VERSION 5.8 ;
BUSBITCHARS "[]" ;
DIVIDERCHAR "/" ;

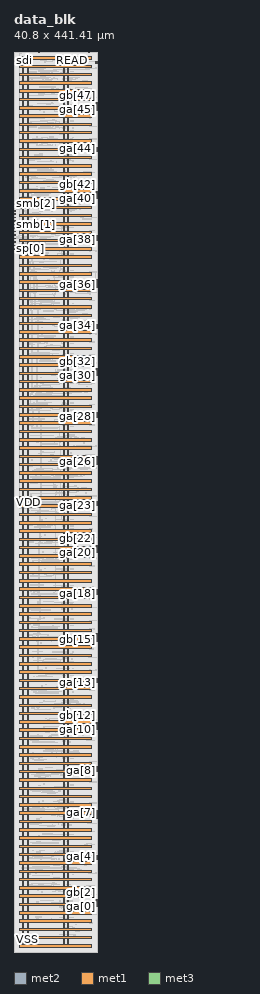
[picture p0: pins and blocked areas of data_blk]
MACRO data_blk
  CLASS BLOCK ;
  FOREIGN data_blk 0 0 ;
  ORIGIN 0 0 ;
  SIZE 40.800 BY 441.410 ;
  SYMMETRY X Y ;
  PIN READ
    DIRECTION INPUT ;
    USE SIGNAL ;
    PORT
      LAYER met2 ;
        RECT 28.490 440.925 28.630 441.410 ;
    END
  END READ
  PIN VDD
    DIRECTION INOUT ;
    USE POWER ;
    PORT
      LAYER met1 ;
        RECT 2.880 2.335 37.920 3.585 ;
        RECT 2.880 10.475 37.920 11.725 ;
        RECT 2.880 18.615 37.920 19.865 ;
        RECT 2.880 26.755 37.920 28.005 ;
        RECT 2.880 34.895 37.920 36.145 ;
        RECT 2.880 43.035 37.920 44.285 ;
        RECT 2.880 51.175 37.920 52.425 ;
        RECT 2.880 59.315 37.920 60.565 ;
        RECT 2.880 67.455 37.920 68.705 ;
        RECT 2.880 75.595 37.920 76.845 ;
        RECT 2.880 83.735 37.920 84.985 ;
        RECT 2.880 91.875 37.920 93.125 ;
        RECT 2.880 100.015 37.920 101.265 ;
        RECT 2.880 108.155 37.920 109.405 ;
        RECT 2.880 116.295 37.920 117.545 ;
        RECT 2.880 124.435 37.920 125.685 ;
        RECT 2.880 132.575 37.920 133.825 ;
        RECT 2.880 140.715 37.920 141.965 ;
        RECT 2.880 148.855 37.920 150.105 ;
        RECT 2.880 156.995 37.920 158.245 ;
        RECT 2.880 165.135 37.920 166.385 ;
        RECT 2.880 173.275 37.920 174.525 ;
        RECT 2.880 181.415 37.920 182.665 ;
        RECT 2.880 189.555 37.920 190.805 ;
        RECT 2.880 197.695 37.920 198.945 ;
        RECT 2.880 205.835 37.920 207.085 ;
        RECT 2.880 213.975 37.920 215.225 ;
        RECT 2.880 222.115 37.920 223.365 ;
        RECT 2.880 230.255 37.920 231.505 ;
        RECT 2.880 238.395 37.920 239.645 ;
        RECT 2.880 246.535 37.920 247.785 ;
        RECT 2.880 254.675 37.920 255.925 ;
        RECT 2.880 262.815 37.920 264.065 ;
        RECT 2.880 270.955 37.920 272.205 ;
        RECT 2.880 279.095 37.920 280.345 ;
        RECT 2.880 287.235 37.920 288.485 ;
        RECT 2.880 295.375 37.920 296.625 ;
        RECT 2.880 303.515 37.920 304.765 ;
        RECT 2.880 311.655 37.920 312.905 ;
        RECT 2.880 319.795 37.920 321.045 ;
        RECT 2.880 327.935 37.920 329.185 ;
        RECT 2.880 336.075 37.920 337.325 ;
        RECT 2.880 344.215 37.920 345.465 ;
        RECT 2.880 352.355 37.920 353.605 ;
        RECT 2.880 360.495 37.920 361.745 ;
        RECT 2.880 368.635 37.920 369.885 ;
        RECT 2.880 376.775 37.920 378.025 ;
        RECT 2.880 384.915 37.920 386.165 ;
        RECT 2.880 393.055 37.920 394.305 ;
        RECT 2.880 401.195 37.920 402.445 ;
        RECT 2.880 409.335 37.920 410.585 ;
        RECT 2.880 417.475 37.920 418.725 ;
        RECT 2.880 425.615 37.920 426.865 ;
        RECT 2.880 433.755 37.920 435.005 ;
      LAYER met2 ;
        RECT 4.380 2.060 4.880 439.350 ;
        RECT 24.380 2.060 24.880 439.350 ;
    END
  END VDD
  PIN VSS
    DIRECTION INOUT ;
    USE GROUND ;
    PORT
      LAYER met1 ;
        RECT 2.880 6.405 37.920 7.655 ;
        RECT 2.880 14.545 37.920 15.795 ;
        RECT 2.880 22.685 37.920 23.935 ;
        RECT 2.880 30.825 37.920 32.075 ;
        RECT 2.880 38.965 37.920 40.215 ;
        RECT 2.880 47.105 37.920 48.355 ;
        RECT 2.880 55.245 37.920 56.495 ;
        RECT 2.880 63.385 37.920 64.635 ;
        RECT 2.880 71.525 37.920 72.775 ;
        RECT 2.880 79.665 37.920 80.915 ;
        RECT 2.880 87.805 37.920 89.055 ;
        RECT 2.880 95.945 37.920 97.195 ;
        RECT 2.880 104.085 37.920 105.335 ;
        RECT 2.880 112.225 37.920 113.475 ;
        RECT 2.880 120.365 37.920 121.615 ;
        RECT 2.880 128.505 37.920 129.755 ;
        RECT 2.880 136.645 37.920 137.895 ;
        RECT 2.880 144.785 37.920 146.035 ;
        RECT 2.880 152.925 37.920 154.175 ;
        RECT 2.880 161.065 37.920 162.315 ;
        RECT 2.880 169.205 37.920 170.455 ;
        RECT 2.880 177.345 37.920 178.595 ;
        RECT 2.880 185.485 37.920 186.735 ;
        RECT 2.880 193.625 37.920 194.875 ;
        RECT 2.880 201.765 37.920 203.015 ;
        RECT 2.880 209.905 37.920 211.155 ;
        RECT 2.880 218.045 37.920 219.295 ;
        RECT 2.880 226.185 37.920 227.435 ;
        RECT 2.880 234.325 37.920 235.575 ;
        RECT 2.880 242.465 37.920 243.715 ;
        RECT 2.880 250.605 37.920 251.855 ;
        RECT 2.880 258.745 37.920 259.995 ;
        RECT 2.880 266.885 37.920 268.135 ;
        RECT 2.880 275.025 37.920 276.275 ;
        RECT 2.880 283.165 37.920 284.415 ;
        RECT 2.880 291.305 37.920 292.555 ;
        RECT 2.880 299.445 37.920 300.695 ;
        RECT 2.880 307.585 37.920 308.835 ;
        RECT 2.880 315.725 37.920 316.975 ;
        RECT 2.880 323.865 37.920 325.115 ;
        RECT 2.880 332.005 37.920 333.255 ;
        RECT 2.880 340.145 37.920 341.395 ;
        RECT 2.880 348.285 37.920 349.535 ;
        RECT 2.880 356.425 37.920 357.675 ;
        RECT 2.880 364.565 37.920 365.815 ;
        RECT 2.880 372.705 37.920 373.955 ;
        RECT 2.880 380.845 37.920 382.095 ;
        RECT 2.880 388.985 37.920 390.235 ;
        RECT 2.880 397.125 37.920 398.375 ;
        RECT 2.880 405.265 37.920 406.515 ;
        RECT 2.880 413.405 37.920 414.655 ;
        RECT 2.880 421.545 37.920 422.795 ;
        RECT 2.880 429.685 37.920 430.935 ;
        RECT 2.880 437.825 37.920 439.075 ;
      LAYER met2 ;
        RECT 6.380 2.060 6.880 439.350 ;
        RECT 26.380 2.060 26.880 439.350 ;
    END
  END VSS
  PIN data_clk
    DIRECTION INPUT ;
    USE SIGNAL ;
    PORT
      LAYER met2 ;
        RECT 12.170 440.925 12.310 441.410 ;
    END
  END data_clk
  PIN dload
    DIRECTION INPUT ;
    USE SIGNAL ;
    PORT
      LAYER met2 ;
        RECT 20.330 440.925 20.470 441.410 ;
    END
  END dload
  PIN ga[0]
    DIRECTION OUTPUT ;
    USE SIGNAL ;
    PORT
      LAYER met2 ;
        RECT 39.800 22.270 40.800 22.610 ;
    END
  END ga[0]
  PIN ga[1]
    DIRECTION OUTPUT ;
    USE SIGNAL ;
    PORT
      LAYER met2 ;
        RECT 39.800 23.550 40.800 23.890 ;
    END
  END ga[1]
  PIN ga[2]
    DIRECTION OUTPUT ;
    USE SIGNAL ;
    PORT
      LAYER met2 ;
        RECT 39.800 24.830 40.800 25.170 ;
    END
  END ga[2]
  PIN ga[3]
    DIRECTION OUTPUT ;
    USE SIGNAL ;
    PORT
      LAYER met2 ;
        RECT 39.800 45.250 40.800 45.590 ;
    END
  END ga[3]
  PIN ga[4]
    DIRECTION OUTPUT ;
    USE SIGNAL ;
    PORT
      LAYER met2 ;
        RECT 39.800 46.530 40.800 46.870 ;
    END
  END ga[4]
  PIN ga[5]
    DIRECTION OUTPUT ;
    USE SIGNAL ;
    PORT
      LAYER met2 ;
        RECT 39.800 65.670 40.800 66.010 ;
    END
  END ga[5]
  PIN ga[6]
    DIRECTION OUTPUT ;
    USE SIGNAL ;
    PORT
      LAYER met2 ;
        RECT 39.800 66.950 40.800 67.290 ;
    END
  END ga[6]
  PIN ga[7]
    DIRECTION OUTPUT ;
    USE SIGNAL ;
    PORT
      LAYER met2 ;
        RECT 39.800 68.230 40.800 68.570 ;
    END
  END ga[7]
  PIN ga[8]
    DIRECTION OUTPUT ;
    USE SIGNAL ;
    PORT
      LAYER met2 ;
        RECT 39.800 88.650 40.800 88.990 ;
    END
  END ga[8]
  PIN ga[9]
    DIRECTION OUTPUT ;
    USE SIGNAL ;
    PORT
      LAYER met2 ;
        RECT 39.800 89.930 40.800 90.270 ;
    END
  END ga[9]
  PIN ga[10]
    DIRECTION OUTPUT ;
    USE SIGNAL ;
    PORT
      LAYER met2 ;
        RECT 39.800 109.070 40.800 109.410 ;
    END
  END ga[10]
  PIN ga[11]
    DIRECTION OUTPUT ;
    USE SIGNAL ;
    PORT
      LAYER met2 ;
        RECT 39.800 110.350 40.800 110.690 ;
    END
  END ga[11]
  PIN ga[12]
    DIRECTION OUTPUT ;
    USE SIGNAL ;
    PORT
      LAYER met2 ;
        RECT 39.800 111.630 40.800 111.970 ;
    END
  END ga[12]
  PIN ga[13]
    DIRECTION OUTPUT ;
    USE SIGNAL ;
    PORT
      LAYER met2 ;
        RECT 39.800 132.050 40.800 132.390 ;
    END
  END ga[13]
  PIN ga[14]
    DIRECTION OUTPUT ;
    USE SIGNAL ;
    PORT
      LAYER met2 ;
        RECT 39.800 133.330 40.800 133.670 ;
    END
  END ga[14]
  PIN ga[15]
    DIRECTION OUTPUT ;
    USE SIGNAL ;
    PORT
      LAYER met2 ;
        RECT 39.800 152.470 40.800 152.810 ;
    END
  END ga[15]
  PIN ga[16]
    DIRECTION OUTPUT ;
    USE SIGNAL ;
    PORT
      LAYER met2 ;
        RECT 39.800 153.750 40.800 154.090 ;
    END
  END ga[16]
  PIN ga[17]
    DIRECTION OUTPUT ;
    USE SIGNAL ;
    PORT
      LAYER met2 ;
        RECT 39.800 155.030 40.800 155.370 ;
    END
  END ga[17]
  PIN ga[18]
    DIRECTION OUTPUT ;
    USE SIGNAL ;
    PORT
      LAYER met2 ;
        RECT 39.800 175.450 40.800 175.790 ;
    END
  END ga[18]
  PIN ga[19]
    DIRECTION OUTPUT ;
    USE SIGNAL ;
    PORT
      LAYER met2 ;
        RECT 39.800 176.730 40.800 177.070 ;
    END
  END ga[19]
  PIN ga[20]
    DIRECTION OUTPUT ;
    USE SIGNAL ;
    PORT
      LAYER met2 ;
        RECT 39.800 195.870 40.800 196.210 ;
    END
  END ga[20]
  PIN ga[21]
    DIRECTION OUTPUT ;
    USE SIGNAL ;
    PORT
      LAYER met2 ;
        RECT 39.800 197.150 40.800 197.490 ;
    END
  END ga[21]
  PIN ga[22]
    DIRECTION OUTPUT ;
    USE SIGNAL ;
    PORT
      LAYER met2 ;
        RECT 39.800 198.430 40.800 198.770 ;
    END
  END ga[22]
  PIN ga[23]
    DIRECTION OUTPUT ;
    USE SIGNAL ;
    PORT
      LAYER met2 ;
        RECT 39.800 218.850 40.800 219.190 ;
    END
  END ga[23]
  PIN ga[24]
    DIRECTION OUTPUT ;
    USE SIGNAL ;
    PORT
      LAYER met2 ;
        RECT 39.800 220.130 40.800 220.470 ;
    END
  END ga[24]
  PIN ga[25]
    DIRECTION OUTPUT ;
    USE SIGNAL ;
    PORT
      LAYER met2 ;
        RECT 39.800 239.270 40.800 239.610 ;
    END
  END ga[25]
  PIN ga[26]
    DIRECTION OUTPUT ;
    USE SIGNAL ;
    PORT
      LAYER met2 ;
        RECT 39.800 240.550 40.800 240.890 ;
    END
  END ga[26]
  PIN ga[27]
    DIRECTION OUTPUT ;
    USE SIGNAL ;
    PORT
      LAYER met2 ;
        RECT 39.800 241.830 40.800 242.170 ;
    END
  END ga[27]
  PIN ga[28]
    DIRECTION OUTPUT ;
    USE SIGNAL ;
    PORT
      LAYER met2 ;
        RECT 39.800 262.250 40.800 262.590 ;
    END
  END ga[28]
  PIN ga[29]
    DIRECTION OUTPUT ;
    USE SIGNAL ;
    PORT
      LAYER met2 ;
        RECT 39.800 263.530 40.800 263.870 ;
    END
  END ga[29]
  PIN ga[30]
    DIRECTION OUTPUT ;
    USE SIGNAL ;
    PORT
      LAYER met2 ;
        RECT 39.800 282.670 40.800 283.010 ;
    END
  END ga[30]
  PIN ga[31]
    DIRECTION OUTPUT ;
    USE SIGNAL ;
    PORT
      LAYER met2 ;
        RECT 39.800 283.950 40.800 284.290 ;
    END
  END ga[31]
  PIN ga[32]
    DIRECTION OUTPUT ;
    USE SIGNAL ;
    PORT
      LAYER met2 ;
        RECT 39.800 285.230 40.800 285.570 ;
    END
  END ga[32]
  PIN ga[33]
    DIRECTION OUTPUT ;
    USE SIGNAL ;
    PORT
      LAYER met2 ;
        RECT 39.800 305.650 40.800 305.990 ;
    END
  END ga[33]
  PIN ga[34]
    DIRECTION OUTPUT ;
    USE SIGNAL ;
    PORT
      LAYER met2 ;
        RECT 39.800 306.930 40.800 307.270 ;
    END
  END ga[34]
  PIN ga[35]
    DIRECTION OUTPUT ;
    USE SIGNAL ;
    PORT
      LAYER met2 ;
        RECT 39.800 326.070 40.800 326.410 ;
    END
  END ga[35]
  PIN ga[36]
    DIRECTION OUTPUT ;
    USE SIGNAL ;
    PORT
      LAYER met2 ;
        RECT 39.800 327.350 40.800 327.690 ;
    END
  END ga[36]
  PIN ga[37]
    DIRECTION OUTPUT ;
    USE SIGNAL ;
    PORT
      LAYER met2 ;
        RECT 39.800 328.630 40.800 328.970 ;
    END
  END ga[37]
  PIN ga[38]
    DIRECTION OUTPUT ;
    USE SIGNAL ;
    PORT
      LAYER met2 ;
        RECT 39.800 349.050 40.800 349.390 ;
    END
  END ga[38]
  PIN ga[39]
    DIRECTION OUTPUT ;
    USE SIGNAL ;
    PORT
      LAYER met2 ;
        RECT 39.800 350.330 40.800 350.670 ;
    END
  END ga[39]
  PIN ga[40]
    DIRECTION OUTPUT ;
    USE SIGNAL ;
    PORT
      LAYER met2 ;
        RECT 39.800 369.470 40.800 369.810 ;
    END
  END ga[40]
  PIN ga[41]
    DIRECTION OUTPUT ;
    USE SIGNAL ;
    PORT
      LAYER met2 ;
        RECT 39.800 370.750 40.800 371.090 ;
    END
  END ga[41]
  PIN ga[42]
    DIRECTION OUTPUT ;
    USE SIGNAL ;
    PORT
      LAYER met2 ;
        RECT 39.800 372.030 40.800 372.370 ;
    END
  END ga[42]
  PIN ga[43]
    DIRECTION OUTPUT ;
    USE SIGNAL ;
    PORT
      LAYER met2 ;
        RECT 39.800 392.450 40.800 392.790 ;
    END
  END ga[43]
  PIN ga[44]
    DIRECTION OUTPUT ;
    USE SIGNAL ;
    PORT
      LAYER met2 ;
        RECT 39.800 393.730 40.800 394.070 ;
    END
  END ga[44]
  PIN ga[45]
    DIRECTION OUTPUT ;
    USE SIGNAL ;
    PORT
      LAYER met2 ;
        RECT 39.800 412.870 40.800 413.210 ;
    END
  END ga[45]
  PIN ga[46]
    DIRECTION OUTPUT ;
    USE SIGNAL ;
    PORT
      LAYER met2 ;
        RECT 39.800 414.150 40.800 414.490 ;
    END
  END ga[46]
  PIN ga[47]
    DIRECTION OUTPUT ;
    USE SIGNAL ;
    PORT
      LAYER met2 ;
        RECT 39.800 415.430 40.800 415.770 ;
    END
  END ga[47]
  PIN ga[48]
    DIRECTION OUTPUT ;
    USE SIGNAL ;
    PORT
      LAYER met2 ;
        RECT 39.800 435.850 40.800 436.190 ;
    END
  END ga[48]
  PIN gb[0]
    DIRECTION OUTPUT ;
    USE SIGNAL ;
    PORT
      LAYER met2 ;
        RECT 39.800 22.910 40.800 23.250 ;
    END
  END gb[0]
  PIN gb[1]
    DIRECTION OUTPUT ;
    USE SIGNAL ;
    PORT
      LAYER met2 ;
        RECT 39.800 24.190 40.800 24.530 ;
    END
  END gb[1]
  PIN gb[2]
    DIRECTION OUTPUT ;
    USE SIGNAL ;
    PORT
      LAYER met2 ;
        RECT 39.800 25.470 40.800 25.810 ;
    END
  END gb[2]
  PIN gb[3]
    DIRECTION OUTPUT ;
    USE SIGNAL ;
    PORT
      LAYER met2 ;
        RECT 39.800 45.890 40.800 46.230 ;
    END
  END gb[3]
  PIN gb[4]
    DIRECTION OUTPUT ;
    USE SIGNAL ;
    PORT
      LAYER met2 ;
        RECT 39.800 47.170 40.800 47.510 ;
    END
  END gb[4]
  PIN gb[5]
    DIRECTION OUTPUT ;
    USE SIGNAL ;
    PORT
      LAYER met2 ;
        RECT 39.800 66.310 40.800 66.650 ;
    END
  END gb[5]
  PIN gb[6]
    DIRECTION OUTPUT ;
    USE SIGNAL ;
    PORT
      LAYER met2 ;
        RECT 39.800 67.590 40.800 67.930 ;
    END
  END gb[6]
  PIN gb[7]
    DIRECTION OUTPUT ;
    USE SIGNAL ;
    PORT
      LAYER met2 ;
        RECT 39.800 68.870 40.800 69.210 ;
    END
  END gb[7]
  PIN gb[8]
    DIRECTION OUTPUT ;
    USE SIGNAL ;
    PORT
      LAYER met2 ;
        RECT 39.800 89.290 40.800 89.630 ;
    END
  END gb[8]
  PIN gb[9]
    DIRECTION OUTPUT ;
    USE SIGNAL ;
    PORT
      LAYER met2 ;
        RECT 39.800 90.570 40.800 90.910 ;
    END
  END gb[9]
  PIN gb[10]
    DIRECTION OUTPUT ;
    USE SIGNAL ;
    PORT
      LAYER met2 ;
        RECT 39.800 109.710 40.800 110.050 ;
    END
  END gb[10]
  PIN gb[11]
    DIRECTION OUTPUT ;
    USE SIGNAL ;
    PORT
      LAYER met2 ;
        RECT 39.800 110.990 40.800 111.330 ;
    END
  END gb[11]
  PIN gb[12]
    DIRECTION OUTPUT ;
    USE SIGNAL ;
    PORT
      LAYER met2 ;
        RECT 39.800 112.270 40.800 112.610 ;
    END
  END gb[12]
  PIN gb[13]
    DIRECTION OUTPUT ;
    USE SIGNAL ;
    PORT
      LAYER met2 ;
        RECT 39.800 132.690 40.800 133.030 ;
    END
  END gb[13]
  PIN gb[14]
    DIRECTION OUTPUT ;
    USE SIGNAL ;
    PORT
      LAYER met2 ;
        RECT 39.800 133.970 40.800 134.310 ;
    END
  END gb[14]
  PIN gb[15]
    DIRECTION OUTPUT ;
    USE SIGNAL ;
    PORT
      LAYER met2 ;
        RECT 39.800 153.110 40.800 153.450 ;
    END
  END gb[15]
  PIN gb[16]
    DIRECTION OUTPUT ;
    USE SIGNAL ;
    PORT
      LAYER met2 ;
        RECT 39.800 154.390 40.800 154.730 ;
    END
  END gb[16]
  PIN gb[17]
    DIRECTION OUTPUT ;
    USE SIGNAL ;
    PORT
      LAYER met2 ;
        RECT 39.800 155.670 40.800 156.010 ;
    END
  END gb[17]
  PIN gb[18]
    DIRECTION OUTPUT ;
    USE SIGNAL ;
    PORT
      LAYER met2 ;
        RECT 39.800 176.090 40.800 176.430 ;
    END
  END gb[18]
  PIN gb[19]
    DIRECTION OUTPUT ;
    USE SIGNAL ;
    PORT
      LAYER met2 ;
        RECT 39.800 177.370 40.800 177.710 ;
    END
  END gb[19]
  PIN gb[20]
    DIRECTION OUTPUT ;
    USE SIGNAL ;
    PORT
      LAYER met2 ;
        RECT 39.800 196.510 40.800 196.850 ;
    END
  END gb[20]
  PIN gb[21]
    DIRECTION OUTPUT ;
    USE SIGNAL ;
    PORT
      LAYER met2 ;
        RECT 39.800 197.790 40.800 198.130 ;
    END
  END gb[21]
  PIN gb[22]
    DIRECTION OUTPUT ;
    USE SIGNAL ;
    PORT
      LAYER met2 ;
        RECT 39.800 199.070 40.800 199.410 ;
    END
  END gb[22]
  PIN gb[23]
    DIRECTION OUTPUT ;
    USE SIGNAL ;
    PORT
      LAYER met2 ;
        RECT 39.800 219.490 40.800 219.830 ;
    END
  END gb[23]
  PIN gb[24]
    DIRECTION OUTPUT ;
    USE SIGNAL ;
    PORT
      LAYER met2 ;
        RECT 39.800 220.770 40.800 221.110 ;
    END
  END gb[24]
  PIN gb[25]
    DIRECTION OUTPUT ;
    USE SIGNAL ;
    PORT
      LAYER met2 ;
        RECT 39.800 239.910 40.800 240.250 ;
    END
  END gb[25]
  PIN gb[26]
    DIRECTION OUTPUT ;
    USE SIGNAL ;
    PORT
      LAYER met2 ;
        RECT 39.800 241.190 40.800 241.530 ;
    END
  END gb[26]
  PIN gb[27]
    DIRECTION OUTPUT ;
    USE SIGNAL ;
    PORT
      LAYER met2 ;
        RECT 39.800 242.470 40.800 242.810 ;
    END
  END gb[27]
  PIN gb[28]
    DIRECTION OUTPUT ;
    USE SIGNAL ;
    PORT
      LAYER met2 ;
        RECT 39.800 262.890 40.800 263.230 ;
    END
  END gb[28]
  PIN gb[29]
    DIRECTION OUTPUT ;
    USE SIGNAL ;
    PORT
      LAYER met2 ;
        RECT 39.800 264.170 40.800 264.510 ;
    END
  END gb[29]
  PIN gb[30]
    DIRECTION OUTPUT ;
    USE SIGNAL ;
    PORT
      LAYER met2 ;
        RECT 39.800 283.310 40.800 283.650 ;
    END
  END gb[30]
  PIN gb[31]
    DIRECTION OUTPUT ;
    USE SIGNAL ;
    PORT
      LAYER met2 ;
        RECT 39.800 284.590 40.800 284.930 ;
    END
  END gb[31]
  PIN gb[32]
    DIRECTION OUTPUT ;
    USE SIGNAL ;
    PORT
      LAYER met2 ;
        RECT 39.800 285.870 40.800 286.210 ;
    END
  END gb[32]
  PIN gb[33]
    DIRECTION OUTPUT ;
    USE SIGNAL ;
    PORT
      LAYER met2 ;
        RECT 39.800 306.290 40.800 306.630 ;
    END
  END gb[33]
  PIN gb[34]
    DIRECTION OUTPUT ;
    USE SIGNAL ;
    PORT
      LAYER met2 ;
        RECT 39.800 307.570 40.800 307.910 ;
    END
  END gb[34]
  PIN gb[35]
    DIRECTION OUTPUT ;
    USE SIGNAL ;
    PORT
      LAYER met2 ;
        RECT 39.800 326.710 40.800 327.050 ;
    END
  END gb[35]
  PIN gb[36]
    DIRECTION OUTPUT ;
    USE SIGNAL ;
    PORT
      LAYER met2 ;
        RECT 39.800 327.990 40.800 328.330 ;
    END
  END gb[36]
  PIN gb[37]
    DIRECTION OUTPUT ;
    USE SIGNAL ;
    PORT
      LAYER met2 ;
        RECT 39.800 329.270 40.800 329.610 ;
    END
  END gb[37]
  PIN gb[38]
    DIRECTION OUTPUT ;
    USE SIGNAL ;
    PORT
      LAYER met2 ;
        RECT 39.800 349.690 40.800 350.030 ;
    END
  END gb[38]
  PIN gb[39]
    DIRECTION OUTPUT ;
    USE SIGNAL ;
    PORT
      LAYER met2 ;
        RECT 39.800 350.970 40.800 351.310 ;
    END
  END gb[39]
  PIN gb[40]
    DIRECTION OUTPUT ;
    USE SIGNAL ;
    PORT
      LAYER met2 ;
        RECT 39.800 370.110 40.800 370.450 ;
    END
  END gb[40]
  PIN gb[41]
    DIRECTION OUTPUT ;
    USE SIGNAL ;
    PORT
      LAYER met2 ;
        RECT 39.800 371.390 40.800 371.730 ;
    END
  END gb[41]
  PIN gb[42]
    DIRECTION OUTPUT ;
    USE SIGNAL ;
    PORT
      LAYER met2 ;
        RECT 39.800 372.670 40.800 373.010 ;
    END
  END gb[42]
  PIN gb[43]
    DIRECTION OUTPUT ;
    USE SIGNAL ;
    PORT
      LAYER met2 ;
        RECT 39.800 393.090 40.800 393.430 ;
    END
  END gb[43]
  PIN gb[44]
    DIRECTION OUTPUT ;
    USE SIGNAL ;
    PORT
      LAYER met2 ;
        RECT 39.800 394.370 40.800 394.710 ;
    END
  END gb[44]
  PIN gb[45]
    DIRECTION OUTPUT ;
    USE SIGNAL ;
    PORT
      LAYER met2 ;
        RECT 39.800 413.510 40.800 413.850 ;
    END
  END gb[45]
  PIN gb[46]
    DIRECTION OUTPUT ;
    USE SIGNAL ;
    PORT
      LAYER met2 ;
        RECT 39.800 414.790 40.800 415.130 ;
    END
  END gb[46]
  PIN gb[47]
    DIRECTION OUTPUT ;
    USE SIGNAL ;
    PORT
      LAYER met2 ;
        RECT 39.800 416.070 40.800 416.410 ;
    END
  END gb[47]
  PIN gb[48]
    DIRECTION OUTPUT ;
    USE SIGNAL ;
    PORT
      LAYER met2 ;
        RECT 39.800 436.490 40.800 436.830 ;
    END
  END gb[48]
  PIN rstb
    DIRECTION INPUT ;
    USE SIGNAL ;
    PORT
      LAYER met2 ;
        RECT 36.650 440.925 36.790 441.410 ;
    END
  END rstb
  PIN sdi
    DIRECTION INPUT ;
    USE SIGNAL ;
    PORT
      LAYER met2 ;
        RECT 4.010 440.925 4.150 441.410 ;
    END
  END sdi
  PIN sm[0]
    DIRECTION OUTPUT ;
    USE SIGNAL ;
    PORT
      LAYER met3 ;
        RECT 0.000 348.075 0.595 348.375 ;
    END
  END sm[0]
  PIN sm[1]
    DIRECTION OUTPUT ;
    USE SIGNAL ;
    PORT
      LAYER met3 ;
        RECT 0.000 354.895 0.800 355.195 ;
    END
  END sm[1]
  PIN sm[2]
    DIRECTION OUTPUT ;
    USE SIGNAL ;
    PORT
      LAYER met3 ;
        RECT 0.000 361.715 0.800 362.015 ;
    END
  END sm[2]
  PIN smb[0]
    DIRECTION OUTPUT ;
    USE SIGNAL ;
    PORT
      LAYER met3 ;
        RECT 0.000 349.780 0.595 350.080 ;
    END
  END smb[0]
  PIN smb[1]
    DIRECTION OUTPUT ;
    USE SIGNAL ;
    PORT
      LAYER met3 ;
        RECT 0.000 356.600 0.595 356.900 ;
    END
  END smb[1]
  PIN smb[2]
    DIRECTION OUTPUT ;
    USE SIGNAL ;
    PORT
      LAYER met3 ;
        RECT 0.000 363.420 0.595 363.720 ;
    END
  END smb[2]
  PIN sp[0]
    DIRECTION OUTPUT ;
    USE SIGNAL ;
    PORT
      LAYER met3 ;
        RECT 0.000 344.665 0.595 344.965 ;
    END
  END sp[0]
  PIN sp[1]
    DIRECTION OUTPUT ;
    USE SIGNAL ;
    PORT
      LAYER met3 ;
        RECT 0.000 351.485 0.800 351.785 ;
    END
  END sp[1]
  PIN sp[2]
    DIRECTION OUTPUT ;
    USE SIGNAL ;
    PORT
      LAYER met3 ;
        RECT 0.000 358.305 0.800 358.605 ;
    END
  END sp[2]
  PIN spb[0]
    DIRECTION OUTPUT ;
    USE SIGNAL ;
    PORT
      LAYER met3 ;
        RECT 0.000 346.370 0.800 346.670 ;
    END
  END spb[0]
  PIN spb[1]
    DIRECTION OUTPUT ;
    USE SIGNAL ;
    PORT
      LAYER met3 ;
        RECT 0.000 353.190 0.595 353.490 ;
    END
  END spb[1]
  PIN spb[2]
    DIRECTION OUTPUT ;
    USE SIGNAL ;
    PORT
      LAYER met3 ;
        RECT 0.000 360.010 0.800 360.310 ;
    END
  END spb[2]
  OBS
    LAYER li1 ;
      RECT 0.000 0.000 40.800 441.410 ;
    LAYER met1 ;
      RECT 19.295 330.850 19.585 330.895 ;
      RECT 19.295 331.035 19.585 331.080 ;
      RECT 21.695 331.035 21.985 331.080 ;
      RECT 22.730 330.895 22.870 331.265 ;
      RECT 19.295 330.895 22.730 331.035 ;
      RECT 21.695 330.850 21.985 330.895 ;
      RECT 22.730 331.265 25.040 331.405 ;
      RECT 25.040 331.205 25.360 331.465 ;
      RECT 15.935 331.590 16.225 331.635 ;
      RECT 18.335 331.590 18.625 331.635 ;
      RECT 15.935 331.775 16.225 331.820 ;
      RECT 18.335 331.775 18.625 331.820 ;
      RECT 15.935 331.635 22.160 331.775 ;
      RECT 22.160 331.575 22.480 331.835 ;
      RECT 14.480 335.645 14.800 335.705 ;
      RECT 20.810 335.335 20.950 335.705 ;
      RECT 17.450 335.335 20.810 335.475 ;
      RECT 20.810 335.705 21.695 335.845 ;
      RECT 21.695 335.660 21.985 335.890 ;
      RECT 14.800 335.705 17.450 335.845 ;
      RECT 14.480 335.705 14.800 335.905 ;
      RECT 17.450 335.475 17.590 335.845 ;
      RECT 13.055 338.620 13.345 338.665 ;
      RECT 15.455 338.620 15.745 338.665 ;
      RECT 13.055 338.805 13.345 338.850 ;
      RECT 15.455 338.805 15.745 338.850 ;
      RECT 13.055 338.665 20.735 338.805 ;
      RECT 20.735 338.620 21.025 338.850 ;
      RECT 17.360 339.715 17.680 339.775 ;
      RECT 25.130 339.405 25.270 339.775 ;
      RECT 18.410 339.405 25.130 339.545 ;
      RECT 25.130 339.775 26.015 339.915 ;
      RECT 26.015 339.730 26.305 339.960 ;
      RECT 17.680 339.775 18.410 339.915 ;
      RECT 17.360 339.775 17.680 339.975 ;
      RECT 18.410 339.545 18.550 339.915 ;
      RECT 12.575 347.130 12.865 347.175 ;
      RECT 15.455 347.130 15.745 347.175 ;
      RECT 22.175 347.130 22.465 347.175 ;
      RECT 12.575 347.315 12.865 347.360 ;
      RECT 15.455 347.315 15.745 347.360 ;
      RECT 22.175 347.315 22.465 347.360 ;
      RECT 12.575 347.175 23.120 347.315 ;
      RECT 23.120 347.115 23.440 347.375 ;
      RECT 18.320 351.925 18.640 351.985 ;
      RECT 23.690 351.245 23.830 351.985 ;
      RECT 20.330 351.245 23.690 351.385 ;
      RECT 23.690 351.985 24.575 352.125 ;
      RECT 24.575 351.940 24.865 352.170 ;
      RECT 18.640 351.985 20.330 352.125 ;
      RECT 18.320 351.985 18.640 352.185 ;
      RECT 20.330 351.385 20.470 352.125 ;
      RECT 13.040 355.255 13.360 355.315 ;
      RECT 13.535 355.270 13.825 355.315 ;
      RECT 23.690 354.945 23.830 355.315 ;
      RECT 17.930 354.945 23.690 355.085 ;
      RECT 23.210 354.775 23.350 354.945 ;
      RECT 23.120 354.515 23.440 354.775 ;
      RECT 25.055 355.270 25.345 355.315 ;
      RECT 13.535 355.455 13.825 355.500 ;
      RECT 13.040 355.315 17.930 355.455 ;
      RECT 17.930 355.085 18.070 355.455 ;
      RECT 25.055 355.455 25.345 355.500 ;
      RECT 13.040 355.455 13.360 355.515 ;
      RECT 23.690 355.315 27.440 355.455 ;
      RECT 27.440 355.255 27.760 355.515 ;
      RECT 22.730 374.555 23.135 374.695 ;
      RECT 23.135 374.510 23.425 374.740 ;
      RECT 18.800 374.865 19.120 374.925 ;
      RECT 19.120 374.925 22.730 375.065 ;
      RECT 18.800 374.925 19.120 375.125 ;
      RECT 22.730 374.695 22.870 375.065 ;
      RECT 18.800 379.675 19.120 379.735 ;
      RECT 18.800 379.735 23.135 379.875 ;
      RECT 23.135 379.690 23.425 379.920 ;
      RECT 18.800 379.875 19.120 379.935 ;
      RECT 10.160 382.635 10.480 382.695 ;
      RECT 10.160 382.835 10.480 382.895 ;
      RECT 10.160 382.695 20.720 382.835 ;
      RECT 20.720 382.635 21.040 382.895 ;
      RECT 20.720 387.445 21.040 387.705 ;
      RECT 16.415 398.560 16.705 398.605 ;
      RECT 16.415 398.745 16.705 398.790 ;
      RECT 16.415 398.605 21.200 398.745 ;
      RECT 21.200 398.545 21.520 398.805 ;
      RECT 20.240 404.465 20.560 404.525 ;
      RECT 20.240 404.525 21.695 404.665 ;
      RECT 21.695 404.480 21.985 404.710 ;
      RECT 20.240 404.665 20.560 404.725 ;
      RECT 20.240 407.055 20.560 407.115 ;
      RECT 20.240 407.115 22.175 407.255 ;
      RECT 22.175 407.070 22.465 407.300 ;
      RECT 20.240 407.255 20.560 407.315 ;
      RECT 13.055 407.810 13.345 407.855 ;
      RECT 18.335 407.810 18.625 407.855 ;
      RECT 13.055 407.995 13.345 408.040 ;
      RECT 18.335 407.995 18.625 408.040 ;
      RECT 13.055 407.855 20.735 407.995 ;
      RECT 20.735 407.810 21.025 408.040 ;
      RECT 19.775 412.250 20.065 412.295 ;
      RECT 19.775 412.435 20.065 412.480 ;
      RECT 23.615 412.435 23.905 412.480 ;
      RECT 24.650 412.295 24.790 412.665 ;
      RECT 19.775 412.295 24.650 412.435 ;
      RECT 23.615 412.250 23.905 412.295 ;
      RECT 24.650 412.665 26.015 412.805 ;
      RECT 26.015 412.620 26.305 412.850 ;
      RECT 20.720 415.935 21.040 416.195 ;
      RECT 19.295 420.390 19.585 420.435 ;
      RECT 21.215 420.390 21.505 420.435 ;
      RECT 19.295 420.575 19.585 420.620 ;
      RECT 21.215 420.575 21.505 420.620 ;
      RECT 19.295 420.435 22.160 420.575 ;
      RECT 22.160 420.375 22.480 420.635 ;
      RECT 20.720 423.335 21.040 423.395 ;
      RECT 20.720 423.395 21.695 423.535 ;
      RECT 21.695 423.350 21.985 423.580 ;
      RECT 20.720 423.535 21.040 423.595 ;
      RECT 3.455 427.420 3.745 427.465 ;
      RECT 3.745 427.465 15.050 427.605 ;
      RECT 3.455 427.465 3.745 427.650 ;
      RECT 15.050 427.420 15.190 427.605 ;
      RECT 18.320 428.145 18.640 428.205 ;
      RECT 18.410 427.465 18.550 428.145 ;
      RECT 17.450 427.280 17.590 427.605 ;
      RECT 17.590 427.465 18.410 427.605 ;
      RECT 15.050 427.280 17.450 427.420 ;
      RECT 18.320 428.205 21.215 428.345 ;
      RECT 21.215 428.160 21.505 428.390 ;
      RECT 18.320 428.345 18.640 428.405 ;
      RECT 12.080 431.845 12.400 431.905 ;
      RECT 17.450 431.535 17.590 431.905 ;
      RECT 13.130 431.535 17.450 431.675 ;
      RECT 20.720 431.845 21.040 431.905 ;
      RECT 17.450 431.905 21.695 432.045 ;
      RECT 21.695 431.860 21.985 432.090 ;
      RECT 12.400 431.905 13.130 432.045 ;
      RECT 12.080 431.905 12.400 432.105 ;
      RECT 13.130 431.675 13.270 432.045 ;
      RECT 20.720 432.045 21.040 432.105 ;
      RECT 19.295 432.785 19.585 432.830 ;
      RECT 35.210 432.645 35.350 433.015 ;
      RECT 19.295 432.600 19.585 432.785 ;
      RECT 19.585 432.645 35.210 432.785 ;
      RECT 35.210 433.015 36.560 433.155 ;
      RECT 36.560 432.955 36.880 433.215 ;
      RECT 20.255 436.670 20.545 436.715 ;
      RECT 22.640 436.655 22.960 436.715 ;
      RECT 20.255 436.855 20.545 436.900 ;
      RECT 20.255 436.715 23.615 436.855 ;
      RECT 23.615 436.670 23.905 436.900 ;
      RECT 22.640 436.855 22.960 436.915 ;
      RECT 21.200 395.955 21.520 396.215 ;
      RECT 24.095 395.970 24.385 396.015 ;
      RECT 24.095 396.155 24.385 396.200 ;
      RECT 24.095 396.015 25.040 396.155 ;
      RECT 25.040 395.955 25.360 396.215 ;
      RECT 28.400 395.955 28.720 396.215 ;
      RECT 22.175 396.710 22.465 396.755 ;
      RECT 22.175 396.895 22.465 396.940 ;
      RECT 22.175 396.755 25.055 396.895 ;
      RECT 25.055 396.710 25.345 396.940 ;
      RECT 24.575 398.560 24.865 398.605 ;
      RECT 24.575 398.745 24.865 398.790 ;
      RECT 24.575 398.605 26.015 398.745 ;
      RECT 26.015 398.560 26.305 398.790 ;
      RECT 25.040 386.335 25.360 386.595 ;
      RECT 27.935 398.560 28.225 398.605 ;
      RECT 27.935 398.745 28.225 398.790 ;
      RECT 27.935 398.605 28.400 398.745 ;
      RECT 28.400 398.545 28.720 398.805 ;
      RECT 37.055 398.560 37.345 398.605 ;
      RECT 37.055 398.745 37.345 398.790 ;
      RECT 37.055 398.605 39.920 398.745 ;
      RECT 39.920 398.545 40.240 398.805 ;
      RECT 25.040 398.915 25.360 399.175 ;
      RECT 28.880 399.285 29.200 399.545 ;
      RECT 22.160 400.765 22.480 400.825 ;
      RECT 22.160 400.825 24.575 400.965 ;
      RECT 24.575 400.780 24.865 401.010 ;
      RECT 22.160 400.965 22.480 401.025 ;
      RECT 27.935 402.630 28.225 402.675 ;
      RECT 27.935 402.815 28.225 402.860 ;
      RECT 27.935 402.675 28.880 402.815 ;
      RECT 28.880 402.615 29.200 402.875 ;
      RECT 22.160 404.095 22.480 404.155 ;
      RECT 22.160 404.155 23.615 404.295 ;
      RECT 23.615 404.110 23.905 404.340 ;
      RECT 22.160 404.295 22.480 404.355 ;
      RECT 25.040 404.095 25.360 404.355 ;
      RECT 28.880 404.095 29.200 404.355 ;
      RECT 28.880 387.815 29.200 388.075 ;
      RECT 24.575 404.850 24.865 404.895 ;
      RECT 24.575 405.035 24.865 405.080 ;
      RECT 24.575 404.895 26.015 405.035 ;
      RECT 26.015 404.850 26.305 405.080 ;
      RECT 37.055 404.850 37.345 404.895 ;
      RECT 37.055 405.035 37.345 405.080 ;
      RECT 37.055 404.895 39.920 405.035 ;
      RECT 39.920 404.835 40.240 405.095 ;
      RECT 25.520 388.185 25.840 388.245 ;
      RECT 25.520 388.245 26.975 388.385 ;
      RECT 26.975 388.200 27.265 388.430 ;
      RECT 25.520 388.385 25.840 388.445 ;
      RECT 25.040 407.055 25.360 407.315 ;
      RECT 25.520 407.055 25.840 407.115 ;
      RECT 25.520 407.115 26.015 407.255 ;
      RECT 26.015 407.070 26.305 407.300 ;
      RECT 25.520 407.255 25.840 407.315 ;
      RECT 27.935 407.440 28.225 407.485 ;
      RECT 27.935 407.625 28.225 407.670 ;
      RECT 27.935 407.485 28.895 407.625 ;
      RECT 28.895 407.440 29.185 407.670 ;
      RECT 27.440 388.185 27.760 388.245 ;
      RECT 27.440 388.245 27.935 388.385 ;
      RECT 27.935 388.200 28.225 388.430 ;
      RECT 27.440 388.385 27.760 388.445 ;
      RECT 37.040 408.905 37.360 409.165 ;
      RECT 24.575 410.770 24.865 410.815 ;
      RECT 24.575 410.955 24.865 411.000 ;
      RECT 24.575 410.815 25.520 410.955 ;
      RECT 25.520 410.755 25.840 411.015 ;
      RECT 27.935 410.770 28.225 410.815 ;
      RECT 27.935 410.955 28.225 411.000 ;
      RECT 27.935 410.815 28.880 410.955 ;
      RECT 28.880 410.755 29.200 411.015 ;
      RECT 25.040 412.235 25.360 412.495 ;
      RECT 28.880 412.235 29.200 412.495 ;
      RECT 37.055 412.250 37.345 412.295 ;
      RECT 37.055 412.435 37.345 412.480 ;
      RECT 37.055 412.295 38.960 412.435 ;
      RECT 38.960 412.235 39.280 412.495 ;
      RECT 37.055 388.570 37.345 388.615 ;
      RECT 37.055 388.755 37.345 388.800 ;
      RECT 37.055 388.615 39.920 388.755 ;
      RECT 39.920 388.555 40.240 388.815 ;
      RECT 37.040 413.175 37.360 413.235 ;
      RECT 40.400 413.550 40.720 413.810 ;
      RECT 40.490 413.035 40.630 413.550 ;
      RECT 37.040 412.975 37.360 413.175 ;
      RECT 37.360 413.035 40.490 413.175 ;
      RECT 37.055 414.840 37.345 414.885 ;
      RECT 37.345 414.885 40.490 415.025 ;
      RECT 37.055 414.885 37.345 415.070 ;
      RECT 40.490 414.450 40.630 415.025 ;
      RECT 40.400 414.190 40.720 414.450 ;
      RECT 22.160 414.825 22.480 414.885 ;
      RECT 22.160 414.885 26.015 415.025 ;
      RECT 26.015 414.840 26.305 415.070 ;
      RECT 22.160 415.025 22.480 415.085 ;
      RECT 25.040 415.195 25.360 415.455 ;
      RECT 27.935 415.580 28.225 415.625 ;
      RECT 27.935 415.765 28.225 415.810 ;
      RECT 27.935 415.625 28.895 415.765 ;
      RECT 28.895 415.580 29.185 415.810 ;
      RECT 21.680 390.405 22.000 390.465 ;
      RECT 21.680 390.465 25.055 390.605 ;
      RECT 25.055 390.420 25.345 390.650 ;
      RECT 21.680 390.605 22.000 390.665 ;
      RECT 26.495 418.910 26.785 418.955 ;
      RECT 26.495 419.095 26.785 419.140 ;
      RECT 26.495 418.955 28.880 419.095 ;
      RECT 28.880 418.895 29.200 419.155 ;
      RECT 35.615 418.910 35.905 418.955 ;
      RECT 35.615 419.095 35.905 419.140 ;
      RECT 35.615 418.955 39.920 419.095 ;
      RECT 39.920 418.895 40.240 419.155 ;
      RECT 26.975 390.420 27.265 390.465 ;
      RECT 26.975 390.605 27.265 390.650 ;
      RECT 26.975 390.465 28.880 390.605 ;
      RECT 28.880 390.405 29.200 390.665 ;
      RECT 27.920 420.375 28.240 420.635 ;
      RECT 23.600 420.745 23.920 420.805 ;
      RECT 23.600 420.945 23.920 421.005 ;
      RECT 23.600 420.805 25.040 420.945 ;
      RECT 25.040 420.745 25.360 421.005 ;
      RECT 22.175 421.130 22.465 421.175 ;
      RECT 22.175 421.315 22.465 421.360 ;
      RECT 22.175 421.175 24.575 421.315 ;
      RECT 24.575 421.130 24.865 421.360 ;
      RECT 27.920 422.965 28.240 423.225 ;
      RECT 24.095 390.790 24.385 390.835 ;
      RECT 24.095 390.975 24.385 391.020 ;
      RECT 24.095 390.835 27.440 390.975 ;
      RECT 27.440 390.775 27.760 391.035 ;
      RECT 25.040 391.145 25.360 391.405 ;
      RECT 25.130 390.975 25.270 391.145 ;
      RECT 23.600 423.335 23.920 423.395 ;
      RECT 23.600 423.395 25.055 423.535 ;
      RECT 25.055 423.350 25.345 423.580 ;
      RECT 23.600 423.535 23.920 423.595 ;
      RECT 26.015 423.350 26.305 423.395 ;
      RECT 26.015 423.535 26.305 423.580 ;
      RECT 26.015 423.395 27.440 423.535 ;
      RECT 27.440 423.335 27.760 423.595 ;
      RECT 28.895 423.165 29.185 423.210 ;
      RECT 38.090 423.025 38.960 423.165 ;
      RECT 38.960 422.965 39.280 423.225 ;
      RECT 29.930 423.025 30.070 423.765 ;
      RECT 28.895 422.980 29.185 423.165 ;
      RECT 29.185 423.025 29.930 423.165 ;
      RECT 34.730 423.210 38.090 423.350 ;
      RECT 38.090 423.165 38.230 423.350 ;
      RECT 29.930 423.765 34.730 423.905 ;
      RECT 34.730 423.350 34.870 423.905 ;
      RECT 35.600 423.705 35.920 423.965 ;
      RECT 27.440 427.035 27.760 427.095 ;
      RECT 27.440 427.095 27.935 427.235 ;
      RECT 27.935 427.050 28.225 427.280 ;
      RECT 27.440 427.235 27.760 427.295 ;
      RECT 33.695 427.050 33.985 427.095 ;
      RECT 33.695 427.235 33.985 427.280 ;
      RECT 33.695 427.095 35.600 427.235 ;
      RECT 35.600 427.035 35.920 427.295 ;
      RECT 27.920 391.145 28.240 391.405 ;
      RECT 23.600 428.145 23.920 428.205 ;
      RECT 23.920 428.205 26.090 428.345 ;
      RECT 23.600 428.205 23.920 428.405 ;
      RECT 26.090 427.975 26.230 428.345 ;
      RECT 30.815 428.530 31.105 428.760 ;
      RECT 30.890 428.205 31.030 428.530 ;
      RECT 29.930 427.835 30.070 428.345 ;
      RECT 30.070 428.205 30.890 428.345 ;
      RECT 26.090 427.835 29.930 427.975 ;
      RECT 26.495 428.530 26.785 428.575 ;
      RECT 26.495 428.715 26.785 428.760 ;
      RECT 28.490 428.760 28.630 428.945 ;
      RECT 28.415 428.530 28.705 428.760 ;
      RECT 26.495 428.575 28.415 428.715 ;
      RECT 28.490 428.945 31.775 429.085 ;
      RECT 31.775 428.900 32.065 429.130 ;
      RECT 22.640 431.105 22.960 431.165 ;
      RECT 22.640 431.165 26.015 431.305 ;
      RECT 26.015 431.120 26.305 431.350 ;
      RECT 22.640 431.305 22.960 431.365 ;
      RECT 27.935 431.860 28.225 431.905 ;
      RECT 27.935 432.045 28.225 432.090 ;
      RECT 27.935 431.905 28.895 432.045 ;
      RECT 28.895 431.860 29.185 432.090 ;
      RECT 36.095 392.640 36.385 392.685 ;
      RECT 36.095 392.825 36.385 392.870 ;
      RECT 36.095 392.685 38.960 392.825 ;
      RECT 38.960 392.625 39.280 392.885 ;
      RECT 23.600 431.845 23.920 431.905 ;
      RECT 23.600 432.045 23.920 432.105 ;
      RECT 23.600 431.905 25.040 432.045 ;
      RECT 25.040 431.845 25.360 432.105 ;
      RECT 26.975 394.490 27.265 394.535 ;
      RECT 26.975 394.675 27.265 394.720 ;
      RECT 26.975 394.535 27.920 394.675 ;
      RECT 27.920 394.475 28.240 394.735 ;
      RECT 37.055 433.340 37.345 433.385 ;
      RECT 37.055 433.525 37.345 433.570 ;
      RECT 37.055 433.385 39.920 433.525 ;
      RECT 39.920 433.325 40.240 433.585 ;
      RECT 27.935 436.670 28.225 436.715 ;
      RECT 27.935 436.855 28.225 436.900 ;
      RECT 27.935 436.715 28.895 436.855 ;
      RECT 28.895 436.670 29.185 436.900 ;
      RECT 36.575 394.490 36.865 394.535 ;
      RECT 36.575 394.675 36.865 394.720 ;
      RECT 36.575 394.535 38.960 394.675 ;
      RECT 38.960 394.475 39.280 394.735 ;
      RECT 37.055 436.670 37.345 436.715 ;
      RECT 37.055 436.855 37.345 436.900 ;
      RECT 37.055 436.715 39.920 436.855 ;
      RECT 39.920 436.655 40.240 436.915 ;
      RECT 25.040 437.025 25.360 437.085 ;
      RECT 25.040 437.225 25.360 437.285 ;
      RECT 25.040 437.085 28.400 437.225 ;
      RECT 28.400 437.025 28.720 437.285 ;
      RECT 24.575 437.410 24.865 437.455 ;
      RECT 24.575 437.595 24.865 437.640 ;
      RECT 24.575 437.455 26.015 437.595 ;
      RECT 26.015 437.410 26.305 437.640 ;
      RECT 5.855 396.710 6.145 396.755 ;
      RECT 5.855 396.895 6.145 396.940 ;
      RECT 5.855 396.755 11.120 396.895 ;
      RECT 11.120 396.695 11.440 396.955 ;
      RECT 18.320 416.305 18.640 416.565 ;
      RECT 7.280 404.835 7.600 405.095 ;
      RECT 18.800 404.835 19.120 404.895 ;
      RECT 18.800 404.895 19.295 405.035 ;
      RECT 19.295 404.850 19.585 405.080 ;
      RECT 18.800 405.035 19.120 405.095 ;
      RECT 7.280 420.005 7.600 420.065 ;
      RECT 7.280 420.065 14.015 420.205 ;
      RECT 14.015 420.020 14.305 420.250 ;
      RECT 7.280 420.205 7.600 420.265 ;
      RECT 12.560 391.515 12.880 391.575 ;
      RECT 12.560 391.575 13.535 391.715 ;
      RECT 13.535 391.530 13.825 391.760 ;
      RECT 12.560 391.715 12.880 391.775 ;
      RECT 17.360 406.685 17.680 406.745 ;
      RECT 16.490 406.745 19.295 406.885 ;
      RECT 19.295 406.700 19.585 406.930 ;
      RECT 7.280 406.885 7.600 406.945 ;
      RECT 17.360 406.885 17.680 406.945 ;
      RECT 8.330 406.745 8.470 407.115 ;
      RECT 7.280 406.685 7.600 406.885 ;
      RECT 7.600 406.745 8.330 406.885 ;
      RECT 8.330 407.115 16.490 407.255 ;
      RECT 16.490 406.885 16.630 407.255 ;
      RECT 12.095 420.760 12.385 420.805 ;
      RECT 12.560 420.745 12.880 420.805 ;
      RECT 18.410 420.435 18.550 420.805 ;
      RECT 15.050 420.435 18.410 420.575 ;
      RECT 12.095 420.945 12.385 420.990 ;
      RECT 12.560 420.945 12.880 421.005 ;
      RECT 12.095 420.805 15.050 420.945 ;
      RECT 15.050 420.575 15.190 420.945 ;
      RECT 18.410 420.805 19.760 420.945 ;
      RECT 19.760 420.745 20.080 421.005 ;
      RECT 11.615 387.460 11.905 387.505 ;
      RECT 16.895 387.460 17.185 387.505 ;
      RECT 11.615 387.645 11.905 387.690 ;
      RECT 16.895 387.645 17.185 387.690 ;
      RECT 11.615 387.505 19.295 387.645 ;
      RECT 19.295 387.460 19.585 387.690 ;
      RECT 18.800 390.405 19.120 390.665 ;
      RECT 7.280 422.965 7.600 423.225 ;
      RECT 14.480 422.965 14.800 423.025 ;
      RECT 14.480 423.025 18.815 423.165 ;
      RECT 18.815 422.980 19.105 423.210 ;
      RECT 14.480 423.165 14.800 423.225 ;
      RECT 7.760 388.185 8.080 388.245 ;
      RECT 7.760 388.245 9.695 388.385 ;
      RECT 9.695 388.200 9.985 388.430 ;
      RECT 7.760 388.385 8.080 388.445 ;
      RECT 18.320 423.335 18.640 423.395 ;
      RECT 18.320 423.395 19.295 423.535 ;
      RECT 19.295 423.350 19.585 423.580 ;
      RECT 18.320 423.535 18.640 423.595 ;
      RECT 11.135 395.600 11.425 395.645 ;
      RECT 16.415 395.600 16.705 395.645 ;
      RECT 11.135 395.785 11.425 395.830 ;
      RECT 16.415 395.785 16.705 395.830 ;
      RECT 11.135 395.645 18.815 395.785 ;
      RECT 18.815 395.600 19.105 395.830 ;
      RECT 9.215 398.930 9.505 398.975 ;
      RECT 10.160 398.915 10.480 398.975 ;
      RECT 9.215 399.115 9.505 399.160 ;
      RECT 16.490 398.975 17.375 399.115 ;
      RECT 17.375 398.930 17.665 399.160 ;
      RECT 10.160 399.115 10.480 399.175 ;
      RECT 12.560 399.115 12.880 399.175 ;
      RECT 13.610 398.975 13.750 399.345 ;
      RECT 9.215 398.975 13.610 399.115 ;
      RECT 12.560 398.915 12.880 398.975 ;
      RECT 13.610 399.345 16.490 399.485 ;
      RECT 16.490 399.115 16.630 399.485 ;
      RECT 18.800 408.165 19.120 408.225 ;
      RECT 18.800 408.225 19.775 408.365 ;
      RECT 19.775 408.180 20.065 408.410 ;
      RECT 18.800 408.365 19.120 408.425 ;
      RECT 7.775 408.920 8.065 408.965 ;
      RECT 12.170 408.595 12.310 408.965 ;
      RECT 8.810 408.595 12.170 408.735 ;
      RECT 8.065 408.965 8.810 409.105 ;
      RECT 7.775 408.965 8.065 409.150 ;
      RECT 8.810 408.735 8.950 409.105 ;
      RECT 12.170 408.965 14.480 409.105 ;
      RECT 14.480 408.905 14.800 409.165 ;
      RECT 20.240 395.585 20.560 395.845 ;
      RECT 12.575 424.090 12.865 424.135 ;
      RECT 17.855 424.090 18.145 424.135 ;
      RECT 12.575 424.275 12.865 424.320 ;
      RECT 17.855 424.275 18.145 424.320 ;
      RECT 12.575 424.135 20.255 424.275 ;
      RECT 20.255 424.090 20.545 424.320 ;
      RECT 11.120 399.655 11.440 399.915 ;
      RECT 17.360 399.655 17.680 399.715 ;
      RECT 17.360 399.715 19.295 399.855 ;
      RECT 19.295 399.670 19.585 399.900 ;
      RECT 17.360 399.855 17.680 399.915 ;
      RECT 15.455 427.790 15.745 427.835 ;
      RECT 15.455 427.975 15.745 428.020 ;
      RECT 15.455 427.835 17.840 427.975 ;
      RECT 17.840 427.775 18.160 428.035 ;
      RECT 8.735 428.160 9.025 428.205 ;
      RECT 14.015 428.160 14.305 428.205 ;
      RECT 8.735 428.345 9.025 428.390 ;
      RECT 14.015 428.345 14.305 428.390 ;
      RECT 8.735 428.205 16.415 428.345 ;
      RECT 16.415 428.160 16.705 428.390 ;
      RECT 14.480 411.865 14.800 412.125 ;
      RECT 7.370 428.405 7.510 428.575 ;
      RECT 7.280 428.145 7.600 428.405 ;
      RECT 7.370 428.575 14.975 428.715 ;
      RECT 14.975 428.530 15.265 428.760 ;
      RECT 6.335 384.500 6.625 384.545 ;
      RECT 16.970 384.175 17.110 384.545 ;
      RECT 7.370 384.175 16.970 384.315 ;
      RECT 6.625 384.545 7.370 384.685 ;
      RECT 6.335 384.545 6.625 384.730 ;
      RECT 7.370 384.315 7.510 384.685 ;
      RECT 16.970 384.545 17.840 384.685 ;
      RECT 17.840 384.485 18.160 384.745 ;
      RECT 10.160 390.775 10.480 390.835 ;
      RECT 11.615 390.790 11.905 390.835 ;
      RECT 10.160 390.835 13.610 390.975 ;
      RECT 11.615 390.975 11.905 391.020 ;
      RECT 13.610 390.665 13.750 390.975 ;
      RECT 13.520 390.405 13.840 390.665 ;
      RECT 10.160 390.975 10.480 391.035 ;
      RECT 6.815 428.900 7.105 428.945 ;
      RECT 6.815 429.085 7.105 429.130 ;
      RECT 6.815 428.945 7.280 429.085 ;
      RECT 7.280 428.885 7.600 429.145 ;
      RECT 19.295 428.900 19.585 428.945 ;
      RECT 19.295 429.085 19.585 429.130 ;
      RECT 19.295 428.945 19.760 429.085 ;
      RECT 19.760 428.885 20.080 429.145 ;
      RECT 12.080 428.885 12.400 429.085 ;
      RECT 13.130 428.945 13.270 429.130 ;
      RECT 12.400 428.945 13.130 429.085 ;
      RECT 15.530 428.945 17.855 429.085 ;
      RECT 17.855 428.900 18.145 429.130 ;
      RECT 12.080 429.085 12.400 429.145 ;
      RECT 13.130 429.130 15.530 429.270 ;
      RECT 15.530 429.085 15.670 429.270 ;
      RECT 18.320 431.105 18.640 431.165 ;
      RECT 18.320 431.165 18.815 431.305 ;
      RECT 18.815 431.120 19.105 431.350 ;
      RECT 18.320 431.305 18.640 431.365 ;
      RECT 12.575 403.740 12.865 403.785 ;
      RECT 17.855 403.740 18.145 403.785 ;
      RECT 12.575 403.925 12.865 403.970 ;
      RECT 17.855 403.925 18.145 403.970 ;
      RECT 12.575 403.785 20.255 403.925 ;
      RECT 20.255 403.740 20.545 403.970 ;
      RECT 7.280 431.475 7.600 431.535 ;
      RECT 7.280 431.535 10.655 431.675 ;
      RECT 10.655 431.490 10.945 431.720 ;
      RECT 7.280 431.675 7.600 431.735 ;
      RECT 17.840 387.815 18.160 388.075 ;
      RECT 12.560 412.605 12.880 412.865 ;
      RECT 16.490 396.015 17.375 396.155 ;
      RECT 17.375 395.970 17.665 396.200 ;
      RECT 12.560 396.155 12.880 396.215 ;
      RECT 13.610 396.015 13.750 396.385 ;
      RECT 12.560 395.955 12.880 396.155 ;
      RECT 12.880 396.015 13.610 396.155 ;
      RECT 13.610 396.385 16.490 396.525 ;
      RECT 16.490 396.155 16.630 396.525 ;
      RECT 12.575 432.230 12.865 432.275 ;
      RECT 17.855 432.230 18.145 432.275 ;
      RECT 12.575 432.415 12.865 432.460 ;
      RECT 17.855 432.415 18.145 432.460 ;
      RECT 12.575 432.275 20.255 432.415 ;
      RECT 20.255 432.230 20.545 432.460 ;
      RECT 7.760 396.325 8.080 396.385 ;
      RECT 7.760 396.385 9.215 396.525 ;
      RECT 9.215 396.340 9.505 396.570 ;
      RECT 7.760 396.525 8.080 396.585 ;
      RECT 7.295 433.340 7.585 433.385 ;
      RECT 14.090 433.015 14.230 433.385 ;
      RECT 8.330 433.015 14.090 433.155 ;
      RECT 7.585 433.385 8.330 433.525 ;
      RECT 7.295 433.385 7.585 433.570 ;
      RECT 8.330 433.155 8.470 433.525 ;
      RECT 14.090 433.385 14.960 433.525 ;
      RECT 14.960 433.325 15.280 433.585 ;
      RECT 6.335 414.840 6.625 414.885 ;
      RECT 6.335 415.025 6.625 415.070 ;
      RECT 6.335 414.885 8.720 415.025 ;
      RECT 8.720 414.825 9.040 415.085 ;
      RECT 14.960 436.285 15.280 436.545 ;
      RECT 17.930 404.155 18.815 404.295 ;
      RECT 18.815 404.110 19.105 404.340 ;
      RECT 12.080 404.295 12.400 404.355 ;
      RECT 13.130 404.155 13.270 404.525 ;
      RECT 12.080 404.095 12.400 404.295 ;
      RECT 12.400 404.155 13.130 404.295 ;
      RECT 13.130 404.525 17.930 404.665 ;
      RECT 17.930 404.295 18.070 404.665 ;
      RECT 7.760 404.465 8.080 404.525 ;
      RECT 7.760 404.525 10.655 404.665 ;
      RECT 10.655 404.480 10.945 404.710 ;
      RECT 7.760 404.665 8.080 404.725 ;
      RECT 6.335 388.570 6.625 388.615 ;
      RECT 6.335 388.755 6.625 388.800 ;
      RECT 6.335 388.615 12.560 388.755 ;
      RECT 12.560 388.555 12.880 388.815 ;
      RECT 15.920 415.565 16.240 415.625 ;
      RECT 15.920 415.625 17.855 415.765 ;
      RECT 17.855 415.580 18.145 415.810 ;
      RECT 15.920 415.765 16.240 415.825 ;
      RECT 11.615 415.950 11.905 415.995 ;
      RECT 16.895 415.950 17.185 415.995 ;
      RECT 11.615 416.135 11.905 416.180 ;
      RECT 16.895 416.135 17.185 416.180 ;
      RECT 11.615 415.995 19.295 416.135 ;
      RECT 19.295 415.950 19.585 416.180 ;
      RECT 13.055 437.040 13.345 437.085 ;
      RECT 13.345 437.085 16.010 437.225 ;
      RECT 13.055 437.085 13.345 437.270 ;
      RECT 16.010 436.855 16.150 437.225 ;
      RECT 18.890 436.715 19.030 437.085 ;
      RECT 16.010 436.715 18.890 436.855 ;
      RECT 19.850 437.085 19.990 437.455 ;
      RECT 18.890 437.085 19.850 437.225 ;
      RECT 19.850 437.455 20.240 437.595 ;
      RECT 20.240 437.395 20.560 437.655 ;
      RECT 14.480 371.535 14.800 371.595 ;
      RECT 14.480 371.595 14.975 371.735 ;
      RECT 14.975 371.550 15.265 371.780 ;
      RECT 14.480 371.735 14.800 371.795 ;
      RECT 6.815 371.920 7.105 371.965 ;
      RECT 6.815 372.105 7.105 372.150 ;
      RECT 6.815 371.965 8.240 372.105 ;
      RECT 8.240 371.905 8.560 372.165 ;
      RECT 10.160 371.905 10.480 371.965 ;
      RECT 10.160 371.965 17.855 372.105 ;
      RECT 17.855 371.920 18.145 372.150 ;
      RECT 10.160 372.105 10.480 372.165 ;
      RECT 19.280 372.275 19.600 372.535 ;
      RECT 5.855 374.325 6.145 374.370 ;
      RECT 10.250 374.185 11.120 374.325 ;
      RECT 11.120 374.125 11.440 374.385 ;
      RECT 6.890 374.185 7.030 374.555 ;
      RECT 5.855 374.140 6.145 374.325 ;
      RECT 6.145 374.185 6.890 374.325 ;
      RECT 6.890 374.555 10.250 374.695 ;
      RECT 10.250 374.325 10.390 374.695 ;
      RECT 13.055 374.510 13.345 374.555 ;
      RECT 13.520 374.495 13.840 374.555 ;
      RECT 13.055 374.695 13.345 374.740 ;
      RECT 13.055 374.555 14.495 374.695 ;
      RECT 14.495 374.510 14.785 374.740 ;
      RECT 13.520 374.695 13.840 374.755 ;
      RECT 9.695 334.920 9.985 334.965 ;
      RECT 9.695 335.105 9.985 335.150 ;
      RECT 9.695 334.965 12.560 335.105 ;
      RECT 12.560 334.905 12.880 335.165 ;
      RECT 11.120 375.235 11.440 375.495 ;
      RECT 16.415 375.250 16.705 375.295 ;
      RECT 16.415 375.435 16.705 375.480 ;
      RECT 16.415 375.295 16.880 375.435 ;
      RECT 16.880 375.235 17.200 375.495 ;
      RECT 19.370 378.255 20.255 378.395 ;
      RECT 20.255 378.210 20.545 378.440 ;
      RECT 14.480 378.395 14.800 378.455 ;
      RECT 16.010 378.255 16.150 378.625 ;
      RECT 14.480 378.195 14.800 378.395 ;
      RECT 14.800 378.255 16.010 378.395 ;
      RECT 16.010 378.625 19.370 378.765 ;
      RECT 19.370 378.395 19.510 378.765 ;
      RECT 8.240 378.935 8.560 379.195 ;
      RECT 7.295 379.320 7.585 379.365 ;
      RECT 9.695 379.320 9.985 379.365 ;
      RECT 7.295 379.505 7.585 379.550 ;
      RECT 9.695 379.505 9.985 379.550 ;
      RECT 7.295 379.365 14.975 379.505 ;
      RECT 14.975 379.320 15.265 379.550 ;
      RECT 8.720 379.675 9.040 379.735 ;
      RECT 8.720 379.875 9.040 379.935 ;
      RECT 8.720 379.735 11.120 379.875 ;
      RECT 11.120 379.675 11.440 379.935 ;
      RECT 10.640 330.465 10.960 330.725 ;
      RECT 5.855 380.060 6.145 380.105 ;
      RECT 5.855 380.245 6.145 380.290 ;
      RECT 5.855 380.105 10.160 380.245 ;
      RECT 10.160 380.045 10.480 380.305 ;
      RECT 17.840 382.265 18.160 382.525 ;
      RECT 7.760 382.635 8.080 382.695 ;
      RECT 7.760 382.695 9.695 382.835 ;
      RECT 9.695 382.650 9.985 382.880 ;
      RECT 7.760 382.835 8.080 382.895 ;
      RECT 12.560 338.235 12.880 338.295 ;
      RECT 12.560 338.295 14.015 338.435 ;
      RECT 14.015 338.250 14.305 338.480 ;
      RECT 12.560 338.435 12.880 338.495 ;
      RECT 11.615 383.390 11.905 383.435 ;
      RECT 16.895 383.390 17.185 383.435 ;
      RECT 11.615 383.575 11.905 383.620 ;
      RECT 16.895 383.575 17.185 383.620 ;
      RECT 11.615 383.435 19.295 383.575 ;
      RECT 19.295 383.390 19.585 383.620 ;
      RECT 8.735 331.220 9.025 331.265 ;
      RECT 8.735 331.405 9.025 331.450 ;
      RECT 8.735 331.265 9.680 331.405 ;
      RECT 9.680 331.205 10.000 331.465 ;
      RECT 7.280 338.605 7.600 338.665 ;
      RECT 10.160 338.605 10.480 338.665 ;
      RECT 7.280 338.665 11.615 338.805 ;
      RECT 11.615 338.620 11.905 338.850 ;
      RECT 7.280 338.805 7.600 338.865 ;
      RECT 10.160 338.805 10.480 338.865 ;
      RECT 14.480 339.715 14.800 339.975 ;
      RECT 10.175 333.440 10.465 333.485 ;
      RECT 10.175 333.625 10.465 333.670 ;
      RECT 10.175 333.485 10.640 333.625 ;
      RECT 10.640 333.425 10.960 333.685 ;
      RECT 14.480 342.675 14.800 342.735 ;
      RECT 14.480 342.735 15.935 342.875 ;
      RECT 15.935 342.690 16.225 342.920 ;
      RECT 14.480 342.875 14.800 342.935 ;
      RECT 14.015 342.135 14.305 342.180 ;
      RECT 9.200 342.135 9.520 342.195 ;
      RECT 10.250 341.995 10.390 342.365 ;
      RECT 9.200 341.935 9.520 342.135 ;
      RECT 9.520 341.995 10.250 342.135 ;
      RECT 10.250 342.365 13.130 342.505 ;
      RECT 13.130 342.135 13.270 342.505 ;
      RECT 16.400 342.675 16.720 342.935 ;
      RECT 16.490 341.995 16.630 342.675 ;
      RECT 13.130 341.995 16.490 342.135 ;
      RECT 14.015 341.950 14.305 341.995 ;
      RECT 1.040 345.635 1.360 345.695 ;
      RECT 1.040 345.695 4.415 345.835 ;
      RECT 4.415 345.650 4.705 345.880 ;
      RECT 1.040 345.835 1.360 345.895 ;
      RECT 8.735 347.130 9.025 347.175 ;
      RECT 8.735 347.315 9.025 347.360 ;
      RECT 8.735 347.175 9.200 347.315 ;
      RECT 9.200 347.115 9.520 347.375 ;
      RECT 11.120 347.115 11.440 347.375 ;
      RECT 18.335 333.810 18.625 333.855 ;
      RECT 18.335 333.995 18.625 334.040 ;
      RECT 18.335 333.855 19.760 333.995 ;
      RECT 19.760 333.795 20.080 334.055 ;
      RECT 3.920 347.115 4.240 347.175 ;
      RECT 4.895 347.130 5.185 347.175 ;
      RECT 4.895 347.315 5.185 347.360 ;
      RECT 3.920 347.175 5.930 347.315 ;
      RECT 5.930 346.945 6.070 347.315 ;
      RECT 3.920 347.315 4.240 347.375 ;
      RECT 8.330 346.805 8.470 347.545 ;
      RECT 5.930 346.805 8.330 346.945 ;
      RECT 8.330 347.545 12.095 347.685 ;
      RECT 12.095 347.500 12.385 347.730 ;
      RECT 5.840 347.855 6.160 347.915 ;
      RECT 5.840 347.915 7.295 348.055 ;
      RECT 7.295 347.870 7.585 348.100 ;
      RECT 5.840 348.055 6.160 348.115 ;
      RECT 8.240 347.855 8.560 347.915 ;
      RECT 8.240 347.915 14.975 348.055 ;
      RECT 14.975 347.870 15.265 348.100 ;
      RECT 8.240 348.055 8.560 348.115 ;
      RECT 12.560 349.705 12.880 349.765 ;
      RECT 12.560 349.905 12.880 349.965 ;
      RECT 12.560 349.765 15.440 349.905 ;
      RECT 15.440 349.705 15.760 349.965 ;
      RECT 1.040 350.075 1.360 350.135 ;
      RECT 1.040 350.135 3.935 350.275 ;
      RECT 3.935 350.090 4.225 350.320 ;
      RECT 1.040 350.275 1.360 350.335 ;
      RECT 4.970 349.765 5.840 349.905 ;
      RECT 5.840 349.705 6.160 349.965 ;
      RECT 4.895 350.460 5.185 350.690 ;
      RECT 4.970 349.905 5.110 350.460 ;
      RECT 5.840 350.445 6.160 350.705 ;
      RECT 9.200 350.445 9.520 350.705 ;
      RECT 13.055 350.460 13.345 350.505 ;
      RECT 13.055 350.645 13.345 350.690 ;
      RECT 13.055 350.505 17.360 350.645 ;
      RECT 17.360 350.445 17.680 350.705 ;
      RECT 11.615 350.830 11.905 350.875 ;
      RECT 14.015 350.830 14.305 350.875 ;
      RECT 11.615 351.015 11.905 351.060 ;
      RECT 14.015 351.015 14.305 351.060 ;
      RECT 11.615 350.875 19.295 351.015 ;
      RECT 19.295 350.830 19.585 351.060 ;
      RECT 8.720 350.815 9.040 351.075 ;
      RECT 10.160 350.815 10.480 351.075 ;
      RECT 4.490 350.875 5.375 351.015 ;
      RECT 5.375 350.830 5.665 351.060 ;
      RECT 1.040 351.015 1.360 351.075 ;
      RECT 2.090 350.875 2.230 351.245 ;
      RECT 1.040 350.815 1.360 351.015 ;
      RECT 1.360 350.875 2.090 351.015 ;
      RECT 2.090 351.245 4.490 351.385 ;
      RECT 4.490 351.015 4.630 351.385 ;
      RECT 8.330 351.060 8.470 351.245 ;
      RECT 8.255 350.830 8.545 351.060 ;
      RECT 8.330 351.245 11.120 351.385 ;
      RECT 11.120 351.185 11.440 351.445 ;
      RECT 8.735 334.550 9.025 334.595 ;
      RECT 11.135 334.550 11.425 334.595 ;
      RECT 8.735 334.735 9.025 334.780 ;
      RECT 11.135 334.735 11.425 334.780 ;
      RECT 8.735 334.595 16.415 334.735 ;
      RECT 16.415 334.550 16.705 334.780 ;
      RECT 8.720 354.885 9.040 354.945 ;
      RECT 8.720 354.945 9.695 355.085 ;
      RECT 9.695 354.900 9.985 355.130 ;
      RECT 8.720 355.085 9.040 355.145 ;
      RECT 17.360 354.885 17.680 355.145 ;
      RECT 5.375 355.270 5.665 355.315 ;
      RECT 5.665 355.315 6.070 355.455 ;
      RECT 5.930 354.775 6.070 355.315 ;
      RECT 5.840 354.515 6.160 354.775 ;
      RECT 5.375 355.315 5.665 355.500 ;
      RECT 7.295 355.270 7.585 355.315 ;
      RECT 7.295 355.455 7.585 355.500 ;
      RECT 7.295 355.315 9.215 355.455 ;
      RECT 9.215 355.270 9.505 355.500 ;
      RECT 7.280 334.535 7.600 334.795 ;
      RECT 10.730 355.130 10.870 355.315 ;
      RECT 10.655 354.900 10.945 355.130 ;
      RECT 9.770 355.315 11.615 355.455 ;
      RECT 11.615 355.270 11.905 355.500 ;
      RECT 8.720 355.625 9.040 355.685 ;
      RECT 9.040 355.685 9.770 355.825 ;
      RECT 8.720 355.685 9.040 355.885 ;
      RECT 9.770 355.455 9.910 355.825 ;
      RECT 15.455 355.640 15.745 355.685 ;
      RECT 15.455 355.825 15.745 355.870 ;
      RECT 15.455 355.685 16.400 355.825 ;
      RECT 16.400 355.625 16.720 355.885 ;
      RECT 1.040 355.995 1.360 356.055 ;
      RECT 1.040 356.055 4.415 356.195 ;
      RECT 4.415 356.010 4.705 356.240 ;
      RECT 1.040 356.195 1.360 356.255 ;
      RECT 5.360 355.995 5.680 356.055 ;
      RECT 5.360 356.055 13.535 356.195 ;
      RECT 13.535 356.010 13.825 356.240 ;
      RECT 5.360 356.195 5.680 356.255 ;
      RECT 1.040 357.845 1.360 357.905 ;
      RECT 1.040 357.905 4.895 358.045 ;
      RECT 4.895 357.860 5.185 358.090 ;
      RECT 1.040 358.045 1.360 358.105 ;
      RECT 9.770 358.275 13.535 358.415 ;
      RECT 13.535 358.230 13.825 358.460 ;
      RECT 3.920 358.585 4.240 358.645 ;
      RECT 5.375 358.600 5.665 358.645 ;
      RECT 5.375 358.785 5.665 358.830 ;
      RECT 3.920 358.645 9.770 358.785 ;
      RECT 9.770 358.415 9.910 358.785 ;
      RECT 3.920 358.785 4.240 358.845 ;
      RECT 13.040 358.585 13.360 358.845 ;
      RECT 9.200 358.955 9.520 359.015 ;
      RECT 9.200 359.015 11.135 359.155 ;
      RECT 11.135 358.970 11.425 359.200 ;
      RECT 9.200 359.155 9.520 359.215 ;
      RECT 13.610 358.645 14.495 358.785 ;
      RECT 14.495 358.600 14.785 358.830 ;
      RECT 12.560 358.955 12.880 359.015 ;
      RECT 12.880 359.015 13.610 359.155 ;
      RECT 12.560 359.015 12.880 359.215 ;
      RECT 13.610 358.785 13.750 359.155 ;
      RECT 7.280 360.065 7.600 360.125 ;
      RECT 7.280 360.125 10.655 360.265 ;
      RECT 10.655 360.080 10.945 360.310 ;
      RECT 7.280 360.265 7.600 360.325 ;
      RECT 7.280 361.915 7.600 362.175 ;
      RECT 8.255 362.115 8.545 362.160 ;
      RECT 11.690 361.975 12.560 362.115 ;
      RECT 12.560 361.915 12.880 362.175 ;
      RECT 9.290 361.975 9.430 362.345 ;
      RECT 8.255 361.930 8.545 362.115 ;
      RECT 8.545 361.975 9.290 362.115 ;
      RECT 9.290 362.345 11.690 362.485 ;
      RECT 11.690 362.115 11.830 362.485 ;
      RECT 12.560 363.025 12.880 363.085 ;
      RECT 12.560 363.085 13.535 363.225 ;
      RECT 13.535 363.040 13.825 363.270 ;
      RECT 12.560 363.225 12.880 363.285 ;
      RECT 18.320 363.025 18.640 363.085 ;
      RECT 18.320 363.085 18.815 363.225 ;
      RECT 18.815 363.040 19.105 363.270 ;
      RECT 18.320 363.225 18.640 363.285 ;
      RECT 5.375 363.410 5.665 363.455 ;
      RECT 5.665 363.455 6.070 363.595 ;
      RECT 5.930 362.545 6.070 363.455 ;
      RECT 5.840 362.285 6.160 362.545 ;
      RECT 5.375 363.455 5.665 363.640 ;
      RECT 13.520 363.765 13.840 363.825 ;
      RECT 15.455 363.780 15.745 363.825 ;
      RECT 16.400 363.765 16.720 363.825 ;
      RECT 15.455 363.965 15.745 364.010 ;
      RECT 13.520 363.825 16.895 363.965 ;
      RECT 16.895 363.780 17.185 364.010 ;
      RECT 13.520 363.965 13.840 364.025 ;
      RECT 16.400 363.965 16.720 364.025 ;
      RECT 1.040 364.135 1.360 364.195 ;
      RECT 1.040 364.195 4.415 364.335 ;
      RECT 4.415 364.150 4.705 364.380 ;
      RECT 1.040 364.335 1.360 364.395 ;
      RECT 8.255 366.000 8.545 366.045 ;
      RECT 8.255 366.185 8.545 366.230 ;
      RECT 8.255 366.045 8.720 366.185 ;
      RECT 8.720 365.985 9.040 366.245 ;
      RECT 13.520 366.355 13.840 366.415 ;
      RECT 13.520 366.415 15.455 366.555 ;
      RECT 15.455 366.370 15.745 366.600 ;
      RECT 13.520 366.555 13.840 366.615 ;
      RECT 13.535 367.110 13.825 367.155 ;
      RECT 13.535 367.295 13.825 367.340 ;
      RECT 13.535 367.155 14.480 367.295 ;
      RECT 14.480 367.095 14.800 367.355 ;
      RECT 3.455 370.255 3.745 370.300 ;
      RECT 11.690 370.115 12.560 370.255 ;
      RECT 12.560 370.055 12.880 370.315 ;
      RECT 4.490 370.115 4.630 370.485 ;
      RECT 3.455 370.070 3.745 370.255 ;
      RECT 3.745 370.115 4.490 370.255 ;
      RECT 4.490 370.485 11.690 370.625 ;
      RECT 11.690 370.255 11.830 370.625 ;
      RECT 15.440 370.795 15.760 371.055 ;
      RECT 8.735 371.180 9.025 371.225 ;
      RECT 14.015 371.180 14.305 371.225 ;
      RECT 8.735 371.365 9.025 371.410 ;
      RECT 14.015 371.365 14.305 371.410 ;
      RECT 8.735 371.225 16.415 371.365 ;
      RECT 16.415 371.180 16.705 371.410 ;
      RECT 27.935 350.460 28.225 350.505 ;
      RECT 27.935 350.645 28.225 350.690 ;
      RECT 27.935 350.505 28.895 350.645 ;
      RECT 28.895 350.460 29.185 350.690 ;
      RECT 22.160 374.495 22.480 374.755 ;
      RECT 23.135 330.850 23.425 330.895 ;
      RECT 23.135 331.035 23.425 331.080 ;
      RECT 23.135 330.895 23.600 331.035 ;
      RECT 23.600 330.835 23.920 331.095 ;
      RECT 27.440 374.865 27.760 375.125 ;
      RECT 22.160 343.785 22.480 343.845 ;
      RECT 22.160 343.845 23.615 343.985 ;
      RECT 23.615 343.800 23.905 344.030 ;
      RECT 22.160 343.985 22.480 344.045 ;
      RECT 25.040 358.585 25.360 358.845 ;
      RECT 21.695 376.360 21.985 376.405 ;
      RECT 21.695 376.545 21.985 376.590 ;
      RECT 21.695 376.405 25.520 376.545 ;
      RECT 25.520 376.345 25.840 376.605 ;
      RECT 27.440 378.195 27.760 378.455 ;
      RECT 30.800 378.195 31.120 378.255 ;
      RECT 30.800 378.255 32.255 378.395 ;
      RECT 32.255 378.210 32.545 378.440 ;
      RECT 30.800 378.395 31.120 378.455 ;
      RECT 37.055 343.800 37.345 343.845 ;
      RECT 37.055 343.985 37.345 344.030 ;
      RECT 37.055 343.845 39.920 343.985 ;
      RECT 39.920 343.785 40.240 344.045 ;
      RECT 37.055 333.440 37.345 333.485 ;
      RECT 37.055 333.625 37.345 333.670 ;
      RECT 37.055 333.485 39.920 333.625 ;
      RECT 39.920 333.425 40.240 333.685 ;
      RECT 25.055 347.130 25.345 347.175 ;
      RECT 25.055 347.315 25.345 347.360 ;
      RECT 25.055 347.175 27.935 347.315 ;
      RECT 27.935 347.130 28.225 347.360 ;
      RECT 32.735 360.080 33.025 360.125 ;
      RECT 38.090 359.385 38.230 360.125 ;
      RECT 33.770 359.385 38.090 359.525 ;
      RECT 33.025 360.125 33.770 360.265 ;
      RECT 32.735 360.125 33.025 360.310 ;
      RECT 33.770 359.525 33.910 360.265 ;
      RECT 38.090 360.125 39.920 360.265 ;
      RECT 39.920 360.065 40.240 360.325 ;
      RECT 26.015 331.220 26.305 331.265 ;
      RECT 26.015 331.405 26.305 331.450 ;
      RECT 26.015 331.265 27.440 331.405 ;
      RECT 27.440 331.205 27.760 331.465 ;
      RECT 25.520 379.675 25.840 379.735 ;
      RECT 25.520 379.735 27.935 379.875 ;
      RECT 27.935 379.690 28.225 379.920 ;
      RECT 25.520 379.875 25.840 379.935 ;
      RECT 24.575 361.930 24.865 361.975 ;
      RECT 24.575 362.115 24.865 362.160 ;
      RECT 24.575 361.975 25.040 362.115 ;
      RECT 25.040 361.915 25.360 362.175 ;
      RECT 22.160 380.045 22.480 380.105 ;
      RECT 24.575 380.060 24.865 380.105 ;
      RECT 27.440 380.045 27.760 380.105 ;
      RECT 24.575 380.245 24.865 380.290 ;
      RECT 22.160 380.105 29.375 380.245 ;
      RECT 29.375 380.060 29.665 380.290 ;
      RECT 22.160 380.245 22.480 380.305 ;
      RECT 27.440 380.245 27.760 380.305 ;
      RECT 24.095 380.430 24.385 380.475 ;
      RECT 24.095 380.615 24.385 380.660 ;
      RECT 24.095 380.475 25.535 380.615 ;
      RECT 25.535 380.430 25.825 380.660 ;
      RECT 28.895 380.430 29.185 380.475 ;
      RECT 28.895 380.615 29.185 380.660 ;
      RECT 28.895 380.475 30.335 380.615 ;
      RECT 30.335 380.430 30.625 380.660 ;
      RECT 37.055 350.830 37.345 350.875 ;
      RECT 37.055 351.015 37.345 351.060 ;
      RECT 37.055 350.875 39.920 351.015 ;
      RECT 39.920 350.815 40.240 351.075 ;
      RECT 33.215 382.465 33.505 382.510 ;
      RECT 38.090 382.325 38.960 382.465 ;
      RECT 38.960 382.265 39.280 382.525 ;
      RECT 34.250 382.325 34.390 382.695 ;
      RECT 33.215 382.280 33.505 382.465 ;
      RECT 33.505 382.325 34.250 382.465 ;
      RECT 34.250 382.695 38.090 382.835 ;
      RECT 38.090 382.465 38.230 382.835 ;
      RECT 27.935 334.180 28.225 334.225 ;
      RECT 27.935 334.365 28.225 334.410 ;
      RECT 27.935 334.225 28.895 334.365 ;
      RECT 28.895 334.180 29.185 334.410 ;
      RECT 22.160 334.165 22.480 334.225 ;
      RECT 22.160 334.225 22.655 334.365 ;
      RECT 22.655 334.180 22.945 334.410 ;
      RECT 22.160 334.365 22.480 334.425 ;
      RECT 25.040 383.005 25.360 383.265 ;
      RECT 23.600 334.165 23.920 334.225 ;
      RECT 23.600 334.225 25.055 334.365 ;
      RECT 25.055 334.180 25.345 334.410 ;
      RECT 23.600 334.365 23.920 334.425 ;
      RECT 24.095 353.790 24.385 353.835 ;
      RECT 24.095 353.975 24.385 354.020 ;
      RECT 24.095 353.835 25.520 353.975 ;
      RECT 25.520 353.775 25.840 354.035 ;
      RECT 27.440 363.765 27.760 363.825 ;
      RECT 27.440 363.825 29.375 363.965 ;
      RECT 29.375 363.780 29.665 364.010 ;
      RECT 27.440 363.965 27.760 364.025 ;
      RECT 26.570 363.455 27.935 363.595 ;
      RECT 27.935 363.410 28.225 363.640 ;
      RECT 24.095 364.150 24.385 364.195 ;
      RECT 24.095 364.335 24.385 364.380 ;
      RECT 24.095 364.195 26.495 364.335 ;
      RECT 26.495 364.150 26.785 364.380 ;
      RECT 26.570 363.595 26.710 364.150 ;
      RECT 28.895 364.150 29.185 364.195 ;
      RECT 28.895 364.335 29.185 364.380 ;
      RECT 28.895 364.195 30.335 364.335 ;
      RECT 30.335 364.150 30.625 364.380 ;
      RECT 37.055 353.790 37.345 353.835 ;
      RECT 37.055 353.975 37.345 354.020 ;
      RECT 37.055 353.835 38.960 353.975 ;
      RECT 38.960 353.775 39.280 354.035 ;
      RECT 32.240 364.135 32.560 364.395 ;
      RECT 27.935 330.850 28.225 330.895 ;
      RECT 27.935 331.035 28.225 331.080 ;
      RECT 27.935 330.895 28.895 331.035 ;
      RECT 28.895 330.850 29.185 331.080 ;
      RECT 22.160 366.185 22.480 366.245 ;
      RECT 26.570 366.045 27.440 366.185 ;
      RECT 27.440 365.985 27.760 366.245 ;
      RECT 23.210 366.045 23.350 366.415 ;
      RECT 22.160 365.985 22.480 366.185 ;
      RECT 22.480 366.045 23.210 366.185 ;
      RECT 23.210 366.415 26.570 366.555 ;
      RECT 26.570 366.185 26.710 366.555 ;
      RECT 23.120 341.935 23.440 341.995 ;
      RECT 23.120 341.995 25.055 342.135 ;
      RECT 25.055 341.950 25.345 342.180 ;
      RECT 23.120 342.135 23.440 342.195 ;
      RECT 32.240 366.725 32.560 366.985 ;
      RECT 22.160 347.855 22.480 347.915 ;
      RECT 22.160 347.915 23.135 348.055 ;
      RECT 23.135 347.870 23.425 348.100 ;
      RECT 22.160 348.055 22.480 348.115 ;
      RECT 27.455 368.220 27.745 368.265 ;
      RECT 38.090 367.525 38.230 368.265 ;
      RECT 33.290 367.525 38.090 367.665 ;
      RECT 28.630 367.895 33.290 368.035 ;
      RECT 33.290 367.665 33.430 368.035 ;
      RECT 27.745 368.265 28.490 368.405 ;
      RECT 27.455 368.265 27.745 368.450 ;
      RECT 28.490 367.895 28.630 368.405 ;
      RECT 38.090 368.265 38.960 368.405 ;
      RECT 38.960 368.205 39.280 368.465 ;
      RECT 36.095 347.870 36.385 347.915 ;
      RECT 36.095 348.055 36.385 348.100 ;
      RECT 36.095 347.915 38.960 348.055 ;
      RECT 38.960 347.855 39.280 348.115 ;
      RECT 27.935 355.270 28.225 355.315 ;
      RECT 27.935 355.455 28.225 355.500 ;
      RECT 27.935 355.315 28.895 355.455 ;
      RECT 28.895 355.270 29.185 355.500 ;
      RECT 25.610 341.995 26.015 342.135 ;
      RECT 26.015 341.950 26.305 342.180 ;
      RECT 21.215 342.320 21.505 342.365 ;
      RECT 24.095 342.320 24.385 342.365 ;
      RECT 21.215 342.505 21.505 342.550 ;
      RECT 24.095 342.505 24.385 342.550 ;
      RECT 21.215 342.365 25.610 342.505 ;
      RECT 25.610 342.135 25.750 342.505 ;
      RECT 27.935 342.320 28.225 342.365 ;
      RECT 27.935 342.505 28.225 342.550 ;
      RECT 27.935 342.365 28.895 342.505 ;
      RECT 28.895 342.320 29.185 342.550 ;
      RECT 25.040 371.535 25.360 371.595 ;
      RECT 25.040 371.595 26.015 371.735 ;
      RECT 26.015 371.550 26.305 371.780 ;
      RECT 25.040 371.735 25.360 371.795 ;
      RECT 30.335 371.550 30.625 371.595 ;
      RECT 30.335 371.735 30.625 371.780 ;
      RECT 30.335 371.595 30.800 371.735 ;
      RECT 30.800 371.535 31.120 371.795 ;
      RECT 37.055 371.550 37.345 371.595 ;
      RECT 37.055 371.735 37.345 371.780 ;
      RECT 37.055 371.595 39.920 371.735 ;
      RECT 39.920 371.535 40.240 371.795 ;
      RECT 23.120 350.075 23.440 350.135 ;
      RECT 23.120 350.135 25.055 350.275 ;
      RECT 25.055 350.090 25.345 350.320 ;
      RECT 23.120 350.275 23.440 350.335 ;
      RECT 22.655 356.010 22.945 356.055 ;
      RECT 23.210 355.500 23.350 356.055 ;
      RECT 23.135 355.270 23.425 355.500 ;
      RECT 22.655 356.195 22.945 356.240 ;
      RECT 22.655 356.055 26.015 356.195 ;
      RECT 26.015 356.010 26.305 356.240 ;
      RECT 25.520 350.075 25.840 350.135 ;
      RECT 25.520 350.135 26.015 350.275 ;
      RECT 26.015 350.090 26.305 350.320 ;
      RECT 25.520 350.275 25.840 350.335 ;
      RECT 25.040 374.125 25.360 374.385 ;
      RECT 23.615 333.440 23.905 333.485 ;
      RECT 23.615 333.625 23.905 333.670 ;
      RECT 23.615 333.485 26.015 333.625 ;
      RECT 26.015 333.440 26.305 333.670 ;
      RECT 34.175 374.325 34.465 374.370 ;
      RECT 38.090 374.185 39.920 374.325 ;
      RECT 39.920 374.125 40.240 374.385 ;
      RECT 35.210 374.185 35.350 374.555 ;
      RECT 34.175 374.140 34.465 374.325 ;
      RECT 34.465 374.185 35.210 374.325 ;
      RECT 35.210 374.555 38.090 374.695 ;
      RECT 38.090 374.325 38.230 374.695 ;
      RECT 13.535 249.080 13.825 249.125 ;
      RECT 18.815 249.080 19.105 249.125 ;
      RECT 13.535 249.265 13.825 249.310 ;
      RECT 18.815 249.265 19.105 249.310 ;
      RECT 13.535 249.125 21.215 249.265 ;
      RECT 21.215 249.080 21.505 249.310 ;
      RECT 20.255 252.225 20.545 252.270 ;
      RECT 21.290 252.085 21.430 252.455 ;
      RECT 20.255 252.040 20.545 252.225 ;
      RECT 20.545 252.085 21.290 252.225 ;
      RECT 21.290 252.455 24.170 252.595 ;
      RECT 24.170 252.225 24.310 252.595 ;
      RECT 26.090 252.270 26.230 252.825 ;
      RECT 24.170 252.085 26.015 252.225 ;
      RECT 26.015 252.040 26.305 252.270 ;
      RECT 26.090 252.825 28.895 252.965 ;
      RECT 28.895 252.780 29.185 253.010 ;
      RECT 13.055 257.220 13.345 257.265 ;
      RECT 18.335 257.220 18.625 257.265 ;
      RECT 13.055 257.405 13.345 257.450 ;
      RECT 18.335 257.405 18.625 257.450 ;
      RECT 13.055 257.265 20.735 257.405 ;
      RECT 20.735 257.220 21.025 257.450 ;
      RECT 8.720 256.835 9.040 256.895 ;
      RECT 9.040 256.895 12.650 257.035 ;
      RECT 8.720 256.895 9.040 257.095 ;
      RECT 12.650 256.665 12.790 257.035 ;
      RECT 21.290 256.525 21.430 257.265 ;
      RECT 12.650 256.525 21.290 256.665 ;
      RECT 21.290 257.265 22.160 257.405 ;
      RECT 22.160 257.205 22.480 257.465 ;
      RECT 25.610 260.595 26.015 260.735 ;
      RECT 26.015 260.550 26.305 260.780 ;
      RECT 19.775 260.920 20.065 260.965 ;
      RECT 23.615 260.920 23.905 260.965 ;
      RECT 19.775 261.105 20.065 261.150 ;
      RECT 23.615 261.105 23.905 261.150 ;
      RECT 19.775 260.965 25.610 261.105 ;
      RECT 25.610 260.735 25.750 261.105 ;
      RECT 17.840 266.455 18.160 266.515 ;
      RECT 22.250 266.145 22.390 266.515 ;
      RECT 18.890 266.145 22.250 266.285 ;
      RECT 22.250 266.515 23.135 266.655 ;
      RECT 23.135 266.470 23.425 266.700 ;
      RECT 18.160 266.515 18.890 266.655 ;
      RECT 17.840 266.515 18.160 266.715 ;
      RECT 18.890 266.285 19.030 266.655 ;
      RECT 9.680 272.745 10.000 272.805 ;
      RECT 9.680 272.805 23.615 272.945 ;
      RECT 23.615 272.760 23.905 272.990 ;
      RECT 9.680 272.945 10.000 273.005 ;
      RECT 27.440 273.855 27.760 273.915 ;
      RECT 18.890 273.915 27.935 274.055 ;
      RECT 27.935 273.870 28.225 274.100 ;
      RECT 14.960 274.055 15.280 274.115 ;
      RECT 27.440 274.055 27.760 274.115 ;
      RECT 16.010 273.915 16.150 274.285 ;
      RECT 14.960 273.855 15.280 274.055 ;
      RECT 15.280 273.915 16.010 274.055 ;
      RECT 16.010 274.285 18.890 274.425 ;
      RECT 18.890 274.055 19.030 274.425 ;
      RECT 9.680 276.445 10.000 276.505 ;
      RECT 9.680 276.505 11.615 276.645 ;
      RECT 11.615 276.460 11.905 276.690 ;
      RECT 9.680 276.645 10.000 276.705 ;
      RECT 26.015 276.460 26.305 276.505 ;
      RECT 26.015 276.645 26.305 276.690 ;
      RECT 26.015 276.505 27.440 276.645 ;
      RECT 27.440 276.445 27.760 276.705 ;
      RECT 13.040 278.665 13.360 278.725 ;
      RECT 22.250 278.355 22.390 278.725 ;
      RECT 14.090 278.355 22.250 278.495 ;
      RECT 22.250 278.725 23.135 278.865 ;
      RECT 23.135 278.680 23.425 278.910 ;
      RECT 13.360 278.725 14.090 278.865 ;
      RECT 13.040 278.725 13.360 278.925 ;
      RECT 14.090 278.495 14.230 278.865 ;
      RECT 20.240 284.585 20.560 284.645 ;
      RECT 20.240 284.645 22.655 284.785 ;
      RECT 22.655 284.600 22.945 284.830 ;
      RECT 20.240 284.785 20.560 284.845 ;
      RECT 7.775 293.480 8.065 293.525 ;
      RECT 8.720 293.465 9.040 293.525 ;
      RECT 17.450 293.155 17.590 293.525 ;
      RECT 11.690 293.155 17.450 293.295 ;
      RECT 7.775 293.665 8.065 293.710 ;
      RECT 8.720 293.665 9.040 293.725 ;
      RECT 7.775 293.525 11.690 293.665 ;
      RECT 11.690 293.295 11.830 293.665 ;
      RECT 17.450 293.525 21.680 293.665 ;
      RECT 21.680 293.465 22.000 293.725 ;
      RECT 18.800 294.945 19.120 295.005 ;
      RECT 18.800 295.005 22.175 295.145 ;
      RECT 22.175 294.960 22.465 295.190 ;
      RECT 18.800 295.145 19.120 295.205 ;
      RECT 14.975 296.995 15.265 297.040 ;
      RECT 22.730 296.855 23.600 296.995 ;
      RECT 23.600 296.795 23.920 297.055 ;
      RECT 16.010 296.855 16.150 297.225 ;
      RECT 14.975 296.810 15.265 296.995 ;
      RECT 15.265 296.855 16.010 296.995 ;
      RECT 16.010 297.225 22.730 297.365 ;
      RECT 22.730 296.995 22.870 297.365 ;
      RECT 18.815 307.170 19.105 307.215 ;
      RECT 22.730 306.845 22.870 307.215 ;
      RECT 19.850 306.845 22.730 306.985 ;
      RECT 23.600 307.155 23.920 307.215 ;
      RECT 19.105 307.215 19.850 307.355 ;
      RECT 18.815 307.215 19.105 307.400 ;
      RECT 19.850 306.985 19.990 307.355 ;
      RECT 22.730 307.215 26.015 307.355 ;
      RECT 26.015 307.170 26.305 307.400 ;
      RECT 23.600 307.355 23.920 307.415 ;
      RECT 19.280 311.225 19.600 311.285 ;
      RECT 19.280 311.285 22.175 311.425 ;
      RECT 22.175 311.240 22.465 311.470 ;
      RECT 19.280 311.425 19.600 311.485 ;
      RECT 29.855 314.755 30.145 314.800 ;
      RECT 19.775 314.940 20.065 314.985 ;
      RECT 24.170 314.615 24.310 314.985 ;
      RECT 20.810 314.615 24.170 314.755 ;
      RECT 24.170 314.985 26.570 315.125 ;
      RECT 26.570 314.755 26.710 315.125 ;
      RECT 20.065 314.985 20.810 315.125 ;
      RECT 19.775 314.985 20.065 315.170 ;
      RECT 20.810 314.755 20.950 315.125 ;
      RECT 30.410 314.615 30.550 314.985 ;
      RECT 26.570 314.615 30.410 314.755 ;
      RECT 29.855 314.570 30.145 314.615 ;
      RECT 31.370 314.985 31.510 315.355 ;
      RECT 30.410 314.985 31.370 315.125 ;
      RECT 31.370 315.355 35.135 315.495 ;
      RECT 35.135 315.310 35.425 315.540 ;
      RECT 13.055 318.270 13.345 318.315 ;
      RECT 18.335 318.270 18.625 318.315 ;
      RECT 13.055 318.455 13.345 318.500 ;
      RECT 18.335 318.455 18.625 318.500 ;
      RECT 13.055 318.315 20.735 318.455 ;
      RECT 20.735 318.270 21.025 318.500 ;
      RECT 8.720 317.885 9.040 317.945 ;
      RECT 9.040 317.945 12.650 318.085 ;
      RECT 8.720 317.945 9.040 318.145 ;
      RECT 12.650 317.715 12.790 318.085 ;
      RECT 18.410 317.575 18.550 317.945 ;
      RECT 12.650 317.575 18.410 317.715 ;
      RECT 21.290 317.945 21.430 318.315 ;
      RECT 18.410 317.945 21.290 318.085 ;
      RECT 21.680 318.255 22.000 318.315 ;
      RECT 21.290 318.315 22.175 318.455 ;
      RECT 22.175 318.270 22.465 318.500 ;
      RECT 21.680 318.455 22.000 318.515 ;
      RECT 15.935 325.855 16.225 325.900 ;
      RECT 20.330 325.715 20.470 326.085 ;
      RECT 15.935 325.670 16.225 325.855 ;
      RECT 16.225 325.715 20.330 325.855 ;
      RECT 25.520 326.025 25.840 326.085 ;
      RECT 20.330 326.085 26.015 326.225 ;
      RECT 26.015 326.040 26.305 326.270 ;
      RECT 25.520 326.225 25.840 326.285 ;
      RECT 20.255 225.030 20.545 225.075 ;
      RECT 20.255 225.215 20.545 225.260 ;
      RECT 20.255 225.075 25.040 225.215 ;
      RECT 25.040 225.015 25.360 225.275 ;
      RECT 13.535 228.730 13.825 228.775 ;
      RECT 18.815 228.730 19.105 228.775 ;
      RECT 13.535 228.915 13.825 228.960 ;
      RECT 18.815 228.915 19.105 228.960 ;
      RECT 13.535 228.775 21.215 228.915 ;
      RECT 21.215 228.730 21.505 228.960 ;
      RECT 17.930 232.105 18.070 232.475 ;
      RECT 9.290 232.105 17.930 232.245 ;
      RECT 17.930 232.475 22.640 232.615 ;
      RECT 22.640 232.415 22.960 232.675 ;
      RECT 8.255 232.800 8.545 232.845 ;
      RECT 8.545 232.845 9.290 232.985 ;
      RECT 8.255 232.845 8.545 233.030 ;
      RECT 9.290 232.245 9.430 232.985 ;
      RECT 19.760 233.155 20.080 233.215 ;
      RECT 19.760 233.215 22.655 233.355 ;
      RECT 22.655 233.170 22.945 233.400 ;
      RECT 19.760 233.355 20.080 233.415 ;
      RECT 30.410 233.215 33.215 233.355 ;
      RECT 33.215 233.170 33.505 233.400 ;
      RECT 18.320 233.895 18.640 233.955 ;
      RECT 24.650 233.770 24.790 233.955 ;
      RECT 20.330 233.770 24.650 233.910 ;
      RECT 26.495 233.910 26.785 233.955 ;
      RECT 27.190 233.585 30.410 233.725 ;
      RECT 30.410 233.355 30.550 233.725 ;
      RECT 26.495 234.095 26.785 234.140 ;
      RECT 24.650 233.955 27.050 234.095 ;
      RECT 27.050 233.585 27.190 234.095 ;
      RECT 18.640 233.955 20.330 234.095 ;
      RECT 20.330 233.910 20.470 234.095 ;
      RECT 18.320 233.955 18.640 234.155 ;
      RECT 10.175 236.685 10.465 236.730 ;
      RECT 18.890 236.545 25.520 236.685 ;
      RECT 25.520 236.485 25.840 236.745 ;
      RECT 14.090 236.545 14.230 236.915 ;
      RECT 10.175 236.500 10.465 236.685 ;
      RECT 10.465 236.545 14.090 236.685 ;
      RECT 14.090 236.915 18.890 237.055 ;
      RECT 18.890 236.685 19.030 237.055 ;
      RECT 16.895 240.570 17.185 240.615 ;
      RECT 16.895 240.755 17.185 240.800 ;
      RECT 16.895 240.615 39.920 240.755 ;
      RECT 39.920 240.555 40.240 240.815 ;
      RECT 18.815 242.050 19.105 242.095 ;
      RECT 23.690 241.725 23.830 242.095 ;
      RECT 19.850 241.725 23.690 241.865 ;
      RECT 19.105 242.095 19.850 242.235 ;
      RECT 18.815 242.095 19.105 242.280 ;
      RECT 19.850 241.865 19.990 242.235 ;
      RECT 23.690 242.095 25.535 242.235 ;
      RECT 25.535 242.050 25.825 242.280 ;
      RECT 21.680 290.505 22.000 290.765 ;
      RECT 24.575 290.890 24.865 290.935 ;
      RECT 24.575 291.075 24.865 291.120 ;
      RECT 24.575 290.935 26.015 291.075 ;
      RECT 26.015 290.890 26.305 291.120 ;
      RECT 23.600 292.725 23.920 292.785 ;
      RECT 23.600 292.785 26.015 292.925 ;
      RECT 26.015 292.740 26.305 292.970 ;
      RECT 23.600 292.925 23.920 292.985 ;
      RECT 37.055 292.740 37.345 292.785 ;
      RECT 37.055 292.925 37.345 292.970 ;
      RECT 37.055 292.785 38.960 292.925 ;
      RECT 38.960 292.725 39.280 292.985 ;
      RECT 25.040 293.095 25.360 293.355 ;
      RECT 27.935 293.480 28.225 293.525 ;
      RECT 27.935 293.665 28.225 293.710 ;
      RECT 27.935 293.525 28.895 293.665 ;
      RECT 28.895 293.480 29.185 293.710 ;
      RECT 25.055 276.830 25.345 276.875 ;
      RECT 25.055 277.015 25.345 277.060 ;
      RECT 25.055 276.875 25.520 277.015 ;
      RECT 25.520 276.815 25.840 277.075 ;
      RECT 27.935 278.680 28.225 278.725 ;
      RECT 27.935 278.865 28.225 278.910 ;
      RECT 27.935 278.725 28.880 278.865 ;
      RECT 28.880 278.665 29.200 278.925 ;
      RECT 30.815 278.680 31.105 278.725 ;
      RECT 38.090 278.355 38.230 278.725 ;
      RECT 31.850 278.355 38.090 278.495 ;
      RECT 31.105 278.725 31.850 278.865 ;
      RECT 30.815 278.725 31.105 278.910 ;
      RECT 31.850 278.495 31.990 278.865 ;
      RECT 38.090 278.725 38.960 278.865 ;
      RECT 38.960 278.665 39.280 278.925 ;
      RECT 27.935 298.290 28.225 298.335 ;
      RECT 27.935 298.475 28.225 298.520 ;
      RECT 27.935 298.335 28.895 298.475 ;
      RECT 28.895 298.290 29.185 298.520 ;
      RECT 25.040 298.275 25.360 298.535 ;
      RECT 24.575 299.030 24.865 299.075 ;
      RECT 24.575 299.215 24.865 299.260 ;
      RECT 24.575 299.075 26.015 299.215 ;
      RECT 26.015 299.030 26.305 299.260 ;
      RECT 23.210 298.335 23.615 298.475 ;
      RECT 23.615 298.290 23.905 298.520 ;
      RECT 23.120 299.015 23.440 299.275 ;
      RECT 23.210 298.475 23.350 299.015 ;
      RECT 37.055 299.030 37.345 299.075 ;
      RECT 37.055 299.215 37.345 299.260 ;
      RECT 37.055 299.075 38.960 299.215 ;
      RECT 38.960 299.015 39.280 299.275 ;
      RECT 23.120 300.865 23.440 300.925 ;
      RECT 23.120 300.925 26.015 301.065 ;
      RECT 26.015 300.880 26.305 301.110 ;
      RECT 23.120 301.065 23.440 301.125 ;
      RECT 21.680 301.235 22.000 301.495 ;
      RECT 25.040 301.235 25.360 301.495 ;
      RECT 27.935 301.620 28.225 301.665 ;
      RECT 27.935 301.805 28.225 301.850 ;
      RECT 27.935 301.665 28.895 301.805 ;
      RECT 28.895 301.620 29.185 301.850 ;
      RECT 37.055 303.100 37.345 303.145 ;
      RECT 37.055 303.285 37.345 303.330 ;
      RECT 37.055 303.145 39.920 303.285 ;
      RECT 39.920 303.085 40.240 303.345 ;
      RECT 27.935 306.430 28.225 306.475 ;
      RECT 27.935 306.615 28.225 306.660 ;
      RECT 27.935 306.475 28.895 306.615 ;
      RECT 28.895 306.430 29.185 306.660 ;
      RECT 25.040 306.415 25.360 306.675 ;
      RECT 37.055 306.800 37.345 306.845 ;
      RECT 37.055 306.985 37.345 307.030 ;
      RECT 37.055 306.845 39.920 306.985 ;
      RECT 39.920 306.785 40.240 307.045 ;
      RECT 21.215 281.270 21.505 281.315 ;
      RECT 21.215 281.455 21.505 281.500 ;
      RECT 21.215 281.315 38.000 281.455 ;
      RECT 38.000 281.255 38.320 281.515 ;
      RECT 28.895 309.205 29.185 309.250 ;
      RECT 39.050 309.065 39.920 309.205 ;
      RECT 39.920 309.005 40.240 309.265 ;
      RECT 29.930 309.065 30.070 309.805 ;
      RECT 28.895 309.020 29.185 309.205 ;
      RECT 29.185 309.065 29.930 309.205 ;
      RECT 29.930 309.805 34.870 309.945 ;
      RECT 34.870 309.250 39.050 309.390 ;
      RECT 39.050 309.205 39.190 309.390 ;
      RECT 34.730 309.250 34.870 309.805 ;
      RECT 23.600 309.745 23.920 309.805 ;
      RECT 23.600 309.805 25.535 309.945 ;
      RECT 25.535 309.760 25.825 309.990 ;
      RECT 23.600 309.945 23.920 310.005 ;
      RECT 35.600 309.745 35.920 310.005 ;
      RECT 27.440 281.995 27.760 282.255 ;
      RECT 26.495 311.240 26.785 311.285 ;
      RECT 30.890 310.915 31.030 311.285 ;
      RECT 27.530 310.915 30.890 311.055 ;
      RECT 26.785 311.285 27.530 311.425 ;
      RECT 26.495 311.285 26.785 311.470 ;
      RECT 27.530 311.055 27.670 311.425 ;
      RECT 30.890 311.285 31.760 311.425 ;
      RECT 31.760 311.225 32.080 311.485 ;
      RECT 33.695 313.090 33.985 313.135 ;
      RECT 33.695 313.275 33.985 313.320 ;
      RECT 33.695 313.135 35.600 313.275 ;
      RECT 35.600 313.075 35.920 313.335 ;
      RECT 25.040 314.555 25.360 314.615 ;
      RECT 29.930 313.875 30.070 314.245 ;
      RECT 27.050 313.875 29.930 314.015 ;
      RECT 30.815 314.570 31.105 314.615 ;
      RECT 30.890 314.245 31.030 314.570 ;
      RECT 29.930 314.245 30.890 314.385 ;
      RECT 26.090 314.245 27.050 314.385 ;
      RECT 27.050 314.015 27.190 314.385 ;
      RECT 25.040 314.615 26.015 314.755 ;
      RECT 26.015 314.570 26.305 314.800 ;
      RECT 26.090 314.385 26.230 314.570 ;
      RECT 30.815 314.755 31.105 314.800 ;
      RECT 30.815 314.615 34.175 314.755 ;
      RECT 34.175 314.570 34.465 314.800 ;
      RECT 25.040 314.755 25.360 314.815 ;
      RECT 28.880 314.925 29.200 315.185 ;
      RECT 31.760 314.925 32.080 315.185 ;
      RECT 26.975 315.310 27.265 315.355 ;
      RECT 26.975 315.495 27.265 315.540 ;
      RECT 26.975 315.355 29.375 315.495 ;
      RECT 29.375 315.310 29.665 315.540 ;
      RECT 28.880 281.995 29.200 282.255 ;
      RECT 37.040 315.295 37.360 315.555 ;
      RECT 28.880 317.885 29.200 318.145 ;
      RECT 37.055 282.750 37.345 282.795 ;
      RECT 37.055 282.935 37.345 282.980 ;
      RECT 37.055 282.795 39.920 282.935 ;
      RECT 39.920 282.735 40.240 282.995 ;
      RECT 35.600 277.185 35.920 277.445 ;
      RECT 37.055 319.380 37.345 319.425 ;
      RECT 37.055 319.565 37.345 319.610 ;
      RECT 37.055 319.425 38.960 319.565 ;
      RECT 38.960 319.365 39.280 319.625 ;
      RECT 21.680 322.325 22.000 322.585 ;
      RECT 25.040 322.695 25.360 322.955 ;
      RECT 37.040 322.695 37.360 322.955 ;
      RECT 25.520 323.435 25.840 323.495 ;
      RECT 25.520 323.495 26.015 323.635 ;
      RECT 26.015 323.450 26.305 323.680 ;
      RECT 25.520 323.635 25.840 323.695 ;
      RECT 27.920 323.435 28.240 323.695 ;
      RECT 28.895 323.450 29.185 323.495 ;
      RECT 36.170 322.755 36.310 323.310 ;
      RECT 29.930 322.755 36.170 322.895 ;
      RECT 39.050 323.310 39.190 323.495 ;
      RECT 36.170 323.310 39.050 323.450 ;
      RECT 29.185 323.495 29.930 323.635 ;
      RECT 28.895 323.495 29.185 323.680 ;
      RECT 29.930 322.895 30.070 323.635 ;
      RECT 39.050 323.495 39.920 323.635 ;
      RECT 39.920 323.435 40.240 323.695 ;
      RECT 24.575 284.600 24.865 284.645 ;
      RECT 24.575 284.785 24.865 284.830 ;
      RECT 24.575 284.645 27.440 284.785 ;
      RECT 27.440 284.585 27.760 284.845 ;
      RECT 27.920 326.025 28.240 326.285 ;
      RECT 26.975 327.520 27.265 327.565 ;
      RECT 26.975 327.705 27.265 327.750 ;
      RECT 26.975 327.565 27.440 327.705 ;
      RECT 27.440 327.505 27.760 327.765 ;
      RECT 36.095 327.520 36.385 327.565 ;
      RECT 36.095 327.705 36.385 327.750 ;
      RECT 36.095 327.565 39.920 327.705 ;
      RECT 39.920 327.505 40.240 327.765 ;
      RECT 25.055 327.150 25.345 327.195 ;
      RECT 29.110 326.825 35.690 326.965 ;
      RECT 35.690 326.595 35.830 326.965 ;
      RECT 26.230 327.010 28.970 327.150 ;
      RECT 28.970 326.825 29.110 327.150 ;
      RECT 25.345 327.195 26.090 327.335 ;
      RECT 25.055 327.195 25.345 327.380 ;
      RECT 26.090 327.010 26.230 327.335 ;
      RECT 39.920 328.615 40.240 328.675 ;
      RECT 40.240 328.675 40.630 328.815 ;
      RECT 39.920 328.675 40.240 328.875 ;
      RECT 40.490 326.455 40.630 328.675 ;
      RECT 35.690 326.455 40.490 326.595 ;
      RECT 37.055 329.370 37.345 329.415 ;
      RECT 37.055 329.555 37.345 329.600 ;
      RECT 37.055 329.415 38.960 329.555 ;
      RECT 38.960 329.355 39.280 329.615 ;
      RECT 37.055 284.600 37.345 284.645 ;
      RECT 37.055 284.785 37.345 284.830 ;
      RECT 37.055 284.645 39.920 284.785 ;
      RECT 39.920 284.585 40.240 284.845 ;
      RECT 21.695 284.970 21.985 285.015 ;
      RECT 21.695 285.155 21.985 285.200 ;
      RECT 21.695 285.015 25.040 285.155 ;
      RECT 25.040 284.955 25.360 285.215 ;
      RECT 27.935 285.340 28.225 285.385 ;
      RECT 27.935 285.525 28.225 285.570 ;
      RECT 27.935 285.385 28.895 285.525 ;
      RECT 28.895 285.340 29.185 285.570 ;
      RECT 25.610 285.015 26.015 285.155 ;
      RECT 26.015 284.970 26.305 285.200 ;
      RECT 21.215 285.525 21.505 285.570 ;
      RECT 22.250 285.385 22.390 285.755 ;
      RECT 21.215 285.340 21.505 285.525 ;
      RECT 21.505 285.385 22.250 285.525 ;
      RECT 22.250 285.755 25.610 285.895 ;
      RECT 25.610 285.155 25.750 285.895 ;
      RECT 37.055 288.670 37.345 288.715 ;
      RECT 37.055 288.855 37.345 288.900 ;
      RECT 37.055 288.715 39.920 288.855 ;
      RECT 39.920 288.655 40.240 288.915 ;
      RECT 27.935 290.150 28.225 290.195 ;
      RECT 27.935 290.335 28.225 290.380 ;
      RECT 27.935 290.195 28.895 290.335 ;
      RECT 28.895 290.150 29.185 290.380 ;
      RECT 23.600 290.135 23.920 290.395 ;
      RECT 25.040 290.135 25.360 290.395 ;
      RECT 7.280 292.725 7.600 292.785 ;
      RECT 7.280 292.785 10.655 292.925 ;
      RECT 10.655 292.740 10.945 292.970 ;
      RECT 7.280 292.925 7.600 292.985 ;
      RECT 18.800 300.865 19.120 301.125 ;
      RECT 8.720 276.815 9.040 277.075 ;
      RECT 19.295 300.880 19.585 300.925 ;
      RECT 19.295 300.925 19.760 301.065 ;
      RECT 19.760 300.865 20.080 301.125 ;
      RECT 14.960 301.235 15.280 301.295 ;
      RECT 15.280 301.295 19.370 301.435 ;
      RECT 14.960 301.295 15.280 301.495 ;
      RECT 19.370 301.110 19.510 301.435 ;
      RECT 19.295 301.065 19.585 301.110 ;
      RECT 13.040 281.625 13.360 281.885 ;
      RECT 19.280 317.145 19.600 317.405 ;
      RECT 18.800 293.095 19.120 293.355 ;
      RECT 12.575 289.780 12.865 289.825 ;
      RECT 17.855 289.780 18.145 289.825 ;
      RECT 12.575 289.965 12.865 290.010 ;
      RECT 17.855 289.965 18.145 290.010 ;
      RECT 12.575 289.825 20.255 289.965 ;
      RECT 20.255 289.780 20.545 290.010 ;
      RECT 12.575 301.990 12.865 302.035 ;
      RECT 17.855 301.990 18.145 302.035 ;
      RECT 12.575 302.175 12.865 302.220 ;
      RECT 17.855 302.175 18.145 302.220 ;
      RECT 12.575 302.035 20.255 302.175 ;
      RECT 20.255 301.990 20.545 302.220 ;
      RECT 14.960 318.625 15.280 318.685 ;
      RECT 14.960 318.825 15.280 318.885 ;
      RECT 14.960 318.685 19.760 318.825 ;
      RECT 19.760 318.625 20.080 318.885 ;
      RECT 7.775 319.380 8.065 319.425 ;
      RECT 12.170 319.055 12.310 319.380 ;
      RECT 8.810 319.055 12.170 319.195 ;
      RECT 17.930 319.240 18.070 319.425 ;
      RECT 12.310 319.240 17.930 319.380 ;
      RECT 8.065 319.425 8.810 319.565 ;
      RECT 7.775 319.425 8.065 319.610 ;
      RECT 8.810 319.195 8.950 319.565 ;
      RECT 17.930 319.425 18.800 319.565 ;
      RECT 18.800 319.365 19.120 319.625 ;
      RECT 7.295 303.100 7.585 303.145 ;
      RECT 11.690 302.775 11.830 303.145 ;
      RECT 8.330 302.775 11.690 302.915 ;
      RECT 7.585 303.145 8.330 303.285 ;
      RECT 7.295 303.145 7.585 303.330 ;
      RECT 8.330 302.915 8.470 303.285 ;
      RECT 11.690 303.145 13.520 303.285 ;
      RECT 13.520 303.085 13.840 303.345 ;
      RECT 19.295 321.970 19.585 322.015 ;
      RECT 19.295 322.155 19.585 322.200 ;
      RECT 19.295 322.015 19.760 322.155 ;
      RECT 19.760 321.955 20.080 322.215 ;
      RECT 12.575 322.340 12.865 322.385 ;
      RECT 17.855 322.340 18.145 322.385 ;
      RECT 12.575 322.525 12.865 322.570 ;
      RECT 17.855 322.525 18.145 322.570 ;
      RECT 12.575 322.385 20.255 322.525 ;
      RECT 20.255 322.340 20.545 322.570 ;
      RECT 11.135 276.830 11.425 276.875 ;
      RECT 13.040 276.815 13.360 276.875 ;
      RECT 11.135 277.015 11.425 277.060 ;
      RECT 13.040 277.015 13.360 277.075 ;
      RECT 11.135 276.875 18.800 277.015 ;
      RECT 18.800 276.815 19.120 277.075 ;
      RECT 18.800 322.695 19.120 322.955 ;
      RECT 13.520 306.045 13.840 306.305 ;
      RECT 10.175 277.570 10.465 277.615 ;
      RECT 12.575 277.570 12.865 277.615 ;
      RECT 10.175 277.755 10.465 277.800 ;
      RECT 12.575 277.755 12.865 277.800 ;
      RECT 10.175 277.615 17.855 277.755 ;
      RECT 17.855 277.570 18.145 277.800 ;
      RECT 7.295 323.450 7.585 323.495 ;
      RECT 7.295 323.635 7.585 323.680 ;
      RECT 7.295 323.495 10.640 323.635 ;
      RECT 10.640 323.435 10.960 323.695 ;
      RECT 9.215 293.850 9.505 293.895 ;
      RECT 11.615 293.850 11.905 293.895 ;
      RECT 9.215 294.035 9.505 294.080 ;
      RECT 11.615 294.035 11.905 294.080 ;
      RECT 9.215 293.895 16.895 294.035 ;
      RECT 16.895 293.850 17.185 294.080 ;
      RECT 11.600 306.785 11.920 307.045 ;
      RECT 11.120 282.365 11.440 282.625 ;
      RECT 8.735 325.670 9.025 325.715 ;
      RECT 8.735 325.855 9.025 325.900 ;
      RECT 8.735 325.715 9.680 325.855 ;
      RECT 9.680 325.655 10.000 325.915 ;
      RECT 16.880 326.025 17.200 326.285 ;
      RECT 17.930 290.195 18.815 290.335 ;
      RECT 18.815 290.150 19.105 290.380 ;
      RECT 13.040 290.335 13.360 290.395 ;
      RECT 14.090 290.195 14.230 290.565 ;
      RECT 13.040 290.135 13.360 290.335 ;
      RECT 13.360 290.195 14.090 290.335 ;
      RECT 14.090 290.565 17.930 290.705 ;
      RECT 17.930 290.335 18.070 290.705 ;
      RECT 10.655 309.020 10.945 309.065 ;
      RECT 10.655 309.205 10.945 309.250 ;
      RECT 10.655 309.065 13.520 309.205 ;
      RECT 13.520 309.005 13.840 309.265 ;
      RECT 10.655 326.595 10.945 326.640 ;
      RECT 17.930 326.455 18.800 326.595 ;
      RECT 18.800 326.395 19.120 326.655 ;
      RECT 15.530 326.455 15.670 326.825 ;
      RECT 10.655 326.410 10.945 326.595 ;
      RECT 10.945 326.455 15.530 326.595 ;
      RECT 15.530 326.825 17.930 326.965 ;
      RECT 17.930 326.595 18.070 326.965 ;
      RECT 7.280 297.905 7.600 297.965 ;
      RECT 7.280 297.965 9.695 298.105 ;
      RECT 9.695 297.920 9.985 298.150 ;
      RECT 7.280 298.105 7.600 298.165 ;
      RECT 17.855 297.920 18.145 297.965 ;
      RECT 17.855 298.105 18.145 298.150 ;
      RECT 17.855 297.965 18.800 298.105 ;
      RECT 18.800 297.905 19.120 298.165 ;
      RECT 18.335 282.750 18.625 282.795 ;
      RECT 18.335 282.935 18.625 282.980 ;
      RECT 18.335 282.795 20.240 282.935 ;
      RECT 20.240 282.735 20.560 282.995 ;
      RECT 16.415 329.370 16.705 329.415 ;
      RECT 16.415 329.555 16.705 329.600 ;
      RECT 16.415 329.415 16.880 329.555 ;
      RECT 16.880 329.355 17.200 329.615 ;
      RECT 9.215 310.130 9.505 310.175 ;
      RECT 11.615 310.130 11.905 310.175 ;
      RECT 9.215 310.315 9.505 310.360 ;
      RECT 11.615 310.315 11.905 310.360 ;
      RECT 9.215 310.175 16.895 310.315 ;
      RECT 16.895 310.130 17.185 310.360 ;
      RECT 7.775 310.130 8.065 310.175 ;
      RECT 7.775 310.315 8.065 310.360 ;
      RECT 7.775 310.175 8.720 310.315 ;
      RECT 8.720 310.115 9.040 310.375 ;
      RECT 10.175 310.685 10.465 310.730 ;
      RECT 14.090 310.545 14.960 310.685 ;
      RECT 14.960 310.485 15.280 310.745 ;
      RECT 11.210 310.545 11.350 310.915 ;
      RECT 10.175 310.500 10.465 310.685 ;
      RECT 10.465 310.545 11.210 310.685 ;
      RECT 11.210 310.915 14.090 311.055 ;
      RECT 14.090 310.685 14.230 311.055 ;
      RECT 20.240 285.325 20.560 285.585 ;
      RECT 7.775 298.660 8.065 298.705 ;
      RECT 11.600 298.645 11.920 298.705 ;
      RECT 15.050 298.335 15.190 298.705 ;
      RECT 12.650 298.335 15.050 298.475 ;
      RECT 7.775 298.845 8.065 298.890 ;
      RECT 15.050 298.705 15.935 298.845 ;
      RECT 15.935 298.660 16.225 298.890 ;
      RECT 11.600 298.845 11.920 298.905 ;
      RECT 7.775 298.705 12.650 298.845 ;
      RECT 12.650 298.475 12.790 298.845 ;
      RECT 7.280 290.875 7.600 291.135 ;
      RECT 14.495 314.200 14.785 314.245 ;
      RECT 14.495 314.385 14.785 314.430 ;
      RECT 14.495 314.245 19.280 314.385 ;
      RECT 19.280 314.185 19.600 314.445 ;
      RECT 18.800 290.875 19.120 290.935 ;
      RECT 18.800 290.935 19.295 291.075 ;
      RECT 19.295 290.890 19.585 291.120 ;
      RECT 18.800 291.075 19.120 291.135 ;
      RECT 9.680 314.925 10.000 314.985 ;
      RECT 11.600 314.925 11.920 314.985 ;
      RECT 9.680 314.985 12.575 315.125 ;
      RECT 12.575 314.940 12.865 315.170 ;
      RECT 9.680 315.125 10.000 315.185 ;
      RECT 11.600 315.125 11.920 315.185 ;
      RECT 10.655 273.500 10.945 273.545 ;
      RECT 13.055 273.500 13.345 273.545 ;
      RECT 10.655 273.685 10.945 273.730 ;
      RECT 13.055 273.685 13.345 273.730 ;
      RECT 10.655 273.545 18.335 273.685 ;
      RECT 18.335 273.500 18.625 273.730 ;
      RECT 12.080 273.855 12.400 274.115 ;
      RECT 13.040 252.395 13.360 252.655 ;
      RECT 8.720 274.225 9.040 274.285 ;
      RECT 8.720 274.285 9.215 274.425 ;
      RECT 9.215 274.240 9.505 274.470 ;
      RECT 8.720 274.425 9.040 274.485 ;
      RECT 11.615 274.240 11.905 274.285 ;
      RECT 11.615 274.425 11.905 274.470 ;
      RECT 11.615 274.285 13.040 274.425 ;
      RECT 13.040 274.225 13.360 274.485 ;
      RECT 12.095 244.270 12.385 244.315 ;
      RECT 12.095 244.455 12.385 244.500 ;
      RECT 12.095 244.315 13.040 244.455 ;
      RECT 13.040 244.255 13.360 244.515 ;
      RECT 8.240 253.135 8.560 253.195 ;
      RECT 14.975 253.150 15.265 253.195 ;
      RECT 14.975 253.335 15.265 253.380 ;
      RECT 8.240 253.335 8.560 253.395 ;
      RECT 8.240 253.195 19.280 253.335 ;
      RECT 19.280 253.135 19.600 253.395 ;
      RECT 14.015 245.010 14.305 245.055 ;
      RECT 14.015 245.195 14.305 245.240 ;
      RECT 14.015 245.055 19.760 245.195 ;
      RECT 19.760 244.995 20.080 245.255 ;
      RECT 17.840 243.885 18.160 243.945 ;
      RECT 17.840 243.945 19.295 244.085 ;
      RECT 19.295 243.900 19.585 244.130 ;
      RECT 17.840 244.085 18.160 244.145 ;
      RECT 19.280 257.575 19.600 257.835 ;
      RECT 11.120 257.945 11.440 258.205 ;
      RECT 7.760 258.315 8.080 258.575 ;
      RECT 12.080 260.535 12.400 260.595 ;
      RECT 12.080 260.595 12.575 260.735 ;
      RECT 12.575 260.550 12.865 260.780 ;
      RECT 12.080 260.735 12.400 260.795 ;
      RECT 19.760 249.435 20.080 249.695 ;
      RECT 7.760 261.275 8.080 261.335 ;
      RECT 7.760 261.335 14.495 261.475 ;
      RECT 14.495 261.290 14.785 261.520 ;
      RECT 7.760 261.475 8.080 261.535 ;
      RECT 10.175 265.360 10.465 265.405 ;
      RECT 12.575 265.360 12.865 265.405 ;
      RECT 10.175 265.545 10.465 265.590 ;
      RECT 12.575 265.545 12.865 265.590 ;
      RECT 10.175 265.405 17.855 265.545 ;
      RECT 17.855 265.360 18.145 265.590 ;
      RECT 7.760 265.715 8.080 265.775 ;
      RECT 7.760 265.775 11.615 265.915 ;
      RECT 11.615 265.730 11.905 265.960 ;
      RECT 7.760 265.915 8.080 265.975 ;
      RECT 8.240 224.645 8.560 224.705 ;
      RECT 14.975 224.660 15.265 224.705 ;
      RECT 14.975 224.845 15.265 224.890 ;
      RECT 8.240 224.845 8.560 224.905 ;
      RECT 8.240 224.705 19.760 224.845 ;
      RECT 19.760 224.645 20.080 224.905 ;
      RECT 8.720 266.085 9.040 266.345 ;
      RECT 13.040 225.385 13.360 225.645 ;
      RECT 19.760 227.605 20.080 227.865 ;
      RECT 11.120 266.455 11.440 266.515 ;
      RECT 11.120 266.655 11.440 266.715 ;
      RECT 11.120 266.515 13.040 266.655 ;
      RECT 13.040 266.455 13.360 266.715 ;
      RECT 19.280 229.085 19.600 229.145 ;
      RECT 19.280 229.145 20.255 229.285 ;
      RECT 20.255 229.100 20.545 229.330 ;
      RECT 19.280 229.285 19.600 229.345 ;
      RECT 8.255 229.840 8.545 229.885 ;
      RECT 8.255 230.025 8.545 230.070 ;
      RECT 8.255 229.885 11.120 230.025 ;
      RECT 11.120 229.825 11.440 230.085 ;
      RECT 11.120 249.805 11.440 249.865 ;
      RECT 11.120 249.865 11.615 250.005 ;
      RECT 11.615 249.820 11.905 250.050 ;
      RECT 11.120 250.005 11.440 250.065 ;
      RECT 9.695 232.800 9.985 232.845 ;
      RECT 12.095 232.800 12.385 232.845 ;
      RECT 9.695 232.985 9.985 233.030 ;
      RECT 12.095 232.985 12.385 233.030 ;
      RECT 9.695 232.845 17.375 232.985 ;
      RECT 17.375 232.800 17.665 233.030 ;
      RECT 11.120 233.155 11.440 233.415 ;
      RECT 7.775 268.690 8.065 268.735 ;
      RECT 12.080 268.675 12.400 268.735 ;
      RECT 7.775 268.875 8.065 268.920 ;
      RECT 7.775 268.735 15.935 268.875 ;
      RECT 15.935 268.690 16.225 268.920 ;
      RECT 12.080 268.875 12.400 268.935 ;
      RECT 19.280 233.525 19.600 233.785 ;
      RECT 10.640 233.895 10.960 234.155 ;
      RECT 9.680 269.415 10.000 269.675 ;
      RECT 9.215 235.760 9.505 235.805 ;
      RECT 9.215 235.945 9.505 235.990 ;
      RECT 9.215 235.805 17.840 235.945 ;
      RECT 17.840 235.745 18.160 236.005 ;
      RECT 18.320 235.745 18.640 236.005 ;
      RECT 11.135 236.130 11.425 236.175 ;
      RECT 11.135 236.315 11.425 236.360 ;
      RECT 11.135 236.175 13.040 236.315 ;
      RECT 13.040 236.115 13.360 236.375 ;
      RECT 12.080 269.415 12.400 269.475 ;
      RECT 12.080 269.615 12.400 269.675 ;
      RECT 12.080 269.475 17.840 269.615 ;
      RECT 17.840 269.415 18.160 269.675 ;
      RECT 11.120 236.855 11.440 236.915 ;
      RECT 11.120 236.915 13.055 237.055 ;
      RECT 13.055 236.870 13.345 237.100 ;
      RECT 11.120 237.055 11.440 237.115 ;
      RECT 7.295 237.980 7.585 238.025 ;
      RECT 7.295 238.165 7.585 238.210 ;
      RECT 7.295 238.025 8.720 238.165 ;
      RECT 8.720 237.965 9.040 238.225 ;
      RECT 14.960 270.525 15.280 270.785 ;
      RECT 8.720 241.295 9.040 241.555 ;
      RECT 17.840 241.295 18.160 241.555 ;
      RECT 8.240 250.175 8.560 250.435 ;
      RECT 37.055 258.330 37.345 258.375 ;
      RECT 37.055 258.515 37.345 258.560 ;
      RECT 37.055 258.375 38.960 258.515 ;
      RECT 38.960 258.315 39.280 258.575 ;
      RECT 23.600 260.165 23.920 260.225 ;
      RECT 23.600 260.225 24.575 260.365 ;
      RECT 24.575 260.180 24.865 260.410 ;
      RECT 23.600 260.365 23.920 260.425 ;
      RECT 35.135 243.900 35.425 243.945 ;
      RECT 35.135 244.085 35.425 244.130 ;
      RECT 35.135 243.945 38.960 244.085 ;
      RECT 38.960 243.885 39.280 244.145 ;
      RECT 25.040 260.535 25.360 260.795 ;
      RECT 34.160 249.435 34.480 249.695 ;
      RECT 30.335 223.735 30.625 223.780 ;
      RECT 38.090 223.595 39.920 223.735 ;
      RECT 39.920 223.535 40.240 223.795 ;
      RECT 31.370 223.595 31.510 223.965 ;
      RECT 30.335 223.550 30.625 223.735 ;
      RECT 30.625 223.595 31.370 223.735 ;
      RECT 31.370 223.965 38.090 224.105 ;
      RECT 38.090 223.735 38.230 224.105 ;
      RECT 27.935 260.920 28.225 260.965 ;
      RECT 27.935 261.105 28.225 261.150 ;
      RECT 27.935 260.965 28.895 261.105 ;
      RECT 28.895 260.920 29.185 261.150 ;
      RECT 25.520 274.225 25.840 274.285 ;
      RECT 25.520 274.285 31.775 274.425 ;
      RECT 31.775 274.240 32.065 274.470 ;
      RECT 25.520 274.425 25.840 274.485 ;
      RECT 35.120 225.015 35.440 225.275 ;
      RECT 28.895 274.610 29.185 274.655 ;
      RECT 28.895 274.795 29.185 274.840 ;
      RECT 28.895 274.655 32.735 274.795 ;
      RECT 32.735 274.610 33.025 274.840 ;
      RECT 26.015 225.770 26.305 225.815 ;
      RECT 30.410 225.445 30.550 225.815 ;
      RECT 27.050 225.445 30.410 225.585 ;
      RECT 26.305 225.815 27.050 225.955 ;
      RECT 26.015 225.815 26.305 226.000 ;
      RECT 27.050 225.585 27.190 225.955 ;
      RECT 30.410 225.815 31.280 225.955 ;
      RECT 31.280 225.755 31.600 226.015 ;
      RECT 34.655 274.610 34.945 274.655 ;
      RECT 34.655 274.795 34.945 274.840 ;
      RECT 34.655 274.655 35.600 274.795 ;
      RECT 35.600 274.595 35.920 274.855 ;
      RECT 31.280 227.605 31.600 227.865 ;
      RECT 33.215 227.620 33.505 227.665 ;
      RECT 33.215 227.805 33.505 227.850 ;
      RECT 33.215 227.665 35.120 227.805 ;
      RECT 35.120 227.605 35.440 227.865 ;
      RECT 22.640 227.975 22.960 228.235 ;
      RECT 23.600 228.345 23.920 228.405 ;
      RECT 29.840 228.345 30.160 228.405 ;
      RECT 23.600 228.405 30.335 228.545 ;
      RECT 30.335 228.360 30.625 228.590 ;
      RECT 23.600 228.545 23.920 228.605 ;
      RECT 29.840 228.545 30.160 228.605 ;
      RECT 29.375 248.155 29.665 248.200 ;
      RECT 38.090 248.015 39.920 248.155 ;
      RECT 39.920 247.955 40.240 248.215 ;
      RECT 30.410 248.015 30.550 248.385 ;
      RECT 29.375 247.970 29.665 248.155 ;
      RECT 29.665 248.015 30.410 248.155 ;
      RECT 30.410 248.385 38.090 248.525 ;
      RECT 38.090 248.155 38.230 248.525 ;
      RECT 37.055 262.400 37.345 262.445 ;
      RECT 37.055 262.585 37.345 262.630 ;
      RECT 37.055 262.445 39.920 262.585 ;
      RECT 39.920 262.385 40.240 262.645 ;
      RECT 37.055 264.250 37.345 264.295 ;
      RECT 37.055 264.435 37.345 264.480 ;
      RECT 37.055 264.295 39.920 264.435 ;
      RECT 39.920 264.235 40.240 264.495 ;
      RECT 29.450 252.825 30.335 252.965 ;
      RECT 30.335 252.780 30.625 253.010 ;
      RECT 25.130 253.025 25.270 253.335 ;
      RECT 25.040 252.765 25.360 253.025 ;
      RECT 26.090 253.195 26.230 253.565 ;
      RECT 25.270 253.195 26.090 253.335 ;
      RECT 26.090 253.565 29.450 253.705 ;
      RECT 29.450 252.965 29.590 253.705 ;
      RECT 27.935 265.730 28.225 265.775 ;
      RECT 27.935 265.915 28.225 265.960 ;
      RECT 27.935 265.775 28.895 265.915 ;
      RECT 28.895 265.730 29.185 265.960 ;
      RECT 22.160 249.805 22.480 249.865 ;
      RECT 22.160 249.865 22.655 250.005 ;
      RECT 22.655 249.820 22.945 250.050 ;
      RECT 22.160 250.005 22.480 250.065 ;
      RECT 25.040 265.715 25.360 265.975 ;
      RECT 27.920 244.625 28.240 244.885 ;
      RECT 28.970 232.845 29.110 233.215 ;
      RECT 26.570 232.845 28.970 232.985 ;
      RECT 28.970 233.215 29.840 233.355 ;
      RECT 29.840 233.155 30.160 233.415 ;
      RECT 25.750 233.215 26.570 233.355 ;
      RECT 26.570 232.985 26.710 233.355 ;
      RECT 25.520 233.525 25.840 233.785 ;
      RECT 25.610 233.215 25.750 233.525 ;
      RECT 32.720 233.525 33.040 233.785 ;
      RECT 30.815 233.910 31.105 233.955 ;
      RECT 30.815 234.095 31.105 234.140 ;
      RECT 30.815 233.955 34.175 234.095 ;
      RECT 34.175 233.910 34.465 234.140 ;
      RECT 27.935 257.590 28.225 257.635 ;
      RECT 27.935 257.775 28.225 257.820 ;
      RECT 27.935 257.635 28.895 257.775 ;
      RECT 28.895 257.590 29.185 257.820 ;
      RECT 29.855 252.040 30.145 252.085 ;
      RECT 29.855 252.225 30.145 252.270 ;
      RECT 29.855 252.085 31.295 252.225 ;
      RECT 31.295 252.040 31.585 252.270 ;
      RECT 27.440 233.895 27.760 233.955 ;
      RECT 27.440 233.955 28.415 234.095 ;
      RECT 28.415 233.910 28.705 234.140 ;
      RECT 27.440 234.095 27.760 234.155 ;
      RECT 25.040 266.455 25.360 266.515 ;
      RECT 25.040 266.515 26.015 266.655 ;
      RECT 26.015 266.470 26.305 266.700 ;
      RECT 25.040 266.655 25.360 266.715 ;
      RECT 37.055 268.320 37.345 268.365 ;
      RECT 37.055 268.505 37.345 268.550 ;
      RECT 37.055 268.365 38.960 268.505 ;
      RECT 38.960 268.305 39.280 268.565 ;
      RECT 25.040 257.575 25.360 257.835 ;
      RECT 27.440 236.485 27.760 236.745 ;
      RECT 32.720 236.485 33.040 236.545 ;
      RECT 32.720 236.545 35.615 236.685 ;
      RECT 35.615 236.500 35.905 236.730 ;
      RECT 32.720 236.685 33.040 236.745 ;
      RECT 25.055 268.690 25.345 268.735 ;
      RECT 25.055 268.875 25.345 268.920 ;
      RECT 25.055 268.735 25.520 268.875 ;
      RECT 25.520 268.675 25.840 268.935 ;
      RECT 23.135 268.320 23.425 268.365 ;
      RECT 23.135 268.505 23.425 268.550 ;
      RECT 23.135 268.365 26.015 268.505 ;
      RECT 26.015 268.320 26.305 268.550 ;
      RECT 23.615 269.060 23.905 269.290 ;
      RECT 23.690 268.505 23.830 269.060 ;
      RECT 21.215 237.240 21.505 237.285 ;
      RECT 39.050 236.915 39.190 237.285 ;
      RECT 36.650 236.915 39.050 237.055 ;
      RECT 21.505 237.285 36.650 237.425 ;
      RECT 21.215 237.285 21.505 237.470 ;
      RECT 36.650 237.055 36.790 237.425 ;
      RECT 39.050 237.285 39.920 237.425 ;
      RECT 39.920 237.225 40.240 237.485 ;
      RECT 27.935 269.060 28.225 269.105 ;
      RECT 27.935 269.245 28.225 269.290 ;
      RECT 27.935 269.105 28.895 269.245 ;
      RECT 28.895 269.060 29.185 269.290 ;
      RECT 30.815 237.980 31.105 238.025 ;
      RECT 38.090 237.840 38.230 238.025 ;
      RECT 31.850 237.840 38.090 237.980 ;
      RECT 31.105 238.025 31.850 238.165 ;
      RECT 30.815 238.025 31.105 238.210 ;
      RECT 31.850 237.980 31.990 238.165 ;
      RECT 38.090 238.025 38.960 238.165 ;
      RECT 38.960 237.965 39.280 238.225 ;
      RECT 27.920 252.025 28.240 252.285 ;
      RECT 27.455 241.310 27.745 241.355 ;
      RECT 27.455 241.495 27.745 241.540 ;
      RECT 27.455 241.355 28.415 241.495 ;
      RECT 28.415 241.310 28.705 241.540 ;
      RECT 33.215 252.040 33.505 252.085 ;
      RECT 33.215 252.225 33.505 252.270 ;
      RECT 33.215 252.085 34.160 252.225 ;
      RECT 34.160 252.025 34.480 252.285 ;
      RECT 24.575 269.430 24.865 269.475 ;
      RECT 24.575 269.615 24.865 269.660 ;
      RECT 24.575 269.475 25.040 269.615 ;
      RECT 25.040 269.415 25.360 269.675 ;
      RECT 24.575 241.310 24.865 241.355 ;
      RECT 24.575 241.495 24.865 241.540 ;
      RECT 24.575 241.355 25.520 241.495 ;
      RECT 25.520 241.295 25.840 241.555 ;
      RECT 36.575 241.310 36.865 241.355 ;
      RECT 36.575 241.495 36.865 241.540 ;
      RECT 36.575 241.355 39.920 241.495 ;
      RECT 39.920 241.295 40.240 241.555 ;
      RECT 23.600 258.315 23.920 258.375 ;
      RECT 23.600 258.375 26.015 258.515 ;
      RECT 26.015 258.330 26.305 258.560 ;
      RECT 23.600 258.515 23.920 258.575 ;
      RECT 20.240 119.935 20.560 119.995 ;
      RECT 20.240 119.995 23.135 120.135 ;
      RECT 23.135 119.950 23.425 120.180 ;
      RECT 20.240 120.135 20.560 120.195 ;
      RECT 19.775 121.800 20.065 121.845 ;
      RECT 19.775 121.985 20.065 122.030 ;
      RECT 24.170 122.030 24.310 122.585 ;
      RECT 19.775 121.845 24.095 121.985 ;
      RECT 24.095 121.800 24.385 122.030 ;
      RECT 24.170 122.585 26.495 122.725 ;
      RECT 26.495 122.540 26.785 122.770 ;
      RECT 14.015 126.980 14.305 127.025 ;
      RECT 19.295 126.980 19.585 127.025 ;
      RECT 14.015 127.165 14.305 127.210 ;
      RECT 19.295 127.165 19.585 127.210 ;
      RECT 14.015 127.025 21.695 127.165 ;
      RECT 21.695 126.980 21.985 127.210 ;
      RECT 9.680 127.335 10.000 127.395 ;
      RECT 10.000 127.395 10.730 127.535 ;
      RECT 9.680 127.395 10.000 127.595 ;
      RECT 10.730 127.165 10.870 127.535 ;
      RECT 13.130 127.025 13.270 127.535 ;
      RECT 10.730 127.025 13.130 127.165 ;
      RECT 14.090 127.395 14.230 127.720 ;
      RECT 13.270 127.395 14.090 127.535 ;
      RECT 18.890 127.580 19.030 127.765 ;
      RECT 14.230 127.580 18.890 127.720 ;
      RECT 22.640 127.705 22.960 127.765 ;
      RECT 18.890 127.765 23.135 127.905 ;
      RECT 23.135 127.720 23.425 127.950 ;
      RECT 22.640 127.905 22.960 127.965 ;
      RECT 20.735 129.940 21.025 129.985 ;
      RECT 20.735 130.125 21.025 130.170 ;
      RECT 24.575 130.125 24.865 130.170 ;
      RECT 26.975 130.680 27.265 130.910 ;
      RECT 27.050 129.985 27.190 130.680 ;
      RECT 20.735 129.985 27.050 130.125 ;
      RECT 24.575 129.940 24.865 129.985 ;
      RECT 15.440 136.215 15.760 136.275 ;
      RECT 22.730 135.905 22.870 136.275 ;
      RECT 16.490 135.905 22.730 136.045 ;
      RECT 22.730 136.275 24.095 136.415 ;
      RECT 24.095 136.230 24.385 136.460 ;
      RECT 15.760 136.275 16.490 136.415 ;
      RECT 15.440 136.275 15.760 136.475 ;
      RECT 16.490 136.045 16.630 136.415 ;
      RECT 20.735 138.820 21.025 138.865 ;
      RECT 25.520 138.805 25.840 138.865 ;
      RECT 20.735 139.005 21.025 139.050 ;
      RECT 20.735 138.865 26.975 139.005 ;
      RECT 26.975 138.820 27.265 139.050 ;
      RECT 25.520 139.005 25.840 139.065 ;
      RECT 14.495 143.260 14.785 143.305 ;
      RECT 19.775 143.260 20.065 143.305 ;
      RECT 14.495 143.445 14.785 143.490 ;
      RECT 19.775 143.445 20.065 143.490 ;
      RECT 14.495 143.305 22.175 143.445 ;
      RECT 22.175 143.260 22.465 143.490 ;
      RECT 9.680 142.875 10.000 142.935 ;
      RECT 10.000 142.935 14.090 143.075 ;
      RECT 9.680 142.935 10.000 143.135 ;
      RECT 14.090 142.705 14.230 143.075 ;
      RECT 22.730 142.565 22.870 143.305 ;
      RECT 14.090 142.565 22.730 142.705 ;
      RECT 22.730 143.305 23.615 143.445 ;
      RECT 23.615 143.260 23.905 143.490 ;
      RECT 19.850 143.675 20.735 143.815 ;
      RECT 20.735 143.630 21.025 143.860 ;
      RECT 15.440 143.815 15.760 143.875 ;
      RECT 16.490 143.675 16.630 144.045 ;
      RECT 15.440 143.615 15.760 143.815 ;
      RECT 15.760 143.675 16.490 143.815 ;
      RECT 16.490 144.045 19.850 144.185 ;
      RECT 19.850 143.815 19.990 144.185 ;
      RECT 25.610 146.635 26.015 146.775 ;
      RECT 26.015 146.590 26.305 146.820 ;
      RECT 18.815 146.960 19.105 147.005 ;
      RECT 23.135 146.960 23.425 147.005 ;
      RECT 18.815 147.145 19.105 147.190 ;
      RECT 23.135 147.145 23.425 147.190 ;
      RECT 18.815 147.005 25.610 147.145 ;
      RECT 25.610 146.775 25.750 147.145 ;
      RECT 18.335 152.510 18.625 152.555 ;
      RECT 22.160 152.495 22.480 152.555 ;
      RECT 18.335 152.695 18.625 152.740 ;
      RECT 18.335 152.555 22.655 152.695 ;
      RECT 22.655 152.510 22.945 152.740 ;
      RECT 22.160 152.695 22.480 152.755 ;
      RECT 18.800 154.345 19.120 154.405 ;
      RECT 17.930 154.405 21.695 154.545 ;
      RECT 21.695 154.360 21.985 154.590 ;
      RECT 13.040 154.545 13.360 154.605 ;
      RECT 18.800 154.545 19.120 154.605 ;
      RECT 14.090 154.405 14.230 154.775 ;
      RECT 13.040 154.345 13.360 154.545 ;
      RECT 13.360 154.405 14.090 154.545 ;
      RECT 14.090 154.775 17.930 154.915 ;
      RECT 17.930 154.545 18.070 154.915 ;
      RECT 13.055 159.540 13.345 159.585 ;
      RECT 18.335 159.540 18.625 159.585 ;
      RECT 13.055 159.725 13.345 159.770 ;
      RECT 18.335 159.725 18.625 159.770 ;
      RECT 13.055 159.585 20.735 159.725 ;
      RECT 20.735 159.540 21.025 159.770 ;
      RECT 8.720 159.155 9.040 159.215 ;
      RECT 9.040 159.215 12.650 159.355 ;
      RECT 8.720 159.215 9.040 159.415 ;
      RECT 12.650 158.985 12.790 159.355 ;
      RECT 21.290 158.845 21.430 159.585 ;
      RECT 12.650 158.845 21.290 158.985 ;
      RECT 21.290 159.585 22.175 159.725 ;
      RECT 22.175 159.540 22.465 159.770 ;
      RECT 19.775 163.240 20.065 163.285 ;
      RECT 22.655 163.240 22.945 163.285 ;
      RECT 19.775 163.425 20.065 163.470 ;
      RECT 22.655 163.425 22.945 163.470 ;
      RECT 19.775 163.285 25.520 163.425 ;
      RECT 25.520 163.225 25.840 163.485 ;
      RECT 19.280 168.775 19.600 168.835 ;
      RECT 19.280 168.835 23.135 168.975 ;
      RECT 23.135 168.790 23.425 169.020 ;
      RECT 19.280 168.975 19.600 169.035 ;
      RECT 19.775 171.380 20.065 171.425 ;
      RECT 23.615 171.380 23.905 171.425 ;
      RECT 19.775 171.565 20.065 171.610 ;
      RECT 23.615 171.565 23.905 171.610 ;
      RECT 19.775 171.425 26.090 171.565 ;
      RECT 26.090 171.240 26.230 171.565 ;
      RECT 26.015 171.010 26.305 171.240 ;
      RECT 13.535 175.820 13.825 175.865 ;
      RECT 18.815 175.820 19.105 175.865 ;
      RECT 13.535 176.005 13.825 176.050 ;
      RECT 18.815 176.005 19.105 176.050 ;
      RECT 13.535 175.865 21.215 176.005 ;
      RECT 21.215 175.820 21.505 176.050 ;
      RECT 8.720 175.435 9.040 175.495 ;
      RECT 9.040 175.495 13.130 175.635 ;
      RECT 8.720 175.495 9.040 175.695 ;
      RECT 13.130 175.265 13.270 175.635 ;
      RECT 21.770 175.125 21.910 175.865 ;
      RECT 13.130 175.125 21.770 175.265 ;
      RECT 21.770 175.865 22.655 176.005 ;
      RECT 22.655 175.820 22.945 176.050 ;
      RECT 25.610 179.195 26.015 179.335 ;
      RECT 26.015 179.150 26.305 179.380 ;
      RECT 19.295 179.520 19.585 179.565 ;
      RECT 22.655 179.520 22.945 179.565 ;
      RECT 19.295 179.705 19.585 179.750 ;
      RECT 22.655 179.705 22.945 179.750 ;
      RECT 19.295 179.565 25.610 179.705 ;
      RECT 25.610 179.335 25.750 179.705 ;
      RECT 14.960 185.055 15.280 185.115 ;
      RECT 19.370 184.745 19.510 185.115 ;
      RECT 16.010 184.745 19.370 184.885 ;
      RECT 19.370 185.115 23.615 185.255 ;
      RECT 23.615 185.070 23.905 185.300 ;
      RECT 15.280 185.115 16.010 185.255 ;
      RECT 14.960 185.115 15.280 185.315 ;
      RECT 16.010 184.885 16.150 185.255 ;
      RECT 20.255 187.660 20.545 187.705 ;
      RECT 23.615 187.660 23.905 187.705 ;
      RECT 20.255 187.845 20.545 187.890 ;
      RECT 23.615 187.845 23.905 187.890 ;
      RECT 20.255 187.705 25.520 187.845 ;
      RECT 25.520 187.645 25.840 187.905 ;
      RECT 14.015 192.100 14.305 192.145 ;
      RECT 19.295 192.100 19.585 192.145 ;
      RECT 14.015 192.285 14.305 192.330 ;
      RECT 19.295 192.285 19.585 192.330 ;
      RECT 14.015 192.145 21.695 192.285 ;
      RECT 21.695 192.100 21.985 192.330 ;
      RECT 9.200 191.715 9.520 191.775 ;
      RECT 9.520 191.775 13.610 191.915 ;
      RECT 9.200 191.775 9.520 191.975 ;
      RECT 13.610 191.545 13.750 191.915 ;
      RECT 22.250 191.405 22.390 192.145 ;
      RECT 13.610 191.405 22.250 191.545 ;
      RECT 22.250 192.145 23.135 192.285 ;
      RECT 23.135 192.100 23.425 192.330 ;
      RECT 20.240 193.195 20.560 193.255 ;
      RECT 20.240 193.255 20.735 193.395 ;
      RECT 20.735 193.210 21.025 193.440 ;
      RECT 20.240 193.395 20.560 193.455 ;
      RECT 25.610 195.475 26.015 195.615 ;
      RECT 26.015 195.430 26.305 195.660 ;
      RECT 19.295 195.800 19.585 195.845 ;
      RECT 19.295 195.985 19.585 196.030 ;
      RECT 22.175 195.985 22.465 196.030 ;
      RECT 23.210 195.845 23.350 196.215 ;
      RECT 19.295 195.845 23.210 195.985 ;
      RECT 22.175 195.800 22.465 195.845 ;
      RECT 23.210 196.215 25.610 196.355 ;
      RECT 25.610 195.615 25.750 196.355 ;
      RECT 18.890 200.655 23.615 200.795 ;
      RECT 23.615 200.610 23.905 200.840 ;
      RECT 14.960 200.795 15.280 200.855 ;
      RECT 16.010 200.655 16.150 201.025 ;
      RECT 14.960 200.595 15.280 200.795 ;
      RECT 15.280 200.655 16.010 200.795 ;
      RECT 16.010 201.025 18.890 201.165 ;
      RECT 18.890 200.795 19.030 201.165 ;
      RECT 20.255 203.200 20.545 203.245 ;
      RECT 23.600 203.185 23.920 203.245 ;
      RECT 20.255 203.385 20.545 203.430 ;
      RECT 20.255 203.245 25.055 203.385 ;
      RECT 25.055 203.200 25.345 203.430 ;
      RECT 23.600 203.385 23.920 203.445 ;
      RECT 15.440 209.475 15.760 209.535 ;
      RECT 18.890 209.165 19.030 209.535 ;
      RECT 16.490 209.165 18.890 209.305 ;
      RECT 18.890 209.535 23.135 209.675 ;
      RECT 23.135 209.490 23.425 209.720 ;
      RECT 15.760 209.535 16.490 209.675 ;
      RECT 15.440 209.535 15.760 209.735 ;
      RECT 16.490 209.305 16.630 209.675 ;
      RECT 25.610 211.755 26.015 211.895 ;
      RECT 26.015 211.710 26.305 211.940 ;
      RECT 20.735 212.080 21.025 212.125 ;
      RECT 23.615 212.080 23.905 212.125 ;
      RECT 20.735 212.265 21.025 212.310 ;
      RECT 23.615 212.265 23.905 212.310 ;
      RECT 20.735 212.125 25.610 212.265 ;
      RECT 25.610 211.895 25.750 212.265 ;
      RECT 20.810 215.455 21.695 215.595 ;
      RECT 21.695 215.410 21.985 215.640 ;
      RECT 10.640 215.595 10.960 215.655 ;
      RECT 11.690 215.455 11.830 215.825 ;
      RECT 10.640 215.395 10.960 215.595 ;
      RECT 10.960 215.455 11.690 215.595 ;
      RECT 11.690 215.825 20.810 215.965 ;
      RECT 20.810 215.595 20.950 215.965 ;
      RECT 13.535 220.590 13.825 220.635 ;
      RECT 18.815 220.590 19.105 220.635 ;
      RECT 13.535 220.775 13.825 220.820 ;
      RECT 18.815 220.775 19.105 220.820 ;
      RECT 13.535 220.635 21.215 220.775 ;
      RECT 21.215 220.590 21.505 220.820 ;
      RECT 7.280 220.205 7.600 220.265 ;
      RECT 7.600 220.265 13.130 220.405 ;
      RECT 13.130 220.220 13.270 220.405 ;
      RECT 7.280 220.265 7.600 220.465 ;
      RECT 21.770 220.265 21.910 220.635 ;
      RECT 20.810 220.080 20.950 220.405 ;
      RECT 20.950 220.265 21.770 220.405 ;
      RECT 13.130 220.080 20.810 220.220 ;
      RECT 21.770 220.635 22.640 220.775 ;
      RECT 22.640 220.575 22.960 220.835 ;
      RECT 27.440 171.365 27.760 171.425 ;
      RECT 27.440 171.425 28.895 171.565 ;
      RECT 28.895 171.380 29.185 171.610 ;
      RECT 27.440 171.565 27.760 171.625 ;
      RECT 24.575 186.920 24.865 186.965 ;
      RECT 24.575 187.105 24.865 187.150 ;
      RECT 24.575 186.965 26.015 187.105 ;
      RECT 26.015 186.920 26.305 187.150 ;
      RECT 23.120 187.275 23.440 187.335 ;
      RECT 23.120 187.335 25.055 187.475 ;
      RECT 25.055 187.290 25.345 187.520 ;
      RECT 23.120 187.475 23.440 187.535 ;
      RECT 27.935 187.660 28.225 187.705 ;
      RECT 27.935 187.845 28.225 187.890 ;
      RECT 27.935 187.705 28.895 187.845 ;
      RECT 28.895 187.660 29.185 187.890 ;
      RECT 37.055 172.860 37.345 172.905 ;
      RECT 37.055 173.045 37.345 173.090 ;
      RECT 37.055 172.905 38.960 173.045 ;
      RECT 38.960 172.845 39.280 173.105 ;
      RECT 37.055 189.140 37.345 189.185 ;
      RECT 37.055 189.325 37.345 189.370 ;
      RECT 37.055 189.185 38.960 189.325 ;
      RECT 38.960 189.125 39.280 189.385 ;
      RECT 27.935 170.640 28.225 170.685 ;
      RECT 27.935 170.825 28.225 170.870 ;
      RECT 27.935 170.685 28.400 170.825 ;
      RECT 28.400 170.625 28.720 170.885 ;
      RECT 23.120 170.995 23.440 171.055 ;
      RECT 23.120 171.055 25.055 171.195 ;
      RECT 25.055 171.010 25.345 171.240 ;
      RECT 23.120 171.195 23.440 171.255 ;
      RECT 27.935 192.470 28.225 192.515 ;
      RECT 27.935 192.655 28.225 192.700 ;
      RECT 27.935 192.515 28.895 192.655 ;
      RECT 28.895 192.470 29.185 192.700 ;
      RECT 23.120 192.825 23.440 192.885 ;
      RECT 23.120 192.885 25.055 193.025 ;
      RECT 25.055 192.840 25.345 193.070 ;
      RECT 23.120 193.025 23.440 193.085 ;
      RECT 25.520 192.825 25.840 192.885 ;
      RECT 25.520 192.885 26.015 193.025 ;
      RECT 26.015 192.840 26.305 193.070 ;
      RECT 25.520 193.025 25.840 193.085 ;
      RECT 26.975 176.190 27.265 176.235 ;
      RECT 26.975 176.375 27.265 176.420 ;
      RECT 26.975 176.235 27.935 176.375 ;
      RECT 27.935 176.190 28.225 176.420 ;
      RECT 37.055 193.210 37.345 193.255 ;
      RECT 37.055 193.395 37.345 193.440 ;
      RECT 37.055 193.255 39.920 193.395 ;
      RECT 39.920 193.195 40.240 193.455 ;
      RECT 23.120 195.415 23.440 195.475 ;
      RECT 23.120 195.615 23.440 195.675 ;
      RECT 23.120 195.475 25.040 195.615 ;
      RECT 25.040 195.415 25.360 195.675 ;
      RECT 27.935 195.800 28.225 195.845 ;
      RECT 27.935 195.985 28.225 196.030 ;
      RECT 27.935 195.845 28.895 195.985 ;
      RECT 28.895 195.800 29.185 196.030 ;
      RECT 23.120 176.545 23.440 176.605 ;
      RECT 23.120 176.605 24.095 176.745 ;
      RECT 24.095 176.560 24.385 176.790 ;
      RECT 23.120 176.745 23.440 176.805 ;
      RECT 23.120 197.265 23.440 197.525 ;
      RECT 37.055 197.280 37.345 197.325 ;
      RECT 37.055 197.465 37.345 197.510 ;
      RECT 37.055 197.325 39.920 197.465 ;
      RECT 39.920 197.265 40.240 197.525 ;
      RECT 38.480 198.375 38.800 198.435 ;
      RECT 38.480 198.575 38.800 198.635 ;
      RECT 38.480 198.435 39.920 198.575 ;
      RECT 39.920 198.375 40.240 198.635 ;
      RECT 37.055 199.130 37.345 199.175 ;
      RECT 37.055 199.315 37.345 199.360 ;
      RECT 37.055 199.175 38.960 199.315 ;
      RECT 38.960 199.115 39.280 199.375 ;
      RECT 27.935 200.610 28.225 200.655 ;
      RECT 27.935 200.795 28.225 200.840 ;
      RECT 27.935 200.655 28.895 200.795 ;
      RECT 28.895 200.610 29.185 200.840 ;
      RECT 23.600 176.915 23.920 176.975 ;
      RECT 23.600 176.975 25.055 177.115 ;
      RECT 25.055 176.930 25.345 177.160 ;
      RECT 23.600 177.115 23.920 177.175 ;
      RECT 25.040 200.965 25.360 201.225 ;
      RECT 23.120 201.335 23.440 201.395 ;
      RECT 23.120 201.395 26.015 201.535 ;
      RECT 26.015 201.350 26.305 201.580 ;
      RECT 23.120 201.535 23.440 201.595 ;
      RECT 36.095 176.930 36.385 176.975 ;
      RECT 36.095 177.115 36.385 177.160 ;
      RECT 36.095 176.975 38.960 177.115 ;
      RECT 38.960 176.915 39.280 177.175 ;
      RECT 37.055 203.200 37.345 203.245 ;
      RECT 37.055 203.385 37.345 203.430 ;
      RECT 37.055 203.245 39.920 203.385 ;
      RECT 39.920 203.185 40.240 203.445 ;
      RECT 24.095 203.940 24.385 203.985 ;
      RECT 24.095 204.125 24.385 204.170 ;
      RECT 24.095 203.985 25.040 204.125 ;
      RECT 25.040 203.925 25.360 204.185 ;
      RECT 28.880 203.925 29.200 204.185 ;
      RECT 26.975 205.420 27.265 205.465 ;
      RECT 26.975 205.605 27.265 205.650 ;
      RECT 26.975 205.465 27.920 205.605 ;
      RECT 27.920 205.405 28.240 205.665 ;
      RECT 27.935 207.270 28.225 207.315 ;
      RECT 27.935 207.455 28.225 207.500 ;
      RECT 27.935 207.315 28.880 207.455 ;
      RECT 28.880 207.255 29.200 207.515 ;
      RECT 37.055 207.270 37.345 207.315 ;
      RECT 37.055 207.455 37.345 207.500 ;
      RECT 37.055 207.315 38.000 207.455 ;
      RECT 38.000 207.255 38.320 207.515 ;
      RECT 23.600 208.735 23.920 208.995 ;
      RECT 25.040 208.735 25.360 208.995 ;
      RECT 27.920 208.735 28.240 208.795 ;
      RECT 27.920 208.795 28.895 208.935 ;
      RECT 28.895 208.750 29.185 208.980 ;
      RECT 27.920 208.935 28.240 208.995 ;
      RECT 24.575 209.490 24.865 209.535 ;
      RECT 24.575 209.675 24.865 209.720 ;
      RECT 24.575 209.535 26.015 209.675 ;
      RECT 26.015 209.490 26.305 209.720 ;
      RECT 23.600 178.765 23.920 179.025 ;
      RECT 23.600 211.525 23.920 211.585 ;
      RECT 25.040 211.695 25.360 211.955 ;
      RECT 25.130 211.385 25.270 211.695 ;
      RECT 23.600 211.325 23.920 211.525 ;
      RECT 23.920 211.385 25.130 211.525 ;
      RECT 37.055 178.780 37.345 178.825 ;
      RECT 37.055 178.965 37.345 179.010 ;
      RECT 37.055 178.825 38.480 178.965 ;
      RECT 38.480 178.765 38.800 179.025 ;
      RECT 27.935 212.080 28.225 212.125 ;
      RECT 27.935 212.265 28.225 212.310 ;
      RECT 27.935 212.125 28.895 212.265 ;
      RECT 28.895 212.080 29.185 212.310 ;
      RECT 24.575 213.560 24.865 213.605 ;
      RECT 24.575 213.745 24.865 213.790 ;
      RECT 24.575 213.605 25.040 213.745 ;
      RECT 25.040 213.545 25.360 213.805 ;
      RECT 37.055 213.560 37.345 213.605 ;
      RECT 37.055 213.745 37.345 213.790 ;
      RECT 37.055 213.605 39.920 213.745 ;
      RECT 39.920 213.545 40.240 213.805 ;
      RECT 23.120 179.135 23.440 179.195 ;
      RECT 23.120 179.195 25.055 179.335 ;
      RECT 25.055 179.150 25.345 179.380 ;
      RECT 23.120 179.335 23.440 179.395 ;
      RECT 26.975 216.890 27.265 216.935 ;
      RECT 26.975 217.075 27.265 217.120 ;
      RECT 26.975 216.935 27.935 217.075 ;
      RECT 27.935 216.890 28.225 217.120 ;
      RECT 23.600 217.245 23.920 217.305 ;
      RECT 23.600 217.305 24.095 217.445 ;
      RECT 24.095 217.260 24.385 217.490 ;
      RECT 23.600 217.445 23.920 217.505 ;
      RECT 25.040 217.245 25.360 217.505 ;
      RECT 36.095 217.630 36.385 217.675 ;
      RECT 36.095 217.815 36.385 217.860 ;
      RECT 36.095 217.675 38.960 217.815 ;
      RECT 38.960 217.615 39.280 217.875 ;
      RECT 23.600 219.835 23.920 219.895 ;
      RECT 23.600 219.895 24.575 220.035 ;
      RECT 24.575 219.850 24.865 220.080 ;
      RECT 23.600 220.035 23.920 220.095 ;
      RECT 25.040 219.835 25.360 219.895 ;
      RECT 25.040 219.895 25.535 220.035 ;
      RECT 25.535 219.850 25.825 220.080 ;
      RECT 25.040 220.035 25.360 220.095 ;
      RECT 27.455 220.220 27.745 220.265 ;
      RECT 27.455 220.405 27.745 220.450 ;
      RECT 27.455 220.265 28.415 220.405 ;
      RECT 28.415 220.220 28.705 220.450 ;
      RECT 36.575 220.220 36.865 220.265 ;
      RECT 36.575 220.405 36.865 220.450 ;
      RECT 36.575 220.265 39.920 220.405 ;
      RECT 39.920 220.205 40.240 220.465 ;
      RECT 24.575 170.640 24.865 170.685 ;
      RECT 24.575 170.825 24.865 170.870 ;
      RECT 24.575 170.685 25.520 170.825 ;
      RECT 25.520 170.625 25.840 170.885 ;
      RECT 27.935 179.520 28.225 179.565 ;
      RECT 27.935 179.705 28.225 179.750 ;
      RECT 27.935 179.565 28.895 179.705 ;
      RECT 28.895 179.520 29.185 179.750 ;
      RECT 19.280 176.175 19.600 176.235 ;
      RECT 19.280 176.235 19.775 176.375 ;
      RECT 19.775 176.190 20.065 176.420 ;
      RECT 19.280 176.375 19.600 176.435 ;
      RECT 12.080 195.415 12.400 195.675 ;
      RECT 9.680 176.545 10.000 176.605 ;
      RECT 9.680 176.605 11.615 176.745 ;
      RECT 11.615 176.560 11.905 176.790 ;
      RECT 9.680 176.745 10.000 176.805 ;
      RECT 10.175 208.380 10.465 208.425 ;
      RECT 12.575 208.380 12.865 208.425 ;
      RECT 10.175 208.565 10.465 208.610 ;
      RECT 12.575 208.565 12.865 208.610 ;
      RECT 10.175 208.425 17.855 208.565 ;
      RECT 17.855 208.380 18.145 208.610 ;
      RECT 11.615 208.750 11.905 208.795 ;
      RECT 11.615 208.935 11.905 208.980 ;
      RECT 11.615 208.795 14.960 208.935 ;
      RECT 14.960 208.735 15.280 208.995 ;
      RECT 12.080 187.275 12.400 187.335 ;
      RECT 12.080 187.335 13.055 187.475 ;
      RECT 13.055 187.290 13.345 187.520 ;
      RECT 12.080 187.475 12.400 187.535 ;
      RECT 11.600 170.995 11.920 171.055 ;
      RECT 11.600 171.055 12.575 171.195 ;
      RECT 12.575 171.010 12.865 171.240 ;
      RECT 11.600 171.195 11.920 171.255 ;
      RECT 14.000 196.155 14.320 196.415 ;
      RECT 7.280 209.105 7.600 209.165 ;
      RECT 7.280 209.165 8.735 209.305 ;
      RECT 8.735 209.120 9.025 209.350 ;
      RECT 7.280 209.305 7.600 209.365 ;
      RECT 19.775 209.120 20.065 209.165 ;
      RECT 19.775 209.305 20.065 209.350 ;
      RECT 19.775 209.165 20.240 209.305 ;
      RECT 20.240 209.105 20.560 209.365 ;
      RECT 12.080 179.135 12.400 179.395 ;
      RECT 8.240 176.915 8.560 177.175 ;
      RECT 12.560 211.695 12.880 211.755 ;
      RECT 12.560 211.755 13.535 211.895 ;
      RECT 13.535 211.710 13.825 211.940 ;
      RECT 12.560 211.895 12.880 211.955 ;
      RECT 14.960 188.015 15.280 188.275 ;
      RECT 20.240 176.915 20.560 177.175 ;
      RECT 10.655 200.240 10.945 200.285 ;
      RECT 13.055 200.240 13.345 200.285 ;
      RECT 10.655 200.425 10.945 200.470 ;
      RECT 13.055 200.425 13.345 200.470 ;
      RECT 10.655 200.285 18.335 200.425 ;
      RECT 18.335 200.240 18.625 200.470 ;
      RECT 15.440 212.435 15.760 212.695 ;
      RECT 14.495 171.750 14.785 171.795 ;
      RECT 14.495 171.935 14.785 171.980 ;
      RECT 14.495 171.795 19.280 171.935 ;
      RECT 19.280 171.735 19.600 171.995 ;
      RECT 12.095 200.610 12.385 200.655 ;
      RECT 12.095 200.795 12.385 200.840 ;
      RECT 12.095 200.655 13.520 200.795 ;
      RECT 13.520 200.595 13.840 200.855 ;
      RECT 8.240 179.875 8.560 179.935 ;
      RECT 8.240 179.935 14.015 180.075 ;
      RECT 14.015 179.890 14.305 180.120 ;
      RECT 8.240 180.075 8.560 180.135 ;
      RECT 8.735 216.520 9.025 216.565 ;
      RECT 11.135 216.520 11.425 216.565 ;
      RECT 8.735 216.705 9.025 216.750 ;
      RECT 11.135 216.705 11.425 216.750 ;
      RECT 8.735 216.565 16.415 216.705 ;
      RECT 16.415 216.520 16.705 216.750 ;
      RECT 7.280 216.505 7.600 216.765 ;
      RECT 7.280 200.965 7.600 201.025 ;
      RECT 7.280 201.165 7.600 201.225 ;
      RECT 7.280 201.025 9.200 201.165 ;
      RECT 9.200 200.965 9.520 201.225 ;
      RECT 18.335 217.260 18.625 217.305 ;
      RECT 18.335 217.445 18.625 217.490 ;
      RECT 18.335 217.305 20.240 217.445 ;
      RECT 20.240 217.245 20.560 217.505 ;
      RECT 20.240 200.965 20.560 201.225 ;
      RECT 10.655 183.960 10.945 184.005 ;
      RECT 13.055 183.960 13.345 184.005 ;
      RECT 10.655 184.145 10.945 184.190 ;
      RECT 13.055 184.145 13.345 184.190 ;
      RECT 10.655 184.005 18.335 184.145 ;
      RECT 18.335 183.960 18.625 184.190 ;
      RECT 2.480 217.615 2.800 217.675 ;
      RECT 9.290 217.305 9.430 217.675 ;
      RECT 3.530 217.305 9.290 217.445 ;
      RECT 9.290 217.675 10.175 217.815 ;
      RECT 10.175 217.630 10.465 217.860 ;
      RECT 2.800 217.675 3.530 217.815 ;
      RECT 2.480 217.675 2.800 217.875 ;
      RECT 3.530 217.445 3.670 217.815 ;
      RECT 19.370 192.515 20.255 192.655 ;
      RECT 20.255 192.470 20.545 192.700 ;
      RECT 14.960 192.655 15.280 192.715 ;
      RECT 16.010 192.515 16.150 192.885 ;
      RECT 14.960 192.455 15.280 192.655 ;
      RECT 15.280 192.515 16.010 192.655 ;
      RECT 16.010 192.885 19.370 193.025 ;
      RECT 19.370 192.655 19.510 193.025 ;
      RECT 15.440 219.465 15.760 219.525 ;
      RECT 15.440 219.525 19.775 219.665 ;
      RECT 19.775 219.480 20.065 219.710 ;
      RECT 15.440 219.665 15.760 219.725 ;
      RECT 20.240 219.465 20.560 219.725 ;
      RECT 8.240 184.315 8.560 184.375 ;
      RECT 8.240 184.375 12.095 184.515 ;
      RECT 12.095 184.330 12.385 184.560 ;
      RECT 8.240 184.515 8.560 184.575 ;
      RECT 9.200 184.685 9.520 184.945 ;
      RECT 12.560 203.555 12.880 203.615 ;
      RECT 12.560 203.615 13.055 203.755 ;
      RECT 13.055 203.570 13.345 203.800 ;
      RECT 12.560 203.755 12.880 203.815 ;
      RECT 8.735 193.210 9.025 193.255 ;
      RECT 13.130 192.885 13.270 193.255 ;
      RECT 9.770 192.885 13.130 193.025 ;
      RECT 9.025 193.255 9.770 193.395 ;
      RECT 8.735 193.255 9.025 193.440 ;
      RECT 9.770 193.025 9.910 193.395 ;
      RECT 13.130 193.255 14.000 193.395 ;
      RECT 14.000 193.195 14.320 193.455 ;
      RECT 20.240 184.685 20.560 184.945 ;
      RECT 14.960 204.295 15.280 204.555 ;
      RECT 8.240 221.685 8.560 221.945 ;
      RECT 9.680 167.295 10.000 167.355 ;
      RECT 9.680 167.355 11.135 167.495 ;
      RECT 11.135 167.310 11.425 167.540 ;
      RECT 9.680 167.495 10.000 167.555 ;
      RECT 10.175 167.680 10.465 167.725 ;
      RECT 12.575 167.680 12.865 167.725 ;
      RECT 10.175 167.865 10.465 167.910 ;
      RECT 12.575 167.865 12.865 167.910 ;
      RECT 10.175 167.725 17.855 167.865 ;
      RECT 17.855 167.680 18.145 167.910 ;
      RECT 8.720 167.665 9.040 167.925 ;
      RECT 7.760 168.035 8.080 168.095 ;
      RECT 7.760 168.095 11.615 168.235 ;
      RECT 11.615 168.050 11.905 168.280 ;
      RECT 7.760 168.235 8.080 168.295 ;
      RECT 15.440 131.035 15.760 131.295 ;
      RECT 11.135 135.120 11.425 135.165 ;
      RECT 13.535 135.120 13.825 135.165 ;
      RECT 11.135 135.305 11.425 135.350 ;
      RECT 13.535 135.305 13.825 135.350 ;
      RECT 11.135 135.165 18.815 135.305 ;
      RECT 18.815 135.120 19.105 135.350 ;
      RECT 9.680 135.105 10.000 135.365 ;
      RECT 12.080 135.475 12.400 135.735 ;
      RECT 12.575 135.490 12.865 135.535 ;
      RECT 12.575 135.675 12.865 135.720 ;
      RECT 12.575 135.535 15.440 135.675 ;
      RECT 15.440 135.475 15.760 135.735 ;
      RECT 10.175 118.840 10.465 118.885 ;
      RECT 12.575 118.840 12.865 118.885 ;
      RECT 10.175 119.025 10.465 119.070 ;
      RECT 12.575 119.025 12.865 119.070 ;
      RECT 10.175 118.885 17.855 119.025 ;
      RECT 17.855 118.840 18.145 119.070 ;
      RECT 11.600 138.435 11.920 138.495 ;
      RECT 13.040 138.435 13.360 138.495 ;
      RECT 11.600 138.495 13.535 138.635 ;
      RECT 13.535 138.450 13.825 138.680 ;
      RECT 11.600 138.635 11.920 138.695 ;
      RECT 13.040 138.635 13.360 138.695 ;
      RECT 12.575 122.170 12.865 122.215 ;
      RECT 12.575 122.355 12.865 122.400 ;
      RECT 12.575 122.215 13.520 122.355 ;
      RECT 13.520 122.155 13.840 122.415 ;
      RECT 15.440 139.175 15.760 139.435 ;
      RECT 11.600 119.195 11.920 119.455 ;
      RECT 14.495 122.910 14.785 122.955 ;
      RECT 14.495 123.095 14.785 123.140 ;
      RECT 14.495 122.955 20.240 123.095 ;
      RECT 20.240 122.895 20.560 123.155 ;
      RECT 8.735 119.580 9.025 119.625 ;
      RECT 8.735 119.765 9.025 119.810 ;
      RECT 8.735 119.625 9.680 119.765 ;
      RECT 9.680 119.565 10.000 119.825 ;
      RECT 12.080 143.985 12.400 144.045 ;
      RECT 12.080 144.045 12.575 144.185 ;
      RECT 12.575 144.000 12.865 144.230 ;
      RECT 12.080 144.185 12.400 144.245 ;
      RECT 9.200 144.355 9.520 144.615 ;
      RECT 11.600 146.575 11.920 146.835 ;
      RECT 20.240 127.335 20.560 127.595 ;
      RECT 9.200 147.315 9.520 147.375 ;
      RECT 9.200 147.375 13.535 147.515 ;
      RECT 13.535 147.330 13.825 147.560 ;
      RECT 9.200 147.515 9.520 147.575 ;
      RECT 13.040 151.385 13.360 151.645 ;
      RECT 11.135 152.140 11.425 152.185 ;
      RECT 11.135 152.325 11.425 152.370 ;
      RECT 11.135 152.185 11.600 152.325 ;
      RECT 11.600 152.125 11.920 152.385 ;
      RECT 12.080 127.705 12.400 127.965 ;
      RECT 9.200 154.345 9.520 154.405 ;
      RECT 9.200 154.405 10.175 154.545 ;
      RECT 10.175 154.360 10.465 154.590 ;
      RECT 9.200 154.545 9.520 154.605 ;
      RECT 19.280 119.565 19.600 119.625 ;
      RECT 19.280 119.625 19.775 119.765 ;
      RECT 19.775 119.580 20.065 119.810 ;
      RECT 19.280 119.765 19.600 119.825 ;
      RECT 8.735 155.470 9.025 155.515 ;
      RECT 11.135 155.470 11.425 155.515 ;
      RECT 8.735 155.655 9.025 155.700 ;
      RECT 11.135 155.655 11.425 155.700 ;
      RECT 8.735 155.515 16.415 155.655 ;
      RECT 16.415 155.470 16.705 155.700 ;
      RECT 7.295 155.470 7.585 155.515 ;
      RECT 7.295 155.655 7.585 155.700 ;
      RECT 7.295 155.515 8.240 155.655 ;
      RECT 8.240 155.455 8.560 155.715 ;
      RECT 9.680 155.825 10.000 155.885 ;
      RECT 9.680 156.025 10.000 156.085 ;
      RECT 9.680 155.885 12.560 156.025 ;
      RECT 12.560 155.825 12.880 156.085 ;
      RECT 8.735 128.090 9.025 128.135 ;
      RECT 8.735 128.275 9.025 128.320 ;
      RECT 8.735 128.135 15.440 128.275 ;
      RECT 15.440 128.075 15.760 128.335 ;
      RECT 13.520 130.295 13.840 130.555 ;
      RECT 18.800 159.895 19.120 159.955 ;
      RECT 18.800 159.955 19.295 160.095 ;
      RECT 19.295 159.910 19.585 160.140 ;
      RECT 18.800 160.095 19.120 160.155 ;
      RECT 9.680 160.265 10.000 160.325 ;
      RECT 9.680 160.325 11.135 160.465 ;
      RECT 11.135 160.280 11.425 160.510 ;
      RECT 9.680 160.465 10.000 160.525 ;
      RECT 7.760 160.635 8.080 160.895 ;
      RECT 11.600 162.855 11.920 162.915 ;
      RECT 11.600 162.915 12.575 163.055 ;
      RECT 12.575 162.870 12.865 163.100 ;
      RECT 11.600 163.055 11.920 163.115 ;
      RECT 11.135 119.950 11.425 119.995 ;
      RECT 11.135 120.135 11.425 120.180 ;
      RECT 11.135 119.995 12.080 120.135 ;
      RECT 12.080 119.935 12.400 120.195 ;
      RECT 7.760 163.595 8.080 163.655 ;
      RECT 7.760 163.655 14.495 163.795 ;
      RECT 14.495 163.610 14.785 163.840 ;
      RECT 7.760 163.795 8.080 163.855 ;
      RECT 23.120 168.035 23.440 168.095 ;
      RECT 24.575 168.050 24.865 168.095 ;
      RECT 24.575 168.235 24.865 168.280 ;
      RECT 23.120 168.235 23.440 168.295 ;
      RECT 23.120 168.095 25.040 168.235 ;
      RECT 25.040 168.035 25.360 168.295 ;
      RECT 28.400 168.035 28.720 168.295 ;
      RECT 23.600 143.985 23.920 144.045 ;
      RECT 24.575 144.000 24.865 144.045 ;
      RECT 24.575 144.185 24.865 144.230 ;
      RECT 23.600 144.185 23.920 144.245 ;
      RECT 23.600 144.045 25.040 144.185 ;
      RECT 25.040 143.985 25.360 144.245 ;
      RECT 25.520 168.775 25.840 169.035 ;
      RECT 27.440 168.775 27.760 169.035 ;
      RECT 36.575 168.790 36.865 168.835 ;
      RECT 36.575 168.975 36.865 169.020 ;
      RECT 36.575 168.835 39.920 168.975 ;
      RECT 39.920 168.775 40.240 169.035 ;
      RECT 25.520 143.985 25.840 144.245 ;
      RECT 27.530 130.725 28.895 130.865 ;
      RECT 28.895 130.680 29.185 130.910 ;
      RECT 26.495 131.050 26.785 131.095 ;
      RECT 26.785 131.095 27.530 131.235 ;
      RECT 26.495 131.095 26.785 131.280 ;
      RECT 27.530 130.865 27.670 131.235 ;
      RECT 36.575 144.370 36.865 144.415 ;
      RECT 36.575 144.555 36.865 144.600 ;
      RECT 36.575 144.415 39.920 144.555 ;
      RECT 39.920 144.355 40.240 144.615 ;
      RECT 27.935 146.220 28.225 146.265 ;
      RECT 27.935 146.405 28.225 146.450 ;
      RECT 27.935 146.265 28.400 146.405 ;
      RECT 28.400 146.205 28.720 146.465 ;
      RECT 30.815 122.540 31.105 122.585 ;
      RECT 30.815 122.585 31.295 122.725 ;
      RECT 31.295 122.540 31.585 122.770 ;
      RECT 23.600 123.265 23.920 123.325 ;
      RECT 23.920 123.325 30.890 123.465 ;
      RECT 23.600 123.325 23.920 123.525 ;
      RECT 30.890 122.770 31.030 123.465 ;
      RECT 30.815 122.725 31.105 122.770 ;
      RECT 25.040 146.575 25.360 146.835 ;
      RECT 37.055 132.160 37.345 132.205 ;
      RECT 37.055 132.345 37.345 132.390 ;
      RECT 37.055 132.205 39.920 132.345 ;
      RECT 39.920 132.145 40.240 132.405 ;
      RECT 28.880 146.945 29.200 147.205 ;
      RECT 37.055 134.010 37.345 134.055 ;
      RECT 37.055 134.195 37.345 134.240 ;
      RECT 37.055 134.055 38.960 134.195 ;
      RECT 38.960 133.995 39.280 134.255 ;
      RECT 24.095 148.440 24.385 148.485 ;
      RECT 24.095 148.625 24.385 148.670 ;
      RECT 24.095 148.485 25.520 148.625 ;
      RECT 25.520 148.425 25.840 148.685 ;
      RECT 37.055 148.440 37.345 148.485 ;
      RECT 37.055 148.625 37.345 148.670 ;
      RECT 37.055 148.485 38.480 148.625 ;
      RECT 38.480 148.425 38.800 148.685 ;
      RECT 27.935 150.290 28.225 150.335 ;
      RECT 27.935 150.475 28.225 150.520 ;
      RECT 27.935 150.335 28.880 150.475 ;
      RECT 28.880 150.275 29.200 150.535 ;
      RECT 27.935 124.020 28.225 124.065 ;
      RECT 27.935 124.205 28.225 124.250 ;
      RECT 27.935 124.065 28.880 124.205 ;
      RECT 28.880 124.005 29.200 124.265 ;
      RECT 24.575 151.585 24.865 151.630 ;
      RECT 26.090 151.445 26.230 151.815 ;
      RECT 24.575 151.400 24.865 151.585 ;
      RECT 24.865 151.445 26.090 151.585 ;
      RECT 26.090 151.815 28.895 151.955 ;
      RECT 28.895 151.770 29.185 152.000 ;
      RECT 21.695 151.770 21.985 151.815 ;
      RECT 21.695 151.955 21.985 152.000 ;
      RECT 21.695 151.815 25.040 151.955 ;
      RECT 25.040 151.755 25.360 152.015 ;
      RECT 34.160 121.785 34.480 122.045 ;
      RECT 25.520 152.125 25.840 152.185 ;
      RECT 25.520 152.185 26.015 152.325 ;
      RECT 26.015 152.140 26.305 152.370 ;
      RECT 25.520 152.325 25.840 152.385 ;
      RECT 27.935 135.490 28.225 135.535 ;
      RECT 27.935 135.675 28.225 135.720 ;
      RECT 27.935 135.535 28.895 135.675 ;
      RECT 28.895 135.490 29.185 135.720 ;
      RECT 37.055 152.510 37.345 152.555 ;
      RECT 37.055 152.695 37.345 152.740 ;
      RECT 37.055 152.555 38.960 152.695 ;
      RECT 38.960 152.495 39.280 152.755 ;
      RECT 38.480 153.235 38.800 153.295 ;
      RECT 38.480 153.435 38.800 153.495 ;
      RECT 38.480 153.295 39.920 153.435 ;
      RECT 39.920 153.235 40.240 153.495 ;
      RECT 23.615 154.360 23.905 154.405 ;
      RECT 23.615 154.545 23.905 154.590 ;
      RECT 23.615 154.405 26.015 154.545 ;
      RECT 26.015 154.360 26.305 154.590 ;
      RECT 34.655 117.915 34.945 117.960 ;
      RECT 38.090 117.775 38.960 117.915 ;
      RECT 38.960 117.715 39.280 117.975 ;
      RECT 35.690 117.775 35.830 118.145 ;
      RECT 34.655 117.730 34.945 117.915 ;
      RECT 34.945 117.775 35.690 117.915 ;
      RECT 35.690 118.145 38.090 118.285 ;
      RECT 38.090 117.915 38.230 118.285 ;
      RECT 37.055 154.360 37.345 154.405 ;
      RECT 37.055 154.545 37.345 154.590 ;
      RECT 37.055 154.405 39.920 154.545 ;
      RECT 39.920 154.345 40.240 154.605 ;
      RECT 28.880 127.335 29.200 127.595 ;
      RECT 25.040 154.715 25.360 154.975 ;
      RECT 27.935 155.100 28.225 155.145 ;
      RECT 27.935 155.285 28.225 155.330 ;
      RECT 27.935 155.145 28.895 155.285 ;
      RECT 28.895 155.100 29.185 155.330 ;
      RECT 22.160 155.085 22.480 155.145 ;
      RECT 22.160 155.145 22.655 155.285 ;
      RECT 22.655 155.100 22.945 155.330 ;
      RECT 22.160 155.285 22.480 155.345 ;
      RECT 23.600 135.475 23.920 135.535 ;
      RECT 23.600 135.535 25.055 135.675 ;
      RECT 25.055 135.490 25.345 135.720 ;
      RECT 23.600 135.675 23.920 135.735 ;
      RECT 23.135 122.170 23.425 122.215 ;
      RECT 23.135 122.355 23.425 122.400 ;
      RECT 23.135 122.215 23.600 122.355 ;
      RECT 23.600 122.155 23.920 122.415 ;
      RECT 25.520 136.215 25.840 136.275 ;
      RECT 25.520 136.275 26.015 136.415 ;
      RECT 26.015 136.230 26.305 136.460 ;
      RECT 25.520 136.415 25.840 136.475 ;
      RECT 37.055 158.430 37.345 158.475 ;
      RECT 37.055 158.615 37.345 158.660 ;
      RECT 37.055 158.475 38.960 158.615 ;
      RECT 38.960 158.415 39.280 158.675 ;
      RECT 37.055 138.080 37.345 138.125 ;
      RECT 37.055 138.265 37.345 138.310 ;
      RECT 37.055 138.125 39.920 138.265 ;
      RECT 39.920 138.065 40.240 138.325 ;
      RECT 29.840 122.155 30.160 122.415 ;
      RECT 27.935 159.910 28.225 159.955 ;
      RECT 27.935 160.095 28.225 160.140 ;
      RECT 27.935 159.955 28.895 160.095 ;
      RECT 28.895 159.910 29.185 160.140 ;
      RECT 27.440 119.195 27.760 119.455 ;
      RECT 25.040 159.895 25.360 160.155 ;
      RECT 28.880 138.805 29.200 139.065 ;
      RECT 37.055 128.090 37.345 128.135 ;
      RECT 37.055 128.275 37.345 128.320 ;
      RECT 37.055 128.135 38.960 128.275 ;
      RECT 38.960 128.075 39.280 128.335 ;
      RECT 25.520 160.635 25.840 160.695 ;
      RECT 25.520 160.695 26.015 160.835 ;
      RECT 26.015 160.650 26.305 160.880 ;
      RECT 25.520 160.835 25.840 160.895 ;
      RECT 23.615 162.500 23.905 162.545 ;
      RECT 23.615 162.685 23.905 162.730 ;
      RECT 23.615 162.545 26.015 162.685 ;
      RECT 26.015 162.500 26.305 162.730 ;
      RECT 37.055 162.500 37.345 162.545 ;
      RECT 37.055 162.685 37.345 162.730 ;
      RECT 37.055 162.545 39.920 162.685 ;
      RECT 39.920 162.485 40.240 162.745 ;
      RECT 25.520 140.285 25.840 140.345 ;
      RECT 25.520 140.345 27.935 140.485 ;
      RECT 27.935 140.300 28.225 140.530 ;
      RECT 25.520 140.485 25.840 140.545 ;
      RECT 25.040 162.855 25.360 163.115 ;
      RECT 27.935 163.240 28.225 163.285 ;
      RECT 27.935 163.425 28.225 163.470 ;
      RECT 27.935 163.285 28.895 163.425 ;
      RECT 28.895 163.240 29.185 163.470 ;
      RECT 27.455 142.150 27.745 142.195 ;
      RECT 27.455 142.335 27.745 142.380 ;
      RECT 27.455 142.195 28.880 142.335 ;
      RECT 28.880 142.135 29.200 142.395 ;
      RECT 27.935 129.940 28.225 129.985 ;
      RECT 27.935 130.125 28.225 130.170 ;
      RECT 27.935 129.985 29.840 130.125 ;
      RECT 29.840 129.925 30.160 130.185 ;
      RECT 30.410 121.845 32.255 121.985 ;
      RECT 32.255 121.800 32.545 122.030 ;
      RECT 27.455 122.540 27.745 122.585 ;
      RECT 27.745 122.585 30.410 122.725 ;
      RECT 27.455 122.585 27.745 122.770 ;
      RECT 30.410 121.985 30.550 122.725 ;
      RECT 28.400 143.615 28.720 143.875 ;
      RECT 23.600 130.295 23.920 130.555 ;
      RECT 26.015 121.800 26.305 121.845 ;
      RECT 26.015 121.985 26.305 122.030 ;
      RECT 26.015 121.845 27.440 121.985 ;
      RECT 27.440 121.785 27.760 122.045 ;
      RECT 18.320 87.375 18.640 87.435 ;
      RECT 18.320 87.435 23.135 87.575 ;
      RECT 23.135 87.390 23.425 87.620 ;
      RECT 18.320 87.575 18.640 87.635 ;
      RECT 20.735 89.240 21.025 89.285 ;
      RECT 22.640 89.225 22.960 89.285 ;
      RECT 20.735 89.425 21.025 89.470 ;
      RECT 20.735 89.285 26.015 89.425 ;
      RECT 26.015 89.240 26.305 89.470 ;
      RECT 22.640 89.425 22.960 89.485 ;
      RECT 20.720 95.515 21.040 95.775 ;
      RECT 18.320 97.365 18.640 97.425 ;
      RECT 18.320 97.425 20.735 97.565 ;
      RECT 20.735 97.380 21.025 97.610 ;
      RECT 18.320 97.565 18.640 97.625 ;
      RECT 31.370 97.795 31.775 97.935 ;
      RECT 31.775 97.750 32.065 97.980 ;
      RECT 27.935 98.305 28.225 98.350 ;
      RECT 20.720 98.305 21.040 98.365 ;
      RECT 24.650 98.165 24.790 98.535 ;
      RECT 20.720 98.105 21.040 98.305 ;
      RECT 21.040 98.165 24.650 98.305 ;
      RECT 28.970 98.165 29.110 98.535 ;
      RECT 27.050 98.165 28.970 98.305 ;
      RECT 27.935 98.120 28.225 98.165 ;
      RECT 24.650 98.535 27.050 98.675 ;
      RECT 27.050 98.305 27.190 98.675 ;
      RECT 28.970 98.535 31.370 98.675 ;
      RECT 31.370 97.935 31.510 98.675 ;
      RECT 14.495 98.490 14.785 98.535 ;
      RECT 19.775 98.490 20.065 98.535 ;
      RECT 14.495 98.675 14.785 98.720 ;
      RECT 19.775 98.675 20.065 98.720 ;
      RECT 14.495 98.535 22.175 98.675 ;
      RECT 22.175 98.490 22.465 98.720 ;
      RECT 20.240 98.845 20.560 98.905 ;
      RECT 19.370 98.905 21.215 99.045 ;
      RECT 21.215 98.860 21.505 99.090 ;
      RECT 15.440 99.045 15.760 99.105 ;
      RECT 20.240 99.045 20.560 99.105 ;
      RECT 16.490 98.905 16.630 99.275 ;
      RECT 15.440 98.845 15.760 99.045 ;
      RECT 15.760 98.905 16.490 99.045 ;
      RECT 16.490 99.275 19.370 99.415 ;
      RECT 19.370 99.045 19.510 99.415 ;
      RECT 13.535 102.560 13.825 102.605 ;
      RECT 18.815 102.560 19.105 102.605 ;
      RECT 13.535 102.745 13.825 102.790 ;
      RECT 18.815 102.745 19.105 102.790 ;
      RECT 13.535 102.605 21.215 102.745 ;
      RECT 21.215 102.560 21.505 102.790 ;
      RECT 17.375 106.075 17.665 106.120 ;
      RECT 22.730 105.935 23.600 106.075 ;
      RECT 23.600 105.875 23.920 106.135 ;
      RECT 18.410 105.935 18.550 106.305 ;
      RECT 17.375 105.890 17.665 106.075 ;
      RECT 17.665 105.935 18.410 106.075 ;
      RECT 18.410 106.305 22.730 106.445 ;
      RECT 22.730 106.075 22.870 106.445 ;
      RECT 14.495 110.330 14.785 110.375 ;
      RECT 14.495 110.515 14.785 110.560 ;
      RECT 14.495 110.375 39.920 110.515 ;
      RECT 39.920 110.315 40.240 110.575 ;
      RECT 16.415 113.845 16.705 113.890 ;
      RECT 22.250 113.705 24.095 113.845 ;
      RECT 24.095 113.660 24.385 113.890 ;
      RECT 17.450 113.705 17.590 114.445 ;
      RECT 16.415 113.660 16.705 113.845 ;
      RECT 16.705 113.705 17.450 113.845 ;
      RECT 17.450 114.445 22.250 114.585 ;
      RECT 22.250 113.845 22.390 114.585 ;
      RECT 19.775 48.540 20.065 48.585 ;
      RECT 19.775 48.725 20.065 48.770 ;
      RECT 19.775 48.585 22.655 48.725 ;
      RECT 22.655 48.540 22.945 48.770 ;
      RECT 20.255 49.280 20.545 49.510 ;
      RECT 20.330 48.725 20.470 49.280 ;
      RECT 17.930 53.025 18.070 53.395 ;
      RECT 9.290 53.025 17.930 53.165 ;
      RECT 17.930 53.395 21.680 53.535 ;
      RECT 21.680 53.335 22.000 53.595 ;
      RECT 8.255 53.720 8.545 53.765 ;
      RECT 8.545 53.765 9.290 53.905 ;
      RECT 8.255 53.765 8.545 53.950 ;
      RECT 9.290 53.165 9.430 53.905 ;
      RECT 18.800 54.815 19.120 54.875 ;
      RECT 18.800 54.875 22.655 55.015 ;
      RECT 22.655 54.830 22.945 55.060 ;
      RECT 18.800 55.015 19.120 55.075 ;
      RECT 19.295 57.420 19.585 57.465 ;
      RECT 19.295 57.605 19.585 57.650 ;
      RECT 19.295 57.465 23.600 57.605 ;
      RECT 23.600 57.405 23.920 57.665 ;
      RECT 12.575 61.860 12.865 61.905 ;
      RECT 17.855 61.860 18.145 61.905 ;
      RECT 12.575 62.045 12.865 62.090 ;
      RECT 17.855 62.045 18.145 62.090 ;
      RECT 12.575 61.905 20.255 62.045 ;
      RECT 20.255 61.860 20.545 62.090 ;
      RECT 24.170 61.905 25.040 62.045 ;
      RECT 25.040 61.845 25.360 62.105 ;
      RECT 23.120 62.215 23.440 62.275 ;
      RECT 23.120 62.275 24.095 62.415 ;
      RECT 24.095 62.230 24.385 62.460 ;
      RECT 24.170 62.045 24.310 62.230 ;
      RECT 23.120 62.415 23.440 62.475 ;
      RECT 15.050 69.305 15.190 69.675 ;
      RECT 6.410 69.305 15.050 69.445 ;
      RECT 15.050 69.675 21.680 69.815 ;
      RECT 21.680 69.615 22.000 69.875 ;
      RECT 5.375 70.000 5.665 70.045 ;
      RECT 5.665 70.045 6.410 70.185 ;
      RECT 5.375 70.045 5.665 70.230 ;
      RECT 6.410 69.445 6.550 70.185 ;
      RECT 20.240 70.555 20.560 70.615 ;
      RECT 21.290 70.415 21.430 70.785 ;
      RECT 20.240 70.355 20.560 70.555 ;
      RECT 20.560 70.415 21.290 70.555 ;
      RECT 21.290 70.785 26.015 70.925 ;
      RECT 26.015 70.740 26.305 70.970 ;
      RECT 22.250 73.375 22.655 73.515 ;
      RECT 22.655 73.330 22.945 73.560 ;
      RECT 19.295 73.700 19.585 73.745 ;
      RECT 20.255 73.700 20.545 73.745 ;
      RECT 19.295 73.885 19.585 73.930 ;
      RECT 20.255 73.885 20.545 73.930 ;
      RECT 19.295 73.745 22.250 73.885 ;
      RECT 22.250 73.515 22.390 73.885 ;
      RECT 13.535 78.140 13.825 78.185 ;
      RECT 18.815 78.140 19.105 78.185 ;
      RECT 13.535 78.325 13.825 78.370 ;
      RECT 18.815 78.325 19.105 78.370 ;
      RECT 13.535 78.185 21.215 78.325 ;
      RECT 21.215 78.140 21.505 78.370 ;
      RECT 19.775 81.100 20.065 81.145 ;
      RECT 22.640 81.085 22.960 81.145 ;
      RECT 19.775 81.285 20.065 81.330 ;
      RECT 19.775 81.145 26.015 81.285 ;
      RECT 26.015 81.100 26.305 81.330 ;
      RECT 22.640 81.285 22.960 81.345 ;
      RECT 8.735 87.205 9.025 87.250 ;
      RECT 11.210 87.065 11.350 87.250 ;
      RECT 8.735 87.020 9.025 87.205 ;
      RECT 9.025 87.065 11.210 87.205 ;
      RECT 15.050 87.065 21.680 87.205 ;
      RECT 21.680 87.005 22.000 87.265 ;
      RECT 11.210 87.250 15.050 87.390 ;
      RECT 15.050 87.205 15.190 87.390 ;
      RECT 18.335 15.980 18.625 16.025 ;
      RECT 25.040 15.965 25.360 16.025 ;
      RECT 18.335 16.165 18.625 16.210 ;
      RECT 18.335 16.025 25.535 16.165 ;
      RECT 25.535 15.980 25.825 16.210 ;
      RECT 25.040 16.165 25.360 16.225 ;
      RECT 18.335 24.120 18.625 24.165 ;
      RECT 23.120 24.105 23.440 24.165 ;
      RECT 18.335 24.305 18.625 24.350 ;
      RECT 18.335 24.165 23.615 24.305 ;
      RECT 23.615 24.120 23.905 24.350 ;
      RECT 23.120 24.305 23.440 24.365 ;
      RECT 18.815 29.670 19.105 29.715 ;
      RECT 18.815 29.855 19.105 29.900 ;
      RECT 20.330 29.900 20.470 30.085 ;
      RECT 20.255 29.670 20.545 29.900 ;
      RECT 18.815 29.715 20.255 29.855 ;
      RECT 20.330 30.085 22.655 30.225 ;
      RECT 22.655 30.040 22.945 30.270 ;
      RECT 18.410 32.675 18.550 33.045 ;
      RECT 14.570 32.675 18.410 32.815 ;
      RECT 21.680 32.985 22.000 33.045 ;
      RECT 18.410 33.045 22.175 33.185 ;
      RECT 22.175 33.000 22.465 33.230 ;
      RECT 7.760 33.185 8.080 33.245 ;
      RECT 21.680 33.185 22.000 33.245 ;
      RECT 8.810 33.045 8.950 33.415 ;
      RECT 7.760 32.985 8.080 33.185 ;
      RECT 8.080 33.045 8.810 33.185 ;
      RECT 12.170 33.045 14.570 33.185 ;
      RECT 14.570 32.815 14.710 33.185 ;
      RECT 8.810 33.415 12.170 33.555 ;
      RECT 12.170 33.185 12.310 33.555 ;
      RECT 13.055 33.370 13.345 33.415 ;
      RECT 18.335 33.370 18.625 33.415 ;
      RECT 13.055 33.555 13.345 33.600 ;
      RECT 18.335 33.555 18.625 33.600 ;
      RECT 13.055 33.415 20.735 33.555 ;
      RECT 20.735 33.370 21.025 33.600 ;
      RECT 19.280 36.315 19.600 36.375 ;
      RECT 19.280 36.375 22.175 36.515 ;
      RECT 22.175 36.330 22.465 36.560 ;
      RECT 19.280 36.515 19.600 36.575 ;
      RECT 26.570 40.815 26.975 40.955 ;
      RECT 26.975 40.770 27.265 41.000 ;
      RECT 3.920 41.125 4.240 41.185 ;
      RECT 26.570 40.955 26.710 41.185 ;
      RECT 25.610 41.185 30.335 41.325 ;
      RECT 30.335 41.140 30.625 41.370 ;
      RECT 4.240 41.185 8.950 41.325 ;
      RECT 3.920 41.185 4.240 41.385 ;
      RECT 8.950 41.000 14.570 41.140 ;
      RECT 8.810 41.000 8.950 41.185 ;
      RECT 14.570 40.955 14.710 41.140 ;
      RECT 17.450 40.815 17.590 41.325 ;
      RECT 14.570 40.815 17.450 40.955 ;
      RECT 23.210 41.185 23.350 41.555 ;
      RECT 17.590 41.185 23.210 41.325 ;
      RECT 23.210 41.555 25.610 41.695 ;
      RECT 25.610 41.325 25.750 41.695 ;
      RECT 19.280 42.605 19.600 42.665 ;
      RECT 19.280 42.665 22.175 42.805 ;
      RECT 22.175 42.620 22.465 42.850 ;
      RECT 19.280 42.805 19.600 42.865 ;
      RECT 13.055 45.580 13.345 45.625 ;
      RECT 18.335 45.580 18.625 45.625 ;
      RECT 13.055 45.765 13.345 45.810 ;
      RECT 18.335 45.765 18.625 45.810 ;
      RECT 13.055 45.625 20.735 45.765 ;
      RECT 20.735 45.580 21.025 45.810 ;
      RECT 25.520 113.645 25.840 113.705 ;
      RECT 25.520 113.705 26.015 113.845 ;
      RECT 26.015 113.660 26.305 113.890 ;
      RECT 25.520 113.845 25.840 113.905 ;
      RECT 23.135 114.030 23.425 114.075 ;
      RECT 23.135 114.215 23.425 114.260 ;
      RECT 23.135 114.075 23.600 114.215 ;
      RECT 23.600 114.015 23.920 114.275 ;
      RECT 23.615 95.530 23.905 95.575 ;
      RECT 23.615 95.715 23.905 95.760 ;
      RECT 23.615 95.575 26.015 95.715 ;
      RECT 26.015 95.530 26.305 95.760 ;
      RECT 26.975 113.845 27.265 113.890 ;
      RECT 38.090 113.705 39.920 113.845 ;
      RECT 39.920 113.645 40.240 113.905 ;
      RECT 35.210 113.705 35.350 114.075 ;
      RECT 33.290 113.705 35.210 113.845 ;
      RECT 35.210 114.075 38.090 114.215 ;
      RECT 38.090 113.845 38.230 114.215 ;
      RECT 28.010 113.705 28.150 114.445 ;
      RECT 26.975 113.660 27.265 113.845 ;
      RECT 27.265 113.705 28.010 113.845 ;
      RECT 28.010 114.445 33.290 114.585 ;
      RECT 33.290 113.845 33.430 114.585 ;
      RECT 34.160 114.385 34.480 114.645 ;
      RECT 37.055 87.390 37.345 87.435 ;
      RECT 37.055 87.575 37.345 87.620 ;
      RECT 37.055 87.435 38.960 87.575 ;
      RECT 38.960 87.375 39.280 87.635 ;
      RECT 25.040 89.595 25.360 89.855 ;
      RECT 23.120 97.365 23.440 97.565 ;
      RECT 24.170 97.425 24.310 97.610 ;
      RECT 23.440 97.425 24.170 97.565 ;
      RECT 23.120 97.565 23.440 97.625 ;
      RECT 24.170 97.610 29.930 97.750 ;
      RECT 29.930 97.565 30.070 97.750 ;
      RECT 30.815 97.750 31.105 97.980 ;
      RECT 30.890 97.425 31.030 97.750 ;
      RECT 29.930 97.425 30.890 97.565 ;
      RECT 27.935 89.980 28.225 90.025 ;
      RECT 27.935 90.165 28.225 90.210 ;
      RECT 27.935 90.025 28.895 90.165 ;
      RECT 28.895 89.980 29.185 90.210 ;
      RECT 37.055 89.980 37.345 90.025 ;
      RECT 37.055 90.165 37.345 90.210 ;
      RECT 37.055 90.025 39.920 90.165 ;
      RECT 39.920 89.965 40.240 90.225 ;
      RECT 26.975 62.230 27.265 62.275 ;
      RECT 26.975 62.415 27.265 62.460 ;
      RECT 26.975 62.275 27.935 62.415 ;
      RECT 27.935 62.230 28.225 62.460 ;
      RECT 22.640 98.475 22.960 98.535 ;
      RECT 22.640 98.535 23.615 98.675 ;
      RECT 23.615 98.490 23.905 98.720 ;
      RECT 22.640 98.675 22.960 98.735 ;
      RECT 21.680 62.585 22.000 62.845 ;
      RECT 23.600 62.585 23.920 62.645 ;
      RECT 23.600 62.645 25.055 62.785 ;
      RECT 25.055 62.600 25.345 62.830 ;
      RECT 23.600 62.785 23.920 62.845 ;
      RECT 36.095 62.970 36.385 63.015 ;
      RECT 36.095 63.155 36.385 63.200 ;
      RECT 36.095 63.015 39.920 63.155 ;
      RECT 39.920 62.955 40.240 63.215 ;
      RECT 25.520 65.545 25.840 65.605 ;
      RECT 25.520 65.605 26.015 65.745 ;
      RECT 26.015 65.560 26.305 65.790 ;
      RECT 25.520 65.745 25.840 65.805 ;
      RECT 28.880 65.545 29.200 65.805 ;
      RECT 21.215 66.670 21.505 66.715 ;
      RECT 24.650 66.345 24.790 66.715 ;
      RECT 22.250 66.345 24.650 66.485 ;
      RECT 38.090 66.345 38.230 66.715 ;
      RECT 29.930 66.345 38.090 66.485 ;
      RECT 24.650 66.715 29.930 66.855 ;
      RECT 29.930 66.485 30.070 66.855 ;
      RECT 21.505 66.715 22.250 66.855 ;
      RECT 21.215 66.715 21.505 66.900 ;
      RECT 22.250 66.485 22.390 66.855 ;
      RECT 38.090 66.715 38.960 66.855 ;
      RECT 38.960 66.655 39.280 66.915 ;
      RECT 37.055 67.040 37.345 67.085 ;
      RECT 37.055 67.225 37.345 67.270 ;
      RECT 37.055 67.085 39.920 67.225 ;
      RECT 39.920 67.025 40.240 67.285 ;
      RECT 24.575 68.890 24.865 68.935 ;
      RECT 24.575 69.075 24.865 69.120 ;
      RECT 24.575 68.935 25.520 69.075 ;
      RECT 25.520 68.875 25.840 69.135 ;
      RECT 27.935 68.890 28.225 68.935 ;
      RECT 27.935 69.075 28.225 69.120 ;
      RECT 27.935 68.935 28.880 69.075 ;
      RECT 28.880 68.875 29.200 69.135 ;
      RECT 37.055 68.890 37.345 68.935 ;
      RECT 37.055 69.075 37.345 69.120 ;
      RECT 37.055 68.935 38.960 69.075 ;
      RECT 38.960 68.875 39.280 69.135 ;
      RECT 37.055 93.310 37.345 93.355 ;
      RECT 37.055 93.495 37.345 93.540 ;
      RECT 37.055 93.355 39.920 93.495 ;
      RECT 39.920 93.295 40.240 93.555 ;
      RECT 21.695 70.370 21.985 70.415 ;
      RECT 23.120 70.355 23.440 70.415 ;
      RECT 21.695 70.555 21.985 70.600 ;
      RECT 21.695 70.415 25.055 70.555 ;
      RECT 25.055 70.370 25.345 70.600 ;
      RECT 23.120 70.555 23.440 70.615 ;
      RECT 28.880 70.355 29.200 70.615 ;
      RECT 25.040 99.585 25.360 99.645 ;
      RECT 25.040 99.645 27.455 99.785 ;
      RECT 27.455 99.600 27.745 99.830 ;
      RECT 25.040 99.785 25.360 99.845 ;
      RECT 21.215 71.110 21.505 71.155 ;
      RECT 21.215 71.295 21.505 71.340 ;
      RECT 21.215 71.155 22.655 71.295 ;
      RECT 22.655 71.110 22.945 71.340 ;
      RECT 24.575 72.960 24.865 73.005 ;
      RECT 24.575 73.145 24.865 73.190 ;
      RECT 24.575 73.005 28.880 73.145 ;
      RECT 28.880 72.945 29.200 73.205 ;
      RECT 37.055 72.960 37.345 73.005 ;
      RECT 37.055 73.145 37.345 73.190 ;
      RECT 37.055 73.005 39.920 73.145 ;
      RECT 39.920 72.945 40.240 73.205 ;
      RECT 23.120 73.145 23.440 73.205 ;
      RECT 24.170 73.005 24.310 73.375 ;
      RECT 21.770 73.005 24.170 73.145 ;
      RECT 23.120 72.945 23.440 73.005 ;
      RECT 21.695 73.330 21.985 73.560 ;
      RECT 21.770 73.145 21.910 73.330 ;
      RECT 24.170 73.375 25.040 73.515 ;
      RECT 25.040 73.315 25.360 73.575 ;
      RECT 33.680 99.585 34.000 99.845 ;
      RECT 27.935 73.700 28.225 73.745 ;
      RECT 27.935 73.885 28.225 73.930 ;
      RECT 27.935 73.745 28.895 73.885 ;
      RECT 28.895 73.700 29.185 73.930 ;
      RECT 25.610 73.375 26.015 73.515 ;
      RECT 26.015 73.330 26.305 73.560 ;
      RECT 21.215 74.255 21.505 74.300 ;
      RECT 22.250 74.115 22.390 74.485 ;
      RECT 21.215 74.070 21.505 74.255 ;
      RECT 21.505 74.115 22.250 74.255 ;
      RECT 22.250 74.485 25.610 74.625 ;
      RECT 25.610 73.515 25.750 74.625 ;
      RECT 27.935 94.790 28.225 94.835 ;
      RECT 27.935 94.975 28.225 95.020 ;
      RECT 27.935 94.835 28.895 94.975 ;
      RECT 28.895 94.790 29.185 95.020 ;
      RECT 21.680 78.865 22.000 78.925 ;
      RECT 21.680 78.925 22.655 79.065 ;
      RECT 22.655 78.880 22.945 79.110 ;
      RECT 21.680 79.065 22.000 79.125 ;
      RECT 22.640 102.545 22.960 102.805 ;
      RECT 27.935 81.840 28.225 81.885 ;
      RECT 27.935 82.025 28.225 82.070 ;
      RECT 27.935 81.885 28.895 82.025 ;
      RECT 28.895 81.840 29.185 82.070 ;
      RECT 25.040 81.825 25.360 82.085 ;
      RECT 37.055 83.320 37.345 83.365 ;
      RECT 37.055 83.505 37.345 83.550 ;
      RECT 37.055 83.365 39.920 83.505 ;
      RECT 39.920 83.305 40.240 83.565 ;
      RECT 27.935 86.650 28.225 86.695 ;
      RECT 27.935 86.835 28.225 86.880 ;
      RECT 27.935 86.695 28.895 86.835 ;
      RECT 28.895 86.650 29.185 86.880 ;
      RECT 22.640 86.635 22.960 86.695 ;
      RECT 22.640 86.695 23.615 86.835 ;
      RECT 23.615 86.650 23.905 86.880 ;
      RECT 22.640 86.835 22.960 86.895 ;
      RECT 25.040 86.635 25.360 86.895 ;
      RECT 26.495 102.930 26.785 102.975 ;
      RECT 26.495 103.115 26.785 103.160 ;
      RECT 26.495 102.975 27.455 103.115 ;
      RECT 27.455 102.930 27.745 103.160 ;
      RECT 24.575 87.390 24.865 87.435 ;
      RECT 24.575 87.575 24.865 87.620 ;
      RECT 24.575 87.435 26.015 87.575 ;
      RECT 26.015 87.390 26.305 87.620 ;
      RECT 23.600 103.285 23.920 103.545 ;
      RECT 24.575 103.300 24.865 103.345 ;
      RECT 24.575 103.485 24.865 103.530 ;
      RECT 24.575 103.345 25.040 103.485 ;
      RECT 25.040 103.285 25.360 103.545 ;
      RECT 35.615 103.670 35.905 103.715 ;
      RECT 35.615 103.855 35.905 103.900 ;
      RECT 35.615 103.715 38.960 103.855 ;
      RECT 38.960 103.655 39.280 103.915 ;
      RECT 22.640 94.775 22.960 95.035 ;
      RECT 33.680 106.245 34.000 106.505 ;
      RECT 28.415 107.740 28.705 107.785 ;
      RECT 38.090 107.415 38.230 107.785 ;
      RECT 29.450 107.415 38.090 107.555 ;
      RECT 28.705 107.785 29.450 107.925 ;
      RECT 28.415 107.785 28.705 107.970 ;
      RECT 29.450 107.555 29.590 107.925 ;
      RECT 38.090 107.785 39.920 107.925 ;
      RECT 39.920 107.725 40.240 107.985 ;
      RECT 23.600 94.775 23.920 94.835 ;
      RECT 23.600 94.975 23.920 95.035 ;
      RECT 23.600 94.835 25.040 94.975 ;
      RECT 25.040 94.775 25.360 95.035 ;
      RECT 25.520 111.055 25.840 111.115 ;
      RECT 25.520 111.115 26.015 111.255 ;
      RECT 26.015 111.070 26.305 111.300 ;
      RECT 25.520 111.255 25.840 111.315 ;
      RECT 34.175 111.070 34.465 111.115 ;
      RECT 34.175 111.255 34.465 111.300 ;
      RECT 34.175 111.115 39.920 111.255 ;
      RECT 39.920 111.055 40.240 111.315 ;
      RECT 12.080 73.315 12.400 73.575 ;
      RECT 15.455 90.350 15.745 90.395 ;
      RECT 15.455 90.535 15.745 90.580 ;
      RECT 15.455 90.395 18.320 90.535 ;
      RECT 18.320 90.335 18.640 90.595 ;
      RECT 7.295 62.970 7.585 63.015 ;
      RECT 11.690 62.645 11.830 63.015 ;
      RECT 8.330 62.645 11.690 62.785 ;
      RECT 7.585 63.015 8.330 63.155 ;
      RECT 7.295 63.015 7.585 63.200 ;
      RECT 8.330 62.785 8.470 63.155 ;
      RECT 11.690 63.015 13.040 63.155 ;
      RECT 13.040 62.955 13.360 63.215 ;
      RECT 8.255 103.670 8.545 103.715 ;
      RECT 8.255 103.855 8.545 103.900 ;
      RECT 8.255 103.715 11.600 103.855 ;
      RECT 11.600 103.655 11.920 103.915 ;
      RECT 14.000 74.055 14.320 74.315 ;
      RECT 11.135 65.190 11.425 65.235 ;
      RECT 11.135 65.375 11.425 65.420 ;
      RECT 11.135 65.235 12.080 65.375 ;
      RECT 12.080 65.175 12.400 65.435 ;
      RECT 16.400 77.755 16.720 77.815 ;
      RECT 16.400 77.815 20.255 77.955 ;
      RECT 20.255 77.770 20.545 78.000 ;
      RECT 16.400 77.955 16.720 78.015 ;
      RECT 20.240 102.175 20.560 102.435 ;
      RECT 18.890 78.555 19.775 78.695 ;
      RECT 19.775 78.510 20.065 78.740 ;
      RECT 14.000 78.695 14.320 78.755 ;
      RECT 15.530 78.555 15.670 78.925 ;
      RECT 14.000 78.495 14.320 78.695 ;
      RECT 14.320 78.555 15.530 78.695 ;
      RECT 15.530 78.925 18.890 79.065 ;
      RECT 18.890 78.695 19.030 79.065 ;
      RECT 16.895 105.520 17.185 105.565 ;
      RECT 16.895 105.705 17.185 105.750 ;
      RECT 16.895 105.565 18.335 105.705 ;
      RECT 18.335 105.520 18.625 105.750 ;
      RECT 8.255 79.250 8.545 79.295 ;
      RECT 12.650 78.925 12.790 79.295 ;
      RECT 9.290 78.925 12.650 79.065 ;
      RECT 8.545 79.295 9.290 79.435 ;
      RECT 8.255 79.295 8.545 79.480 ;
      RECT 9.290 79.065 9.430 79.435 ;
      RECT 12.650 79.295 14.480 79.435 ;
      RECT 14.480 79.235 14.800 79.495 ;
      RECT 13.040 65.915 13.360 66.175 ;
      RECT 12.080 81.455 12.400 81.515 ;
      RECT 12.080 81.515 12.575 81.655 ;
      RECT 12.575 81.470 12.865 81.700 ;
      RECT 12.080 81.655 12.400 81.715 ;
      RECT 8.240 105.875 8.560 105.935 ;
      RECT 9.695 105.890 9.985 105.935 ;
      RECT 9.695 106.075 9.985 106.120 ;
      RECT 8.240 106.075 8.560 106.135 ;
      RECT 8.240 105.935 13.520 106.075 ;
      RECT 13.520 105.875 13.840 106.135 ;
      RECT 18.335 67.040 18.625 67.085 ;
      RECT 18.335 67.225 18.625 67.270 ;
      RECT 18.335 67.085 20.240 67.225 ;
      RECT 20.240 67.025 20.560 67.285 ;
      RECT 14.480 82.195 14.800 82.455 ;
      RECT 15.440 114.385 15.760 114.645 ;
      RECT 11.135 85.910 11.425 85.955 ;
      RECT 15.530 85.585 15.670 85.955 ;
      RECT 12.170 85.585 15.530 85.725 ;
      RECT 11.425 85.955 12.170 86.095 ;
      RECT 11.135 85.955 11.425 86.140 ;
      RECT 12.170 85.725 12.310 86.095 ;
      RECT 15.530 85.955 16.400 86.095 ;
      RECT 16.400 85.895 16.720 86.155 ;
      RECT 10.175 86.280 10.465 86.325 ;
      RECT 12.575 86.280 12.865 86.325 ;
      RECT 10.175 86.465 10.465 86.510 ;
      RECT 12.575 86.465 12.865 86.510 ;
      RECT 10.175 86.325 17.855 86.465 ;
      RECT 17.855 86.280 18.145 86.510 ;
      RECT 12.080 89.595 12.400 89.655 ;
      RECT 12.080 89.655 13.535 89.795 ;
      RECT 13.535 89.610 13.825 89.840 ;
      RECT 12.080 89.795 12.400 89.855 ;
      RECT 11.615 86.650 11.905 86.695 ;
      RECT 11.615 86.835 11.905 86.880 ;
      RECT 11.615 86.695 14.480 86.835 ;
      RECT 14.480 86.635 14.800 86.895 ;
      RECT 9.200 97.365 9.520 97.625 ;
      RECT 11.600 106.615 11.920 106.875 ;
      RECT 15.440 107.725 15.760 107.785 ;
      RECT 15.440 107.785 16.895 107.925 ;
      RECT 16.895 107.740 17.185 107.970 ;
      RECT 15.440 107.925 15.760 107.985 ;
      RECT 6.815 70.000 7.105 70.045 ;
      RECT 9.215 70.000 9.505 70.045 ;
      RECT 6.815 70.185 7.105 70.230 ;
      RECT 9.215 70.185 9.505 70.230 ;
      RECT 6.815 70.045 14.495 70.185 ;
      RECT 14.495 70.000 14.785 70.230 ;
      RECT 20.240 107.725 20.560 107.985 ;
      RECT 9.200 94.405 9.520 94.465 ;
      RECT 14.090 94.095 14.230 94.465 ;
      RECT 10.250 94.095 14.090 94.235 ;
      RECT 14.090 94.465 15.455 94.605 ;
      RECT 15.455 94.420 15.745 94.650 ;
      RECT 9.520 94.465 10.250 94.605 ;
      RECT 9.200 94.465 9.520 94.665 ;
      RECT 10.250 94.235 10.390 94.605 ;
      RECT 8.255 70.555 8.545 70.600 ;
      RECT 12.170 70.415 13.040 70.555 ;
      RECT 13.040 70.355 13.360 70.615 ;
      RECT 9.290 70.415 9.430 70.785 ;
      RECT 8.255 70.370 8.545 70.555 ;
      RECT 8.545 70.415 9.290 70.555 ;
      RECT 9.290 70.785 12.170 70.925 ;
      RECT 12.170 70.555 12.310 70.925 ;
      RECT 18.890 102.975 19.775 103.115 ;
      RECT 19.775 102.930 20.065 103.160 ;
      RECT 9.290 102.805 9.430 103.115 ;
      RECT 9.200 102.545 9.520 102.805 ;
      RECT 13.130 102.975 13.270 103.345 ;
      RECT 9.430 102.975 13.130 103.115 ;
      RECT 13.130 103.345 18.890 103.485 ;
      RECT 18.890 103.115 19.030 103.485 ;
      RECT 16.400 70.725 16.720 70.985 ;
      RECT 18.800 62.215 19.120 62.475 ;
      RECT 14.000 71.095 14.320 71.155 ;
      RECT 14.000 71.155 19.775 71.295 ;
      RECT 19.775 71.110 20.065 71.340 ;
      RECT 14.000 71.295 14.320 71.355 ;
      RECT 20.240 111.055 20.560 111.315 ;
      RECT 8.240 95.145 8.560 95.205 ;
      RECT 12.080 95.145 12.400 95.205 ;
      RECT 8.240 95.205 13.535 95.345 ;
      RECT 13.535 95.160 13.825 95.390 ;
      RECT 8.240 95.345 8.560 95.405 ;
      RECT 12.080 95.345 12.400 95.405 ;
      RECT 19.760 46.675 20.080 46.935 ;
      RECT 9.695 53.720 9.985 53.765 ;
      RECT 12.095 53.720 12.385 53.765 ;
      RECT 9.695 53.905 9.985 53.950 ;
      RECT 12.095 53.905 12.385 53.950 ;
      RECT 9.695 53.765 17.375 53.905 ;
      RECT 17.375 53.720 17.665 53.950 ;
      RECT 11.135 54.090 11.425 54.135 ;
      RECT 11.135 54.275 11.425 54.320 ;
      RECT 11.135 54.135 12.560 54.275 ;
      RECT 12.560 54.075 12.880 54.335 ;
      RECT 19.295 54.460 19.585 54.505 ;
      RECT 19.295 54.645 19.585 54.690 ;
      RECT 19.295 54.505 19.760 54.645 ;
      RECT 19.760 54.445 20.080 54.705 ;
      RECT 11.135 16.350 11.425 16.395 ;
      RECT 11.135 16.535 11.425 16.580 ;
      RECT 11.135 16.395 11.600 16.535 ;
      RECT 11.600 16.335 11.920 16.595 ;
      RECT 10.640 17.075 10.960 17.135 ;
      RECT 10.640 17.135 13.055 17.275 ;
      RECT 13.055 17.090 13.345 17.320 ;
      RECT 10.640 17.275 10.960 17.335 ;
      RECT 3.920 48.525 4.240 48.785 ;
      RECT 11.135 24.490 11.425 24.535 ;
      RECT 11.135 24.675 11.425 24.720 ;
      RECT 11.135 24.535 11.600 24.675 ;
      RECT 11.600 24.475 11.920 24.735 ;
      RECT 13.055 25.230 13.345 25.275 ;
      RECT 13.055 25.415 13.345 25.460 ;
      RECT 13.055 25.275 19.280 25.415 ;
      RECT 19.280 25.215 19.600 25.475 ;
      RECT 13.520 29.285 13.840 29.545 ;
      RECT 12.080 57.035 12.400 57.295 ;
      RECT 11.600 30.025 11.920 30.285 ;
      RECT 19.280 32.245 19.600 32.505 ;
      RECT 7.775 32.445 8.065 32.490 ;
      RECT 8.810 32.305 8.950 32.490 ;
      RECT 7.775 32.260 8.065 32.445 ;
      RECT 8.065 32.305 8.810 32.445 ;
      RECT 12.650 32.305 13.520 32.445 ;
      RECT 13.520 32.245 13.840 32.505 ;
      RECT 8.810 32.490 12.650 32.630 ;
      RECT 12.650 32.445 12.790 32.630 ;
      RECT 11.135 48.910 11.425 48.955 ;
      RECT 11.600 48.895 11.920 48.955 ;
      RECT 11.135 49.095 11.425 49.140 ;
      RECT 11.135 48.955 12.575 49.095 ;
      RECT 12.575 48.910 12.865 49.140 ;
      RECT 11.600 49.095 11.920 49.155 ;
      RECT 14.015 57.790 14.305 57.835 ;
      RECT 14.015 57.975 14.305 58.020 ;
      RECT 14.015 57.835 18.800 57.975 ;
      RECT 18.800 57.775 19.120 58.035 ;
      RECT 18.800 33.725 19.120 33.785 ;
      RECT 18.800 33.785 19.775 33.925 ;
      RECT 19.775 33.740 20.065 33.970 ;
      RECT 18.800 33.925 19.120 33.985 ;
      RECT 16.400 61.475 16.720 61.535 ;
      RECT 19.295 61.490 19.585 61.535 ;
      RECT 19.295 61.675 19.585 61.720 ;
      RECT 16.400 61.675 16.720 61.735 ;
      RECT 16.400 61.535 19.760 61.675 ;
      RECT 19.760 61.475 20.080 61.735 ;
      RECT 9.215 37.440 9.505 37.485 ;
      RECT 11.615 37.440 11.905 37.485 ;
      RECT 9.215 37.625 9.505 37.670 ;
      RECT 11.615 37.625 11.905 37.670 ;
      RECT 9.215 37.485 16.895 37.625 ;
      RECT 16.895 37.440 17.185 37.670 ;
      RECT 7.760 38.165 8.080 38.425 ;
      RECT 18.800 38.165 19.120 38.425 ;
      RECT 10.640 38.535 10.960 38.795 ;
      RECT 10.655 40.400 10.945 40.445 ;
      RECT 10.655 40.585 10.945 40.630 ;
      RECT 10.655 40.445 13.520 40.585 ;
      RECT 13.520 40.385 13.840 40.645 ;
      RECT 7.760 40.755 8.080 41.015 ;
      RECT 18.800 40.755 19.120 41.015 ;
      RECT 9.200 46.675 9.520 46.735 ;
      RECT 18.410 46.365 18.550 46.735 ;
      RECT 13.610 46.365 18.410 46.505 ;
      RECT 9.520 46.735 10.390 46.875 ;
      RECT 9.200 46.735 9.520 46.935 ;
      RECT 10.390 46.550 13.610 46.690 ;
      RECT 10.250 46.550 10.390 46.735 ;
      RECT 13.610 46.505 13.750 46.690 ;
      RECT 18.410 46.735 19.280 46.875 ;
      RECT 19.280 46.675 19.600 46.935 ;
      RECT 9.215 41.510 9.505 41.555 ;
      RECT 11.615 41.510 11.905 41.555 ;
      RECT 9.215 41.695 9.505 41.740 ;
      RECT 11.615 41.695 11.905 41.740 ;
      RECT 9.215 41.555 16.895 41.695 ;
      RECT 16.895 41.510 17.185 41.740 ;
      RECT 9.200 49.635 9.520 49.895 ;
      RECT 18.800 45.195 19.120 45.255 ;
      RECT 18.800 45.255 19.775 45.395 ;
      RECT 19.775 45.210 20.065 45.440 ;
      RECT 18.800 45.395 19.120 45.455 ;
      RECT 12.560 49.635 12.880 49.695 ;
      RECT 12.560 49.695 14.495 49.835 ;
      RECT 14.495 49.650 14.785 49.880 ;
      RECT 12.560 49.835 12.880 49.895 ;
      RECT 7.775 45.950 8.065 45.995 ;
      RECT 11.690 45.625 11.830 45.995 ;
      RECT 8.810 45.625 11.690 45.765 ;
      RECT 8.065 45.995 8.810 46.135 ;
      RECT 7.775 45.995 8.065 46.180 ;
      RECT 8.810 45.765 8.950 46.135 ;
      RECT 11.690 45.995 12.560 46.135 ;
      RECT 12.560 45.935 12.880 46.195 ;
      RECT 23.615 22.270 23.905 22.315 ;
      RECT 23.615 22.455 23.905 22.500 ;
      RECT 23.615 22.315 25.055 22.455 ;
      RECT 25.055 22.270 25.345 22.500 ;
      RECT 37.055 22.270 37.345 22.315 ;
      RECT 37.055 22.455 37.345 22.500 ;
      RECT 37.055 22.315 38.960 22.455 ;
      RECT 38.960 22.255 39.280 22.515 ;
      RECT 38.480 22.995 38.800 23.055 ;
      RECT 38.480 23.195 38.800 23.255 ;
      RECT 38.480 23.055 39.920 23.195 ;
      RECT 39.920 22.995 40.240 23.255 ;
      RECT 36.575 24.120 36.865 24.165 ;
      RECT 36.865 24.165 40.490 24.305 ;
      RECT 36.575 24.165 36.865 24.350 ;
      RECT 40.490 23.850 40.630 24.305 ;
      RECT 40.400 23.590 40.720 23.850 ;
      RECT 37.055 48.540 37.345 48.585 ;
      RECT 37.055 48.725 37.345 48.770 ;
      RECT 37.055 48.585 39.920 48.725 ;
      RECT 39.920 48.525 40.240 48.785 ;
      RECT 37.055 58.900 37.345 58.945 ;
      RECT 37.055 59.085 37.345 59.130 ;
      RECT 37.055 58.945 38.960 59.085 ;
      RECT 38.960 58.885 39.280 59.145 ;
      RECT 25.535 24.860 25.825 24.905 ;
      RECT 25.535 25.045 25.825 25.090 ;
      RECT 25.535 24.905 28.415 25.045 ;
      RECT 28.415 24.860 28.705 25.090 ;
      RECT 22.160 24.845 22.480 24.905 ;
      RECT 22.160 24.905 22.655 25.045 ;
      RECT 22.655 24.860 22.945 25.090 ;
      RECT 22.160 25.045 22.480 25.105 ;
      RECT 27.935 49.280 28.225 49.325 ;
      RECT 27.935 49.465 28.225 49.510 ;
      RECT 27.935 49.325 28.895 49.465 ;
      RECT 28.895 49.280 29.185 49.510 ;
      RECT 37.055 28.190 37.345 28.235 ;
      RECT 37.055 28.375 37.345 28.420 ;
      RECT 37.055 28.235 39.920 28.375 ;
      RECT 39.920 28.175 40.240 28.435 ;
      RECT 25.610 48.955 26.015 49.095 ;
      RECT 26.015 48.910 26.305 49.140 ;
      RECT 21.215 49.465 21.505 49.510 ;
      RECT 22.250 49.325 22.390 49.695 ;
      RECT 21.215 49.280 21.505 49.465 ;
      RECT 21.505 49.325 22.250 49.465 ;
      RECT 22.250 49.695 25.610 49.835 ;
      RECT 25.610 49.095 25.750 49.835 ;
      RECT 27.935 29.670 28.225 29.715 ;
      RECT 27.935 29.855 28.225 29.900 ;
      RECT 27.935 29.715 28.895 29.855 ;
      RECT 28.895 29.670 29.185 29.900 ;
      RECT 21.695 29.670 21.985 29.715 ;
      RECT 22.160 29.655 22.480 29.715 ;
      RECT 23.600 29.655 23.920 29.715 ;
      RECT 21.695 29.855 21.985 29.900 ;
      RECT 21.695 29.715 25.055 29.855 ;
      RECT 25.055 29.670 25.345 29.900 ;
      RECT 22.160 29.855 22.480 29.915 ;
      RECT 23.600 29.855 23.920 29.915 ;
      RECT 25.520 54.075 25.840 54.135 ;
      RECT 25.520 54.135 26.495 54.275 ;
      RECT 26.495 54.090 26.785 54.320 ;
      RECT 25.520 54.275 25.840 54.335 ;
      RECT 25.130 48.585 27.440 48.725 ;
      RECT 27.440 48.525 27.760 48.785 ;
      RECT 21.695 48.910 21.985 48.955 ;
      RECT 21.695 49.095 21.985 49.140 ;
      RECT 21.695 48.955 25.055 49.095 ;
      RECT 25.055 48.910 25.345 49.140 ;
      RECT 25.130 48.725 25.270 48.910 ;
      RECT 24.575 30.040 24.865 30.085 ;
      RECT 24.575 30.225 24.865 30.270 ;
      RECT 24.575 30.085 25.520 30.225 ;
      RECT 25.520 30.025 25.840 30.285 ;
      RECT 21.215 30.410 21.505 30.455 ;
      RECT 21.215 30.595 21.505 30.640 ;
      RECT 21.215 30.455 26.015 30.595 ;
      RECT 26.015 30.410 26.305 30.640 ;
      RECT 35.120 45.935 35.440 46.195 ;
      RECT 35.615 32.260 35.905 32.305 ;
      RECT 35.615 32.445 35.905 32.490 ;
      RECT 35.615 32.305 38.960 32.445 ;
      RECT 38.960 32.245 39.280 32.505 ;
      RECT 24.575 56.680 24.865 56.725 ;
      RECT 24.575 56.865 24.865 56.910 ;
      RECT 24.575 56.725 26.015 56.865 ;
      RECT 26.015 56.680 26.305 56.910 ;
      RECT 25.520 32.985 25.840 33.045 ;
      RECT 25.520 33.045 27.455 33.185 ;
      RECT 27.455 33.000 27.745 33.230 ;
      RECT 25.520 33.185 25.840 33.245 ;
      RECT 24.575 50.760 24.865 50.805 ;
      RECT 24.575 50.945 24.865 50.990 ;
      RECT 24.575 50.805 25.520 50.945 ;
      RECT 25.520 50.745 25.840 51.005 ;
      RECT 29.360 8.195 29.680 8.255 ;
      RECT 29.360 8.255 29.855 8.395 ;
      RECT 29.855 8.210 30.145 8.440 ;
      RECT 29.360 8.395 29.680 8.455 ;
      RECT 22.160 8.565 22.480 8.625 ;
      RECT 22.160 8.625 28.895 8.765 ;
      RECT 28.895 8.580 29.185 8.810 ;
      RECT 22.160 8.765 22.480 8.825 ;
      RECT 30.320 10.045 30.640 10.105 ;
      RECT 30.320 10.105 31.775 10.245 ;
      RECT 31.775 10.060 32.065 10.290 ;
      RECT 30.320 10.245 30.640 10.305 ;
      RECT 25.055 12.095 25.345 12.140 ;
      RECT 28.490 11.955 29.360 12.095 ;
      RECT 29.360 11.895 29.680 12.155 ;
      RECT 26.090 11.955 26.230 12.325 ;
      RECT 25.055 11.910 25.345 12.095 ;
      RECT 25.345 11.955 26.090 12.095 ;
      RECT 26.090 12.325 28.490 12.465 ;
      RECT 28.490 12.095 28.630 12.465 ;
      RECT 28.880 37.795 29.200 38.055 ;
      RECT 24.575 13.390 24.865 13.435 ;
      RECT 24.575 13.575 24.865 13.620 ;
      RECT 24.575 13.435 25.040 13.575 ;
      RECT 25.040 13.375 25.360 13.635 ;
      RECT 30.320 13.375 30.640 13.635 ;
      RECT 37.055 14.130 37.345 14.175 ;
      RECT 37.055 14.315 37.345 14.360 ;
      RECT 37.055 14.175 38.000 14.315 ;
      RECT 38.000 14.115 38.320 14.375 ;
      RECT 36.575 38.550 36.865 38.595 ;
      RECT 36.575 38.735 36.865 38.780 ;
      RECT 36.575 38.595 39.920 38.735 ;
      RECT 39.920 38.535 40.240 38.795 ;
      RECT 31.295 40.400 31.585 40.445 ;
      RECT 31.295 40.585 31.585 40.630 ;
      RECT 31.295 40.445 32.735 40.585 ;
      RECT 32.735 40.400 33.025 40.630 ;
      RECT 27.935 57.420 28.225 57.465 ;
      RECT 27.935 57.605 28.225 57.650 ;
      RECT 27.935 57.465 28.895 57.605 ;
      RECT 28.895 57.420 29.185 57.650 ;
      RECT 28.880 40.385 29.200 40.645 ;
      RECT 23.600 40.385 23.920 40.445 ;
      RECT 23.600 40.585 23.920 40.645 ;
      RECT 27.440 40.585 27.760 40.645 ;
      RECT 28.490 40.445 28.630 40.815 ;
      RECT 23.600 40.445 28.490 40.585 ;
      RECT 27.440 40.385 27.760 40.445 ;
      RECT 26.015 40.770 26.305 41.000 ;
      RECT 26.090 40.585 26.230 40.770 ;
      RECT 28.490 40.815 31.775 40.955 ;
      RECT 31.775 40.770 32.065 41.000 ;
      RECT 34.655 52.795 34.945 52.840 ;
      RECT 38.090 52.655 38.960 52.795 ;
      RECT 38.960 52.595 39.280 52.855 ;
      RECT 35.690 52.655 35.830 53.025 ;
      RECT 34.655 52.610 34.945 52.795 ;
      RECT 34.945 52.655 35.690 52.795 ;
      RECT 35.690 53.025 38.090 53.165 ;
      RECT 38.090 52.795 38.230 53.165 ;
      RECT 27.455 16.720 27.745 16.765 ;
      RECT 27.455 16.905 27.745 16.950 ;
      RECT 27.455 16.765 28.895 16.905 ;
      RECT 28.895 16.720 29.185 16.950 ;
      RECT 22.160 16.705 22.480 16.765 ;
      RECT 22.160 16.765 24.575 16.905 ;
      RECT 24.575 16.720 24.865 16.950 ;
      RECT 22.160 16.905 22.480 16.965 ;
      RECT 25.040 57.405 25.360 57.465 ;
      RECT 25.040 57.605 25.360 57.665 ;
      RECT 25.040 57.465 27.440 57.605 ;
      RECT 27.440 57.405 27.760 57.665 ;
      RECT 37.055 18.200 37.345 18.245 ;
      RECT 37.055 18.385 37.345 18.430 ;
      RECT 37.055 18.245 39.920 18.385 ;
      RECT 39.920 18.185 40.240 18.445 ;
      RECT 34.655 42.620 34.945 42.665 ;
      RECT 34.655 42.805 34.945 42.850 ;
      RECT 34.655 42.665 35.120 42.805 ;
      RECT 35.120 42.605 35.440 42.865 ;
      RECT 26.975 21.530 27.265 21.575 ;
      RECT 26.975 21.715 27.265 21.760 ;
      RECT 26.975 21.575 28.895 21.715 ;
      RECT 28.895 21.530 29.185 21.760 ;
      RECT 30.335 45.210 30.625 45.255 ;
      RECT 30.335 45.395 30.625 45.440 ;
      RECT 30.335 45.255 38.960 45.395 ;
      RECT 38.960 45.195 39.280 45.455 ;
      RECT 23.120 21.515 23.440 21.775 ;
      RECT 21.680 45.565 22.000 45.625 ;
      RECT 21.680 45.625 22.175 45.765 ;
      RECT 22.175 45.580 22.465 45.810 ;
      RECT 21.680 45.765 22.000 45.825 ;
      RECT 22.160 21.885 22.480 21.945 ;
      RECT 22.160 21.945 24.095 22.085 ;
      RECT 24.095 21.900 24.385 22.130 ;
      RECT 22.160 22.085 22.480 22.145 ;
    LAYER met2 ;
      RECT 8.270 224.615 8.530 224.935 ;
      RECT 8.330 221.975 8.470 224.615 ;
      RECT 8.270 221.655 8.530 221.975 ;
      RECT 25.130 220.125 25.270 220.775 ;
      RECT 25.070 219.805 25.330 220.125 ;
      RECT 25.270 224.335 25.750 224.475 ;
      RECT 25.610 220.775 25.750 224.335 ;
      RECT 25.270 220.635 25.750 220.775 ;
      RECT 25.130 224.335 25.270 224.985 ;
      RECT 25.070 224.985 25.330 225.305 ;
      RECT 23.630 228.315 23.890 228.635 ;
      RECT 23.690 226.555 23.830 228.315 ;
      RECT 23.210 222.115 23.690 222.255 ;
      RECT 23.210 222.255 23.350 226.555 ;
      RECT 23.210 226.555 23.690 226.695 ;
      RECT 23.690 220.125 23.830 222.255 ;
      RECT 23.630 219.805 23.890 220.125 ;
      RECT 23.690 217.535 23.830 219.805 ;
      RECT 23.630 217.215 23.890 217.535 ;
      RECT 23.690 216.565 23.830 217.215 ;
      RECT 23.210 212.125 23.690 212.265 ;
      RECT 23.210 212.265 23.350 216.565 ;
      RECT 23.210 216.565 23.690 216.705 ;
      RECT 23.690 211.615 23.830 212.265 ;
      RECT 23.630 211.295 23.890 211.615 ;
      RECT 20.330 219.755 20.470 224.475 ;
      RECT 19.310 233.495 19.570 233.815 ;
      RECT 19.370 229.375 19.510 233.495 ;
      RECT 19.310 229.055 19.570 229.375 ;
      RECT 19.510 228.035 20.950 228.175 ;
      RECT 19.370 228.035 19.510 229.055 ;
      RECT 20.810 224.475 20.950 228.035 ;
      RECT 20.470 224.335 20.950 224.475 ;
      RECT 20.270 219.435 20.530 219.755 ;
      RECT 20.330 217.535 20.470 219.435 ;
      RECT 20.270 217.215 20.530 217.535 ;
      RECT 20.330 209.395 20.470 217.215 ;
      RECT 20.270 209.075 20.530 209.395 ;
      RECT 20.330 201.255 20.470 209.075 ;
      RECT 20.270 200.935 20.530 201.255 ;
      RECT 20.330 193.485 20.470 200.935 ;
      RECT 20.270 193.165 20.530 193.485 ;
      RECT 20.330 184.975 20.470 193.165 ;
      RECT 20.270 184.655 20.530 184.975 ;
      RECT 20.330 177.205 20.470 184.655 ;
      RECT 20.270 176.885 20.530 177.205 ;
      RECT 22.250 248.385 22.870 248.525 ;
      RECT 22.250 248.525 22.390 249.775 ;
      RECT 22.730 232.705 22.870 248.385 ;
      RECT 22.190 249.775 22.450 250.095 ;
      RECT 22.250 250.095 22.390 257.175 ;
      RECT 22.190 257.175 22.450 257.495 ;
      RECT 22.670 232.385 22.930 232.705 ;
      RECT 22.730 228.265 22.870 232.385 ;
      RECT 22.670 227.945 22.930 228.265 ;
      RECT 22.730 227.435 22.870 227.945 ;
      RECT 22.250 221.375 22.730 221.515 ;
      RECT 22.250 221.515 22.390 227.295 ;
      RECT 22.250 227.295 22.870 227.435 ;
      RECT 22.730 220.865 22.870 221.515 ;
      RECT 22.670 220.545 22.930 220.865 ;
      RECT 12.110 260.505 12.370 260.595 ;
      RECT 11.630 314.895 11.890 315.215 ;
      RECT 11.690 307.075 11.830 314.895 ;
      RECT 11.630 306.755 11.890 307.075 ;
      RECT 11.690 298.935 11.830 306.755 ;
      RECT 11.630 298.615 11.890 298.935 ;
      RECT 11.690 292.415 11.830 298.615 ;
      RECT 11.210 269.105 12.170 269.245 ;
      RECT 11.210 269.245 11.350 282.335 ;
      RECT 12.170 268.965 12.310 269.245 ;
      RECT 11.150 282.335 11.410 282.655 ;
      RECT 11.210 282.655 11.350 292.415 ;
      RECT 11.210 292.415 11.690 292.555 ;
      RECT 12.110 268.645 12.370 268.965 ;
      RECT 12.170 260.825 12.310 268.645 ;
      RECT 12.370 260.595 13.270 260.735 ;
      RECT 13.130 252.685 13.270 260.595 ;
      RECT 13.070 252.365 13.330 252.685 ;
      RECT 13.130 244.545 13.270 252.365 ;
      RECT 13.070 244.225 13.330 244.545 ;
      RECT 13.130 236.405 13.270 244.225 ;
      RECT 12.110 260.595 12.370 260.825 ;
      RECT 13.070 236.085 13.330 236.405 ;
      RECT 13.130 225.675 13.270 236.085 ;
      RECT 13.070 225.355 13.330 225.675 ;
      RECT 13.130 218.925 13.270 225.355 ;
      RECT 12.650 211.985 12.790 218.785 ;
      RECT 12.650 218.785 13.270 218.925 ;
      RECT 12.590 211.665 12.850 211.985 ;
      RECT 12.650 203.845 12.790 211.665 ;
      RECT 12.590 203.525 12.850 203.845 ;
      RECT 12.650 200.795 12.790 203.525 ;
      RECT 12.170 195.705 12.310 200.655 ;
      RECT 12.170 200.655 12.790 200.795 ;
      RECT 12.110 195.385 12.370 195.705 ;
      RECT 12.170 187.565 12.310 195.385 ;
      RECT 12.110 187.245 12.370 187.565 ;
      RECT 12.170 179.425 12.310 187.245 ;
      RECT 12.110 179.105 12.370 179.425 ;
      RECT 11.690 162.175 12.170 162.315 ;
      RECT 11.690 162.315 11.830 162.825 ;
      RECT 11.630 162.825 11.890 163.145 ;
      RECT 11.690 163.145 11.830 163.795 ;
      RECT 11.830 170.315 12.790 170.455 ;
      RECT 12.650 163.795 12.790 170.315 ;
      RECT 11.830 163.655 12.790 163.795 ;
      RECT 11.690 170.315 11.830 170.965 ;
      RECT 11.630 170.965 11.890 171.285 ;
      RECT 11.690 171.285 11.830 171.795 ;
      RECT 12.310 174.755 12.790 174.895 ;
      RECT 12.650 171.935 12.790 174.755 ;
      RECT 11.690 171.795 12.790 171.935 ;
      RECT 12.170 174.755 12.310 179.105 ;
      RECT 12.170 156.765 12.310 162.315 ;
      RECT 11.690 152.415 11.830 156.625 ;
      RECT 11.630 152.095 11.890 152.415 ;
      RECT 11.690 146.865 11.830 152.095 ;
      RECT 11.630 146.545 11.890 146.865 ;
      RECT 11.690 138.725 11.830 146.545 ;
      RECT 11.630 138.405 11.890 138.725 ;
      RECT 11.690 156.625 12.310 156.765 ;
      RECT 2.570 217.905 2.710 440.785 ;
      RECT 2.510 217.585 2.770 217.905 ;
      RECT 2.570 440.785 3.870 440.925 ;
      RECT 10.730 323.725 10.870 324.375 ;
      RECT 10.670 323.405 10.930 323.725 ;
      RECT 10.870 329.785 11.350 329.925 ;
      RECT 11.210 324.375 11.350 329.785 ;
      RECT 10.870 324.235 11.350 324.375 ;
      RECT 10.730 329.785 10.870 330.435 ;
      RECT 10.670 330.435 10.930 330.755 ;
      RECT 10.730 330.755 10.870 333.395 ;
      RECT 10.670 333.395 10.930 333.715 ;
      RECT 39.950 333.395 40.210 333.715 ;
      RECT 40.010 329.750 40.150 333.395 ;
      RECT 19.850 322.245 19.990 322.895 ;
      RECT 19.790 321.925 20.050 322.245 ;
      RECT 19.850 318.915 19.990 321.925 ;
      RECT 19.790 318.595 20.050 318.915 ;
      RECT 19.990 326.825 20.470 326.965 ;
      RECT 20.330 322.895 20.470 326.825 ;
      RECT 19.990 322.755 20.470 322.895 ;
      RECT 19.850 326.825 19.990 333.765 ;
      RECT 19.790 333.765 20.050 334.085 ;
      RECT 22.190 334.135 22.450 334.455 ;
      RECT 22.250 331.865 22.390 334.135 ;
      RECT 22.190 331.545 22.450 331.865 ;
      RECT 7.310 334.505 7.570 334.595 ;
      RECT 7.370 337.925 7.990 338.065 ;
      RECT 7.370 338.065 7.510 338.575 ;
      RECT 7.850 335.335 7.990 337.925 ;
      RECT 7.310 338.575 7.570 338.895 ;
      RECT 7.570 334.595 8.810 334.735 ;
      RECT 8.810 333.995 8.950 334.735 ;
      RECT 7.370 334.825 7.510 335.335 ;
      RECT 7.310 334.595 7.570 334.825 ;
      RECT 7.370 335.335 7.850 335.475 ;
      RECT 8.330 333.115 8.470 333.855 ;
      RECT 8.330 333.855 8.950 333.995 ;
      RECT 8.470 314.615 8.950 314.755 ;
      RECT 8.810 310.405 8.950 314.615 ;
      RECT 8.750 310.085 9.010 310.405 ;
      RECT 8.810 293.755 8.950 310.085 ;
      RECT 8.750 293.435 9.010 293.755 ;
      RECT 8.810 277.105 8.950 293.435 ;
      RECT 8.750 276.785 9.010 277.105 ;
      RECT 8.810 274.515 8.950 276.785 ;
      RECT 8.750 274.195 9.010 274.515 ;
      RECT 8.810 273.685 8.950 274.195 ;
      RECT 7.850 269.105 8.810 269.245 ;
      RECT 7.850 269.245 7.990 273.545 ;
      RECT 7.850 273.545 8.950 273.685 ;
      RECT 8.810 266.375 8.950 269.245 ;
      RECT 8.750 266.055 9.010 266.375 ;
      RECT 8.330 314.615 8.470 317.205 ;
      RECT 7.850 318.685 8.810 318.825 ;
      RECT 7.850 318.825 7.990 333.115 ;
      RECT 7.850 333.115 8.330 333.255 ;
      RECT 8.810 318.175 8.950 318.825 ;
      RECT 8.750 317.855 9.010 318.175 ;
      RECT 8.810 317.345 8.950 317.855 ;
      RECT 8.330 317.205 8.950 317.345 ;
      RECT 8.810 265.405 9.430 265.545 ;
      RECT 8.810 265.545 8.950 266.055 ;
      RECT 9.290 258.145 9.430 265.405 ;
      RECT 8.810 257.125 8.950 258.005 ;
      RECT 8.810 258.005 9.430 258.145 ;
      RECT 8.750 256.805 9.010 257.125 ;
      RECT 9.430 337.185 9.910 337.325 ;
      RECT 9.770 331.495 9.910 337.185 ;
      RECT 9.710 331.175 9.970 331.495 ;
      RECT 9.770 325.945 9.910 331.175 ;
      RECT 9.710 325.625 9.970 325.945 ;
      RECT 9.290 341.255 9.430 341.905 ;
      RECT 8.810 338.665 9.290 338.805 ;
      RECT 8.810 338.805 8.950 341.255 ;
      RECT 8.810 341.255 9.290 341.395 ;
      RECT 9.290 337.185 9.430 338.805 ;
      RECT 9.230 341.905 9.490 342.225 ;
      RECT 9.770 322.755 10.390 322.895 ;
      RECT 9.770 322.895 9.910 325.625 ;
      RECT 10.250 316.975 10.390 322.755 ;
      RECT 9.770 315.215 9.910 316.835 ;
      RECT 9.770 316.835 10.390 316.975 ;
      RECT 9.710 314.895 9.970 315.215 ;
      RECT 23.350 341.255 23.830 341.395 ;
      RECT 23.690 340.515 23.830 341.255 ;
      RECT 22.730 334.965 23.690 335.105 ;
      RECT 22.730 335.105 22.870 340.515 ;
      RECT 22.730 340.515 23.690 340.655 ;
      RECT 23.690 334.455 23.830 335.105 ;
      RECT 23.630 334.135 23.890 334.455 ;
      RECT 23.690 331.125 23.830 334.135 ;
      RECT 23.630 330.805 23.890 331.125 ;
      RECT 23.210 341.255 23.350 341.905 ;
      RECT 23.150 341.905 23.410 342.225 ;
      RECT 23.210 342.225 23.350 347.085 ;
      RECT 23.150 347.085 23.410 347.405 ;
      RECT 23.210 347.405 23.350 350.045 ;
      RECT 23.150 350.045 23.410 350.365 ;
      RECT 23.210 353.835 23.350 354.485 ;
      RECT 22.730 350.875 23.210 351.015 ;
      RECT 22.730 351.015 22.870 353.835 ;
      RECT 22.730 353.835 23.210 353.975 ;
      RECT 23.210 350.365 23.350 351.015 ;
      RECT 23.150 354.485 23.410 354.805 ;
      RECT 1.070 345.630 1.330 345.925 ;
      RECT 1.060 345.260 1.340 345.630 ;
      RECT 3.940 347.090 4.220 347.460 ;
      RECT 3.950 347.085 4.210 347.090 ;
      RECT 22.190 347.825 22.450 348.145 ;
      RECT 22.250 347.175 22.390 347.825 ;
      RECT 21.770 344.585 22.250 344.725 ;
      RECT 21.770 344.725 21.910 347.175 ;
      RECT 21.770 347.175 22.250 347.315 ;
      RECT 22.250 344.075 22.390 344.725 ;
      RECT 22.190 343.755 22.450 344.075 ;
      RECT 40.010 344.075 40.150 348.910 ;
      RECT 39.950 343.755 40.210 344.075 ;
      RECT 39.050 348.145 39.190 349.765 ;
      RECT 38.990 347.825 39.250 348.145 ;
      RECT 39.050 349.765 39.660 349.905 ;
      RECT 5.870 349.675 6.130 349.995 ;
      RECT 5.930 348.145 6.070 349.675 ;
      RECT 5.870 348.070 6.130 348.145 ;
      RECT 5.860 347.700 6.140 348.070 ;
      RECT 12.590 349.675 12.850 349.995 ;
      RECT 12.650 338.525 12.790 349.675 ;
      RECT 12.590 338.205 12.850 338.525 ;
      RECT 12.650 335.195 12.790 338.205 ;
      RECT 12.590 334.875 12.850 335.195 ;
      RECT 1.070 350.115 1.330 350.365 ;
      RECT 1.060 349.745 1.340 350.115 ;
      RECT 9.230 350.415 9.490 350.735 ;
      RECT 9.290 347.405 9.430 350.415 ;
      RECT 9.230 347.085 9.490 347.405 ;
      RECT 39.920 350.815 40.240 350.830 ;
      RECT 1.060 350.750 1.340 351.120 ;
      RECT 25.550 353.745 25.810 354.065 ;
      RECT 25.610 350.365 25.750 353.745 ;
      RECT 25.550 350.045 25.810 350.365 ;
      RECT 39.050 350.505 39.660 350.645 ;
      RECT 39.050 350.645 39.190 353.745 ;
      RECT 38.990 353.745 39.250 354.065 ;
      RECT 5.870 354.780 6.130 354.805 ;
      RECT 5.860 354.410 6.140 354.780 ;
      RECT 14.510 342.645 14.770 342.965 ;
      RECT 14.570 340.005 14.710 342.645 ;
      RECT 14.510 339.685 14.770 340.005 ;
      RECT 14.570 335.935 14.710 339.685 ;
      RECT 14.510 335.615 14.770 335.935 ;
      RECT 17.390 354.855 17.650 355.175 ;
      RECT 17.450 350.735 17.590 354.855 ;
      RECT 17.390 350.415 17.650 350.735 ;
      RECT 17.450 340.005 17.590 350.415 ;
      RECT 17.390 339.685 17.650 340.005 ;
      RECT 1.070 356.000 1.330 356.285 ;
      RECT 1.060 355.630 1.340 356.000 ;
      RECT 5.450 353.835 5.930 353.975 ;
      RECT 5.450 353.975 5.590 355.965 ;
      RECT 5.930 352.950 6.070 353.975 ;
      RECT 5.390 355.965 5.650 356.285 ;
      RECT 5.860 352.580 6.140 352.950 ;
      RECT 5.930 350.735 6.070 352.580 ;
      RECT 5.870 350.415 6.130 350.735 ;
      RECT 1.070 357.830 1.330 358.135 ;
      RECT 1.060 357.460 1.340 357.830 ;
      RECT 13.070 358.555 13.330 358.875 ;
      RECT 13.130 355.545 13.270 358.555 ;
      RECT 13.070 355.225 13.330 355.545 ;
      RECT 8.330 348.145 8.470 350.875 ;
      RECT 8.270 347.825 8.530 348.145 ;
      RECT 8.330 350.875 8.750 351.015 ;
      RECT 8.810 355.175 8.950 355.315 ;
      RECT 8.750 354.855 9.010 355.175 ;
      RECT 8.810 351.105 8.950 354.855 ;
      RECT 8.750 350.785 9.010 351.105 ;
      RECT 9.230 358.925 9.490 359.245 ;
      RECT 9.290 355.455 9.430 358.925 ;
      RECT 8.810 355.315 9.430 355.455 ;
      RECT 3.940 359.290 4.220 359.660 ;
      RECT 4.010 358.875 4.150 359.290 ;
      RECT 3.950 358.555 4.210 358.875 ;
      RECT 7.310 361.885 7.570 362.205 ;
      RECT 7.370 360.355 7.510 361.885 ;
      RECT 7.310 360.035 7.570 360.355 ;
      RECT 12.590 361.885 12.850 362.205 ;
      RECT 12.650 359.245 12.790 361.885 ;
      RECT 12.590 358.925 12.850 359.245 ;
      RECT 25.070 361.885 25.330 362.205 ;
      RECT 25.130 358.875 25.270 361.885 ;
      RECT 25.070 358.555 25.330 358.875 ;
      RECT 5.860 362.340 6.140 362.710 ;
      RECT 5.870 362.255 6.130 362.340 ;
      RECT 16.430 363.735 16.690 364.055 ;
      RECT 16.490 355.915 16.630 363.735 ;
      RECT 16.430 355.595 16.690 355.915 ;
      RECT 16.490 349.165 16.630 355.595 ;
      RECT 16.010 343.475 16.490 343.615 ;
      RECT 16.010 343.615 16.150 349.025 ;
      RECT 16.010 349.025 16.630 349.165 ;
      RECT 16.490 342.965 16.630 343.615 ;
      RECT 16.430 342.645 16.690 342.965 ;
      RECT 1.060 364.170 1.340 364.540 ;
      RECT 1.070 364.105 1.330 364.170 ;
      RECT 8.750 365.955 9.010 366.275 ;
      RECT 8.810 359.525 8.950 365.955 ;
      RECT 8.330 356.425 8.810 356.565 ;
      RECT 8.330 356.565 8.470 359.385 ;
      RECT 8.330 359.385 8.950 359.525 ;
      RECT 8.810 355.915 8.950 356.565 ;
      RECT 8.750 355.595 9.010 355.915 ;
      RECT 27.530 355.545 27.670 356.195 ;
      RECT 27.470 355.225 27.730 355.545 ;
      RECT 27.670 363.085 28.150 363.225 ;
      RECT 28.010 356.195 28.150 363.085 ;
      RECT 27.670 356.055 28.150 356.195 ;
      RECT 27.530 363.085 27.670 363.735 ;
      RECT 27.470 363.735 27.730 364.055 ;
      RECT 27.530 364.055 27.670 365.955 ;
      RECT 27.470 365.955 27.730 366.275 ;
      RECT 32.270 366.695 32.530 367.015 ;
      RECT 32.330 364.425 32.470 366.695 ;
      RECT 32.270 364.105 32.530 364.425 ;
      RECT 40.010 360.355 40.150 369.330 ;
      RECT 39.950 360.035 40.210 360.355 ;
      RECT 39.050 368.495 39.190 370.115 ;
      RECT 38.990 368.175 39.250 368.495 ;
      RECT 39.050 370.115 39.660 370.255 ;
      RECT 12.590 370.025 12.850 370.345 ;
      RECT 12.650 363.315 12.790 370.025 ;
      RECT 12.590 362.995 12.850 363.315 ;
      RECT 15.530 370.115 16.150 370.255 ;
      RECT 15.530 370.255 15.670 370.765 ;
      RECT 16.010 366.925 16.150 370.115 ;
      RECT 15.530 364.195 15.670 366.785 ;
      RECT 15.530 366.785 16.150 366.925 ;
      RECT 15.470 370.765 15.730 371.085 ;
      RECT 15.050 350.505 15.530 350.645 ;
      RECT 15.050 350.645 15.190 364.195 ;
      RECT 15.050 364.195 15.530 364.335 ;
      RECT 15.530 349.995 15.670 350.645 ;
      RECT 15.470 349.675 15.730 349.995 ;
      RECT 19.310 372.470 19.570 372.565 ;
      RECT 19.300 372.100 19.580 372.470 ;
      RECT 11.210 351.475 11.350 352.125 ;
      RECT 11.150 351.155 11.410 351.475 ;
      RECT 11.210 347.405 11.350 351.155 ;
      RECT 11.150 347.085 11.410 347.405 ;
      RECT 11.350 358.275 11.830 358.415 ;
      RECT 11.690 352.125 11.830 358.275 ;
      RECT 11.350 351.985 11.830 352.125 ;
      RECT 11.210 358.275 11.350 370.855 ;
      RECT 11.350 373.445 11.830 373.585 ;
      RECT 11.690 370.995 11.830 373.445 ;
      RECT 11.210 370.855 11.830 370.995 ;
      RECT 11.210 373.445 11.350 374.095 ;
      RECT 11.150 374.095 11.410 374.415 ;
      RECT 25.070 374.095 25.330 374.415 ;
      RECT 25.130 371.825 25.270 374.095 ;
      RECT 25.070 371.505 25.330 371.825 ;
      RECT 39.950 374.095 40.210 374.415 ;
      RECT 40.010 373.150 40.150 374.095 ;
      RECT 14.570 371.825 14.710 373.445 ;
      RECT 14.510 371.505 14.770 371.825 ;
      RECT 14.570 367.385 14.710 371.505 ;
      RECT 14.510 367.065 14.770 367.385 ;
      RECT 14.710 377.515 15.190 377.655 ;
      RECT 15.050 373.585 15.190 377.515 ;
      RECT 14.570 373.445 15.190 373.585 ;
      RECT 14.570 377.515 14.710 378.165 ;
      RECT 14.510 378.165 14.770 378.485 ;
      RECT 27.470 378.165 27.730 378.485 ;
      RECT 27.530 375.155 27.670 378.165 ;
      RECT 27.470 374.835 27.730 375.155 ;
      RECT 30.830 378.165 31.090 378.485 ;
      RECT 30.890 371.825 31.030 378.165 ;
      RECT 30.830 371.505 31.090 371.825 ;
      RECT 11.210 375.525 11.350 376.175 ;
      RECT 11.150 375.205 11.410 375.525 ;
      RECT 11.350 378.995 11.830 379.135 ;
      RECT 11.690 376.175 11.830 378.995 ;
      RECT 11.350 376.035 11.830 376.175 ;
      RECT 11.210 378.995 11.350 379.645 ;
      RECT 11.150 379.645 11.410 379.965 ;
      RECT 22.190 380.015 22.450 380.335 ;
      RECT 22.250 374.785 22.390 380.015 ;
      RECT 22.190 374.465 22.450 374.785 ;
      RECT 22.250 366.275 22.390 374.465 ;
      RECT 22.190 365.955 22.450 366.275 ;
      RECT 17.930 364.565 18.410 364.705 ;
      RECT 17.930 364.705 18.070 382.235 ;
      RECT 18.410 363.315 18.550 364.705 ;
      RECT 17.870 382.235 18.130 382.555 ;
      RECT 18.350 362.995 18.610 363.315 ;
      RECT 18.410 355.315 18.890 355.455 ;
      RECT 18.410 355.455 18.550 362.995 ;
      RECT 18.890 352.865 19.030 355.455 ;
      RECT 18.410 352.215 18.550 352.725 ;
      RECT 18.410 352.725 19.030 352.865 ;
      RECT 18.350 351.895 18.610 352.215 ;
      RECT 38.990 382.235 39.250 382.555 ;
      RECT 39.050 374.695 39.190 382.235 ;
      RECT 38.570 371.595 39.050 371.735 ;
      RECT 38.570 371.735 38.710 374.555 ;
      RECT 38.570 374.555 39.190 374.695 ;
      RECT 39.050 370.855 39.660 370.995 ;
      RECT 39.050 370.995 39.190 371.735 ;
      RECT 9.770 366.785 10.390 366.925 ;
      RECT 9.770 366.925 9.910 371.225 ;
      RECT 10.250 351.105 10.390 366.785 ;
      RECT 10.190 350.785 10.450 351.105 ;
      RECT 10.250 338.895 10.390 350.785 ;
      RECT 10.190 338.575 10.450 338.895 ;
      RECT 9.770 378.255 9.910 378.995 ;
      RECT 9.290 372.705 10.250 372.845 ;
      RECT 9.290 372.845 9.430 378.255 ;
      RECT 9.290 378.255 9.770 378.395 ;
      RECT 10.250 372.195 10.390 372.845 ;
      RECT 10.190 371.875 10.450 372.195 ;
      RECT 10.250 371.365 10.390 371.875 ;
      RECT 9.770 371.225 10.390 371.365 ;
      RECT 10.190 382.605 10.450 382.925 ;
      RECT 10.250 380.335 10.390 382.605 ;
      RECT 10.190 380.015 10.450 380.335 ;
      RECT 10.250 379.135 10.390 380.015 ;
      RECT 9.770 378.995 10.390 379.135 ;
      RECT 25.070 386.305 25.330 386.625 ;
      RECT 25.130 383.295 25.270 386.305 ;
      RECT 25.070 382.975 25.330 383.295 ;
      RECT 16.910 375.205 17.170 375.525 ;
      RECT 17.870 387.785 18.130 388.105 ;
      RECT 17.930 384.775 18.070 387.785 ;
      RECT 17.870 384.455 18.130 384.775 ;
      RECT 17.930 382.695 18.070 384.455 ;
      RECT 16.490 376.035 16.970 376.175 ;
      RECT 16.490 376.175 16.630 382.695 ;
      RECT 16.490 382.695 17.930 382.835 ;
      RECT 16.970 375.525 17.110 376.175 ;
      RECT 25.610 379.965 25.750 382.695 ;
      RECT 25.550 379.645 25.810 379.965 ;
      RECT 25.610 376.635 25.750 379.645 ;
      RECT 25.550 376.315 25.810 376.635 ;
      RECT 25.750 387.505 25.990 387.645 ;
      RECT 25.850 382.835 25.990 387.505 ;
      RECT 25.610 382.695 25.990 382.835 ;
      RECT 25.610 387.505 25.750 388.155 ;
      RECT 25.550 388.155 25.810 388.475 ;
      RECT 13.130 370.855 13.750 370.995 ;
      RECT 13.130 370.995 13.270 373.955 ;
      RECT 13.610 366.645 13.750 370.855 ;
      RECT 13.550 366.325 13.810 366.645 ;
      RECT 13.610 364.055 13.750 366.325 ;
      RECT 13.550 363.735 13.810 364.055 ;
      RECT 13.550 390.375 13.810 390.695 ;
      RECT 13.610 378.765 13.750 390.375 ;
      RECT 12.650 375.295 13.610 375.435 ;
      RECT 12.650 375.435 12.790 378.625 ;
      RECT 12.650 378.625 13.750 378.765 ;
      RECT 13.610 374.785 13.750 375.435 ;
      RECT 13.550 374.465 13.810 374.785 ;
      RECT 13.610 373.955 13.750 374.465 ;
      RECT 13.270 373.815 13.750 373.955 ;
      RECT 18.890 378.995 19.370 379.135 ;
      RECT 18.890 379.135 19.030 379.645 ;
      RECT 18.830 379.645 19.090 379.965 ;
      RECT 18.890 379.965 19.030 380.615 ;
      RECT 19.030 386.765 19.990 386.905 ;
      RECT 19.850 380.615 19.990 386.765 ;
      RECT 19.030 380.475 19.990 380.615 ;
      RECT 18.890 386.765 19.030 390.375 ;
      RECT 18.830 390.375 19.090 390.695 ;
      RECT 19.370 375.805 19.510 379.135 ;
      RECT 18.890 375.155 19.030 375.665 ;
      RECT 18.830 374.835 19.090 375.155 ;
      RECT 18.890 375.665 19.510 375.805 ;
      RECT 28.910 390.375 29.170 390.695 ;
      RECT 28.970 388.105 29.110 390.375 ;
      RECT 28.910 387.785 29.170 388.105 ;
      RECT 27.530 380.335 27.670 380.985 ;
      RECT 27.470 380.015 27.730 380.335 ;
      RECT 27.670 387.135 28.150 387.275 ;
      RECT 28.010 380.985 28.150 387.135 ;
      RECT 27.670 380.845 28.150 380.985 ;
      RECT 27.530 387.135 27.670 388.155 ;
      RECT 27.470 388.155 27.730 388.475 ;
      RECT 27.530 388.475 27.670 390.745 ;
      RECT 27.470 390.745 27.730 391.065 ;
      RECT 40.010 388.845 40.150 392.310 ;
      RECT 39.950 388.525 40.210 388.845 ;
      RECT 39.050 392.915 39.190 393.330 ;
      RECT 39.190 393.190 39.660 393.330 ;
      RECT 38.990 392.595 39.250 392.915 ;
      RECT 27.950 394.445 28.210 394.765 ;
      RECT 28.010 391.435 28.150 394.445 ;
      RECT 27.950 391.115 28.210 391.435 ;
      RECT 39.050 393.830 39.660 393.970 ;
      RECT 39.050 393.970 39.190 394.445 ;
      RECT 38.990 394.445 39.250 394.765 ;
      RECT 12.590 395.925 12.850 396.245 ;
      RECT 12.650 391.805 12.790 395.925 ;
      RECT 12.590 391.485 12.850 391.805 ;
      RECT 12.650 388.845 12.790 391.485 ;
      RECT 12.590 388.525 12.850 388.845 ;
      RECT 21.230 395.925 21.490 396.015 ;
      RECT 21.490 396.015 21.910 396.155 ;
      RECT 21.770 390.695 21.910 396.015 ;
      RECT 21.710 390.375 21.970 390.695 ;
      RECT 21.230 398.515 21.490 398.835 ;
      RECT 21.290 396.245 21.430 398.515 ;
      RECT 21.230 396.015 21.490 396.245 ;
      RECT 28.430 398.515 28.690 398.835 ;
      RECT 28.490 396.245 28.630 398.515 ;
      RECT 28.430 395.925 28.690 396.245 ;
      RECT 39.950 398.515 40.210 398.835 ;
      RECT 40.010 394.850 40.150 398.515 ;
      RECT 10.190 398.885 10.450 399.205 ;
      RECT 10.250 391.065 10.390 398.885 ;
      RECT 10.190 390.745 10.450 391.065 ;
      RECT 28.910 402.585 29.170 402.905 ;
      RECT 28.970 399.575 29.110 402.585 ;
      RECT 28.910 399.255 29.170 399.575 ;
      RECT 12.110 404.065 12.370 404.385 ;
      RECT 12.170 402.675 12.310 404.065 ;
      RECT 11.210 399.945 11.350 402.675 ;
      RECT 11.150 399.625 11.410 399.945 ;
      RECT 11.210 402.675 12.170 402.815 ;
      RECT 11.210 396.985 11.350 399.625 ;
      RECT 11.150 396.665 11.410 396.985 ;
      RECT 22.190 404.065 22.450 404.385 ;
      RECT 22.250 401.055 22.390 404.065 ;
      RECT 22.190 400.735 22.450 401.055 ;
      RECT 7.790 404.435 8.050 404.755 ;
      RECT 7.850 396.615 7.990 404.435 ;
      RECT 7.790 396.295 8.050 396.615 ;
      RECT 7.850 388.475 7.990 396.295 ;
      RECT 7.790 388.155 8.050 388.475 ;
      RECT 7.850 380.105 8.470 380.245 ;
      RECT 7.850 380.245 7.990 382.605 ;
      RECT 7.790 382.605 8.050 382.925 ;
      RECT 7.850 382.925 7.990 388.155 ;
      RECT 8.330 379.225 8.470 380.105 ;
      RECT 8.270 378.905 8.530 379.225 ;
      RECT 8.330 372.195 8.470 378.905 ;
      RECT 8.270 371.875 8.530 372.195 ;
      RECT 7.310 406.655 7.570 406.975 ;
      RECT 7.370 405.125 7.510 406.655 ;
      RECT 7.310 404.805 7.570 405.125 ;
      RECT 17.390 406.655 17.650 406.975 ;
      RECT 17.450 399.945 17.590 406.655 ;
      RECT 17.390 399.625 17.650 399.945 ;
      RECT 25.550 410.725 25.810 411.045 ;
      RECT 25.610 407.345 25.750 410.725 ;
      RECT 25.550 407.025 25.810 407.345 ;
      RECT 28.910 410.725 29.170 411.045 ;
      RECT 28.970 404.385 29.110 410.725 ;
      RECT 28.910 404.065 29.170 404.385 ;
      RECT 40.010 405.125 40.150 412.730 ;
      RECT 39.950 404.805 40.210 405.125 ;
      RECT 37.070 412.945 37.330 413.265 ;
      RECT 37.130 409.195 37.270 412.945 ;
      RECT 37.070 408.875 37.330 409.195 ;
      RECT 39.050 412.525 39.190 414.885 ;
      RECT 38.990 412.205 39.250 412.525 ;
      RECT 39.050 414.885 39.660 415.025 ;
      RECT 8.810 379.965 8.950 383.575 ;
      RECT 8.750 379.645 9.010 379.965 ;
      RECT 8.950 390.095 9.430 390.235 ;
      RECT 9.290 383.575 9.430 390.095 ;
      RECT 8.950 383.435 9.430 383.575 ;
      RECT 8.810 390.095 8.950 399.715 ;
      RECT 8.950 404.895 9.430 405.035 ;
      RECT 9.290 399.855 9.430 404.895 ;
      RECT 8.810 399.715 9.430 399.855 ;
      RECT 8.810 404.895 8.950 414.795 ;
      RECT 8.750 414.795 9.010 415.115 ;
      RECT 28.910 418.865 29.170 419.185 ;
      RECT 28.970 412.525 29.110 418.865 ;
      RECT 28.910 412.205 29.170 412.525 ;
      RECT 39.950 418.865 40.210 419.185 ;
      RECT 40.010 416.550 40.150 418.865 ;
      RECT 22.190 420.345 22.450 420.665 ;
      RECT 22.250 415.115 22.390 420.345 ;
      RECT 22.190 414.795 22.450 415.115 ;
      RECT 12.590 420.715 12.850 421.035 ;
      RECT 12.650 412.895 12.790 420.715 ;
      RECT 12.590 412.575 12.850 412.895 ;
      RECT 12.650 399.205 12.790 412.575 ;
      RECT 12.590 398.885 12.850 399.205 ;
      RECT 25.130 391.435 25.270 392.085 ;
      RECT 25.070 391.115 25.330 391.435 ;
      RECT 25.270 395.275 25.750 395.415 ;
      RECT 25.610 392.085 25.750 395.275 ;
      RECT 25.270 391.945 25.750 392.085 ;
      RECT 25.130 399.205 25.270 399.715 ;
      RECT 25.070 398.885 25.330 399.205 ;
      RECT 25.130 396.245 25.270 398.885 ;
      RECT 25.070 395.925 25.330 396.245 ;
      RECT 25.130 395.275 25.270 395.925 ;
      RECT 25.270 403.415 25.750 403.555 ;
      RECT 25.610 399.855 25.750 403.415 ;
      RECT 25.130 399.715 25.750 399.855 ;
      RECT 25.130 415.485 25.270 415.995 ;
      RECT 25.070 415.165 25.330 415.485 ;
      RECT 25.130 412.525 25.270 415.165 ;
      RECT 25.070 412.205 25.330 412.525 ;
      RECT 25.130 407.345 25.270 412.205 ;
      RECT 25.070 407.025 25.330 407.345 ;
      RECT 25.130 404.385 25.270 407.025 ;
      RECT 25.070 404.065 25.330 404.385 ;
      RECT 25.130 403.415 25.270 404.065 ;
      RECT 25.270 420.065 25.750 420.205 ;
      RECT 25.610 416.135 25.750 420.065 ;
      RECT 25.130 415.995 25.750 416.135 ;
      RECT 25.130 420.065 25.270 420.715 ;
      RECT 25.070 420.715 25.330 421.035 ;
      RECT 14.510 422.935 14.770 423.255 ;
      RECT 14.570 412.155 14.710 422.935 ;
      RECT 14.510 411.835 14.770 412.155 ;
      RECT 14.570 409.195 14.710 411.835 ;
      RECT 14.510 408.875 14.770 409.195 ;
      RECT 27.950 422.935 28.210 423.255 ;
      RECT 28.010 420.665 28.150 422.935 ;
      RECT 27.950 420.345 28.210 420.665 ;
      RECT 38.990 422.935 39.250 423.255 ;
      RECT 39.050 419.325 39.190 422.935 ;
      RECT 38.570 416.365 39.050 416.505 ;
      RECT 38.570 416.505 38.710 419.325 ;
      RECT 38.570 419.325 39.050 419.465 ;
      RECT 39.050 415.625 39.660 415.765 ;
      RECT 39.050 415.765 39.190 416.505 ;
      RECT 27.470 427.005 27.730 427.325 ;
      RECT 27.530 423.625 27.670 427.005 ;
      RECT 27.470 423.305 27.730 423.625 ;
      RECT 35.630 427.005 35.890 427.325 ;
      RECT 35.690 423.995 35.830 427.005 ;
      RECT 35.630 423.675 35.890 423.995 ;
      RECT 17.870 427.745 18.130 427.835 ;
      RECT 18.130 427.835 18.550 427.975 ;
      RECT 18.410 423.625 18.550 427.835 ;
      RECT 18.350 423.305 18.610 423.625 ;
      RECT 18.410 416.595 18.550 423.305 ;
      RECT 18.350 416.275 18.610 416.595 ;
      RECT 17.870 427.835 18.130 428.065 ;
      RECT 18.410 414.145 19.030 414.285 ;
      RECT 18.410 414.285 18.550 416.275 ;
      RECT 18.890 408.455 19.030 414.145 ;
      RECT 18.830 408.135 19.090 408.455 ;
      RECT 18.890 405.125 19.030 408.135 ;
      RECT 18.830 404.805 19.090 405.125 ;
      RECT 7.370 427.465 7.990 427.605 ;
      RECT 7.370 427.605 7.510 428.115 ;
      RECT 7.850 423.765 7.990 427.465 ;
      RECT 7.370 423.255 7.510 423.765 ;
      RECT 7.310 422.935 7.570 423.255 ;
      RECT 7.370 420.295 7.510 422.935 ;
      RECT 7.310 419.975 7.570 420.295 ;
      RECT 7.370 423.765 7.850 423.905 ;
      RECT 7.310 428.115 7.570 428.435 ;
      RECT 18.350 431.075 18.610 431.395 ;
      RECT 18.410 428.435 18.550 431.075 ;
      RECT 18.350 428.115 18.610 428.435 ;
      RECT 7.310 431.445 7.570 431.765 ;
      RECT 7.370 429.175 7.510 431.445 ;
      RECT 7.310 428.855 7.570 429.175 ;
      RECT 20.330 387.505 20.750 387.645 ;
      RECT 20.750 387.415 21.010 387.735 ;
      RECT 20.810 382.925 20.950 387.415 ;
      RECT 20.750 382.605 21.010 382.925 ;
      RECT 20.810 423.625 20.950 424.135 ;
      RECT 20.750 423.305 21.010 423.625 ;
      RECT 20.810 416.225 20.950 423.305 ;
      RECT 20.750 415.905 21.010 416.225 ;
      RECT 20.810 410.445 20.950 415.905 ;
      RECT 20.950 431.165 21.430 431.305 ;
      RECT 21.290 424.275 21.430 431.165 ;
      RECT 20.810 424.135 21.430 424.275 ;
      RECT 20.810 431.165 20.950 431.815 ;
      RECT 20.750 431.815 21.010 432.135 ;
      RECT 20.330 407.345 20.470 410.445 ;
      RECT 20.270 407.025 20.530 407.345 ;
      RECT 20.330 404.755 20.470 407.025 ;
      RECT 20.270 404.435 20.530 404.755 ;
      RECT 20.330 399.115 20.470 404.435 ;
      RECT 20.330 410.445 20.810 410.585 ;
      RECT 19.850 396.385 20.330 396.525 ;
      RECT 19.850 396.525 19.990 398.975 ;
      RECT 19.850 398.975 20.470 399.115 ;
      RECT 20.330 395.875 20.470 396.525 ;
      RECT 20.270 395.555 20.530 395.875 ;
      RECT 20.330 387.645 20.470 395.555 ;
      RECT 23.630 431.815 23.890 432.135 ;
      RECT 23.690 428.435 23.830 431.815 ;
      RECT 23.630 428.115 23.890 428.435 ;
      RECT 23.690 427.465 23.830 428.115 ;
      RECT 23.210 424.135 23.690 424.275 ;
      RECT 23.210 424.275 23.350 427.465 ;
      RECT 23.210 427.465 23.690 427.605 ;
      RECT 23.690 423.625 23.830 424.275 ;
      RECT 23.630 423.305 23.890 423.625 ;
      RECT 23.690 421.035 23.830 423.305 ;
      RECT 23.630 420.715 23.890 421.035 ;
      RECT 40.010 433.615 40.150 435.710 ;
      RECT 39.950 433.295 40.210 433.615 ;
      RECT 15.050 423.395 16.010 423.535 ;
      RECT 15.050 423.535 15.190 433.295 ;
      RECT 16.010 415.855 16.150 423.535 ;
      RECT 14.990 433.295 15.250 433.615 ;
      RECT 15.050 433.615 15.190 436.255 ;
      RECT 14.990 436.255 15.250 436.575 ;
      RECT 15.950 415.535 16.210 415.855 ;
      RECT 22.670 436.625 22.930 436.945 ;
      RECT 22.730 431.395 22.870 436.625 ;
      RECT 22.670 431.075 22.930 431.395 ;
      RECT 25.130 432.135 25.270 432.785 ;
      RECT 25.070 431.815 25.330 432.135 ;
      RECT 25.270 436.345 25.750 436.485 ;
      RECT 25.610 432.785 25.750 436.345 ;
      RECT 25.270 432.645 25.750 432.785 ;
      RECT 25.130 436.345 25.270 436.995 ;
      RECT 25.070 436.995 25.330 437.315 ;
      RECT 12.170 432.135 12.310 440.785 ;
      RECT 12.110 431.815 12.370 432.135 ;
      RECT 12.170 429.175 12.310 431.815 ;
      RECT 12.110 428.855 12.370 429.175 ;
      RECT 20.330 437.685 20.470 440.785 ;
      RECT 20.270 437.365 20.530 437.685 ;
      RECT 20.330 432.275 20.470 437.365 ;
      RECT 19.850 429.175 19.990 432.275 ;
      RECT 19.790 428.855 20.050 429.175 ;
      RECT 19.850 421.035 19.990 428.855 ;
      RECT 19.790 420.715 20.050 421.035 ;
      RECT 19.850 432.275 20.330 432.415 ;
      RECT 28.490 437.315 28.630 440.785 ;
      RECT 28.430 436.995 28.690 437.315 ;
      RECT 36.650 433.245 36.790 440.785 ;
      RECT 36.590 432.925 36.850 433.245 ;
      RECT 7.370 293.015 7.510 293.665 ;
      RECT 7.310 292.695 7.570 293.015 ;
      RECT 7.370 291.165 7.510 292.695 ;
      RECT 7.310 290.845 7.570 291.165 ;
      RECT 7.510 297.225 7.990 297.365 ;
      RECT 7.850 293.665 7.990 297.225 ;
      RECT 7.510 293.525 7.990 293.665 ;
      RECT 7.370 297.225 7.510 297.875 ;
      RECT 7.310 297.875 7.570 298.195 ;
      RECT 18.830 300.835 19.090 301.155 ;
      RECT 18.890 298.195 19.030 300.835 ;
      RECT 18.830 297.875 19.090 298.195 ;
      RECT 18.890 295.235 19.030 297.875 ;
      RECT 18.830 294.915 19.090 295.235 ;
      RECT 19.790 300.835 20.050 301.155 ;
      RECT 18.890 293.385 19.030 294.635 ;
      RECT 18.830 293.065 19.090 293.385 ;
      RECT 18.890 291.165 19.030 293.065 ;
      RECT 18.830 290.845 19.090 291.165 ;
      RECT 18.890 277.105 19.030 290.845 ;
      RECT 18.830 276.785 19.090 277.105 ;
      RECT 19.990 300.185 20.470 300.325 ;
      RECT 20.330 294.775 20.470 300.185 ;
      RECT 18.890 294.635 20.470 294.775 ;
      RECT 19.850 300.185 19.990 300.835 ;
      RECT 23.150 300.835 23.410 301.155 ;
      RECT 23.210 299.305 23.350 300.835 ;
      RECT 23.150 298.985 23.410 299.305 ;
      RECT 21.710 301.205 21.970 301.525 ;
      RECT 21.770 293.755 21.910 301.205 ;
      RECT 21.710 293.435 21.970 293.755 ;
      RECT 21.770 290.795 21.910 293.435 ;
      RECT 21.710 290.475 21.970 290.795 ;
      RECT 40.010 303.375 40.150 305.510 ;
      RECT 39.950 303.055 40.210 303.375 ;
      RECT 39.050 305.735 39.190 306.390 ;
      RECT 39.050 306.390 39.660 306.530 ;
      RECT 38.570 302.775 39.050 302.915 ;
      RECT 38.570 302.915 38.710 305.735 ;
      RECT 38.570 305.735 39.050 305.875 ;
      RECT 39.050 299.305 39.190 302.915 ;
      RECT 38.990 298.985 39.250 299.305 ;
      RECT 39.920 306.785 40.240 306.790 ;
      RECT 13.550 308.975 13.810 309.295 ;
      RECT 13.610 306.335 13.750 308.975 ;
      RECT 13.550 306.015 13.810 306.335 ;
      RECT 13.610 303.375 13.750 306.015 ;
      RECT 13.550 303.055 13.810 303.375 ;
      RECT 39.950 308.975 40.210 309.295 ;
      RECT 40.010 308.050 40.150 308.975 ;
      RECT 23.630 309.715 23.890 310.035 ;
      RECT 23.690 307.445 23.830 309.715 ;
      RECT 23.630 307.125 23.890 307.445 ;
      RECT 35.630 313.045 35.890 313.365 ;
      RECT 35.690 310.035 35.830 313.045 ;
      RECT 35.630 309.715 35.890 310.035 ;
      RECT 19.790 227.575 20.050 227.895 ;
      RECT 19.850 224.935 19.990 227.575 ;
      RECT 19.790 224.615 20.050 224.935 ;
      RECT 31.790 314.895 32.050 315.215 ;
      RECT 31.850 311.515 31.990 314.895 ;
      RECT 31.790 311.195 32.050 311.515 ;
      RECT 19.310 317.115 19.570 317.435 ;
      RECT 19.370 314.475 19.510 317.115 ;
      RECT 19.310 314.155 19.570 314.475 ;
      RECT 19.370 311.515 19.510 314.155 ;
      RECT 19.310 311.195 19.570 311.515 ;
      RECT 28.910 317.855 29.170 318.175 ;
      RECT 28.970 315.215 29.110 317.855 ;
      RECT 28.910 314.895 29.170 315.215 ;
      RECT 14.990 318.595 15.250 318.915 ;
      RECT 15.050 310.775 15.190 318.595 ;
      RECT 14.990 310.455 15.250 310.775 ;
      RECT 15.050 301.525 15.190 310.455 ;
      RECT 14.990 301.205 15.250 301.525 ;
      RECT 21.710 322.295 21.970 322.615 ;
      RECT 21.770 318.545 21.910 322.295 ;
      RECT 21.710 318.225 21.970 318.545 ;
      RECT 37.070 322.665 37.330 322.985 ;
      RECT 37.130 315.585 37.270 322.665 ;
      RECT 37.070 315.265 37.330 315.585 ;
      RECT 40.010 323.725 40.150 325.930 ;
      RECT 39.950 323.405 40.210 323.725 ;
      RECT 25.550 325.995 25.810 326.315 ;
      RECT 25.610 323.725 25.750 325.995 ;
      RECT 25.550 323.405 25.810 323.725 ;
      RECT 27.950 325.995 28.210 326.315 ;
      RECT 28.010 323.725 28.150 325.995 ;
      RECT 27.950 323.405 28.210 323.725 ;
      RECT 18.830 326.365 19.090 326.685 ;
      RECT 18.890 322.985 19.030 326.365 ;
      RECT 18.830 322.665 19.090 322.985 ;
      RECT 18.890 319.655 19.030 322.665 ;
      RECT 18.830 319.335 19.090 319.655 ;
      RECT 39.050 326.085 39.190 326.810 ;
      RECT 39.050 326.810 39.660 326.950 ;
      RECT 38.570 323.125 39.050 323.265 ;
      RECT 38.570 323.265 38.710 326.085 ;
      RECT 38.570 326.085 39.050 326.225 ;
      RECT 39.050 319.655 39.190 323.265 ;
      RECT 38.990 319.335 39.250 319.655 ;
      RECT 16.910 329.325 17.170 329.645 ;
      RECT 16.970 326.315 17.110 329.325 ;
      RECT 16.910 325.995 17.170 326.315 ;
      RECT 39.050 328.305 39.660 328.445 ;
      RECT 39.050 328.445 39.190 329.325 ;
      RECT 38.990 329.325 39.250 329.645 ;
      RECT 25.070 265.915 25.330 266.005 ;
      RECT 25.130 330.525 25.750 330.665 ;
      RECT 25.130 330.665 25.270 331.175 ;
      RECT 25.610 326.965 25.750 330.525 ;
      RECT 25.130 322.985 25.270 326.825 ;
      RECT 25.130 326.825 25.750 326.965 ;
      RECT 25.070 331.175 25.330 331.495 ;
      RECT 25.130 322.015 25.750 322.155 ;
      RECT 25.130 322.155 25.270 322.665 ;
      RECT 25.070 322.665 25.330 322.985 ;
      RECT 25.610 321.275 25.990 321.415 ;
      RECT 25.610 321.415 25.750 322.015 ;
      RECT 25.850 316.235 25.990 321.275 ;
      RECT 25.610 315.495 25.750 316.095 ;
      RECT 25.610 316.095 25.990 316.235 ;
      RECT 25.130 314.845 25.270 315.355 ;
      RECT 25.070 314.525 25.330 314.845 ;
      RECT 25.130 315.355 25.750 315.495 ;
      RECT 25.130 313.875 25.750 314.015 ;
      RECT 25.130 314.015 25.270 314.525 ;
      RECT 25.610 313.135 25.990 313.275 ;
      RECT 25.610 313.275 25.750 313.875 ;
      RECT 25.850 308.095 25.990 313.135 ;
      RECT 25.610 307.355 25.750 307.955 ;
      RECT 25.610 307.955 25.990 308.095 ;
      RECT 25.130 305.735 25.610 305.875 ;
      RECT 25.130 305.875 25.270 306.385 ;
      RECT 25.070 306.385 25.330 306.705 ;
      RECT 25.130 306.705 25.270 307.215 ;
      RECT 25.130 307.215 25.750 307.355 ;
      RECT 25.610 302.175 25.750 305.875 ;
      RECT 25.130 297.595 25.610 297.735 ;
      RECT 25.130 297.735 25.270 298.245 ;
      RECT 25.070 298.245 25.330 298.565 ;
      RECT 25.130 298.565 25.270 301.205 ;
      RECT 25.070 301.205 25.330 301.525 ;
      RECT 25.130 301.525 25.270 302.035 ;
      RECT 25.130 302.035 25.750 302.175 ;
      RECT 25.610 294.035 25.750 297.735 ;
      RECT 25.130 289.455 25.610 289.595 ;
      RECT 25.130 289.595 25.270 290.105 ;
      RECT 25.070 290.105 25.330 290.425 ;
      RECT 25.130 290.425 25.270 293.065 ;
      RECT 25.070 293.065 25.330 293.385 ;
      RECT 25.130 293.385 25.270 293.895 ;
      RECT 25.130 293.895 25.750 294.035 ;
      RECT 25.610 285.895 25.750 289.595 ;
      RECT 25.130 282.425 25.610 282.565 ;
      RECT 25.130 282.565 25.270 284.925 ;
      RECT 25.070 284.925 25.330 285.245 ;
      RECT 25.130 285.245 25.270 285.755 ;
      RECT 25.130 285.755 25.750 285.895 ;
      RECT 25.130 252.085 25.750 252.225 ;
      RECT 25.130 252.225 25.270 252.735 ;
      RECT 25.610 241.585 25.750 252.085 ;
      RECT 25.070 252.735 25.330 253.055 ;
      RECT 25.130 253.055 25.270 253.705 ;
      RECT 25.550 241.265 25.810 241.585 ;
      RECT 25.130 260.825 25.270 261.335 ;
      RECT 25.070 260.505 25.330 260.825 ;
      RECT 25.130 257.865 25.270 260.505 ;
      RECT 25.070 257.545 25.330 257.865 ;
      RECT 25.130 256.895 25.750 257.035 ;
      RECT 25.130 257.035 25.270 257.545 ;
      RECT 25.610 253.705 25.750 256.895 ;
      RECT 25.270 253.565 25.750 253.705 ;
      RECT 25.270 265.035 25.750 265.175 ;
      RECT 25.610 261.475 25.750 265.035 ;
      RECT 25.130 261.335 25.750 261.475 ;
      RECT 25.130 265.035 25.270 265.685 ;
      RECT 25.070 265.685 25.330 265.775 ;
      RECT 25.610 236.775 25.750 241.265 ;
      RECT 25.550 236.455 25.810 236.775 ;
      RECT 25.610 233.815 25.750 236.455 ;
      RECT 25.550 233.495 25.810 233.815 ;
      RECT 25.610 277.105 25.750 282.565 ;
      RECT 25.550 276.785 25.810 277.105 ;
      RECT 25.610 274.515 25.750 276.785 ;
      RECT 25.550 274.195 25.810 274.515 ;
      RECT 25.610 268.965 25.750 274.195 ;
      RECT 25.550 268.645 25.810 268.965 ;
      RECT 25.610 265.915 25.750 268.645 ;
      RECT 25.070 265.775 25.750 265.915 ;
      RECT 27.470 331.175 27.730 331.495 ;
      RECT 27.530 327.795 27.670 331.175 ;
      RECT 27.470 327.475 27.730 327.795 ;
      RECT 31.310 227.575 31.570 227.895 ;
      RECT 31.370 226.045 31.510 227.575 ;
      RECT 31.310 225.725 31.570 226.045 ;
      RECT 18.350 235.715 18.610 236.035 ;
      RECT 18.410 234.185 18.550 235.715 ;
      RECT 18.350 233.865 18.610 234.185 ;
      RECT 27.470 236.455 27.730 236.775 ;
      RECT 27.530 234.185 27.670 236.455 ;
      RECT 27.470 233.865 27.730 234.185 ;
      RECT 32.750 236.455 33.010 236.775 ;
      RECT 32.810 233.815 32.950 236.455 ;
      RECT 32.750 233.495 33.010 233.815 ;
      RECT 11.150 236.825 11.410 237.145 ;
      RECT 11.210 233.445 11.350 236.825 ;
      RECT 11.150 233.125 11.410 233.445 ;
      RECT 11.210 230.115 11.350 233.125 ;
      RECT 11.150 229.795 11.410 230.115 ;
      RECT 40.010 237.515 40.150 239.130 ;
      RECT 39.950 237.195 40.210 237.515 ;
      RECT 39.050 238.255 39.190 240.010 ;
      RECT 38.990 237.935 39.250 238.255 ;
      RECT 39.050 240.010 39.660 240.150 ;
      RECT 8.750 241.265 9.010 241.585 ;
      RECT 8.810 238.255 8.950 241.265 ;
      RECT 8.750 237.935 9.010 238.255 ;
      RECT 17.870 243.855 18.130 244.175 ;
      RECT 17.930 241.585 18.070 243.855 ;
      RECT 17.870 241.265 18.130 241.585 ;
      RECT 17.930 236.035 18.070 241.265 ;
      RECT 17.870 235.715 18.130 236.035 ;
      RECT 39.050 241.930 39.660 242.070 ;
      RECT 39.050 242.070 39.190 243.855 ;
      RECT 38.990 243.855 39.250 244.175 ;
      RECT 39.950 247.925 40.210 248.245 ;
      RECT 40.010 242.950 40.150 247.925 ;
      RECT 19.790 249.405 20.050 249.725 ;
      RECT 19.850 245.285 19.990 249.405 ;
      RECT 19.790 244.965 20.050 245.285 ;
      RECT 19.850 233.445 19.990 244.965 ;
      RECT 19.790 233.125 20.050 233.445 ;
      RECT 27.950 251.995 28.210 252.315 ;
      RECT 28.010 244.915 28.150 251.995 ;
      RECT 27.950 244.595 28.210 244.915 ;
      RECT 34.190 251.995 34.450 252.315 ;
      RECT 34.250 249.725 34.390 251.995 ;
      RECT 34.190 249.405 34.450 249.725 ;
      RECT 8.270 253.105 8.530 253.425 ;
      RECT 8.330 250.465 8.470 253.105 ;
      RECT 8.270 250.145 8.530 250.465 ;
      RECT 35.150 227.575 35.410 227.895 ;
      RECT 35.210 225.305 35.350 227.575 ;
      RECT 35.150 224.985 35.410 225.305 ;
      RECT 19.310 257.545 19.570 257.865 ;
      RECT 19.370 253.425 19.510 257.545 ;
      RECT 19.310 253.105 19.570 253.425 ;
      RECT 23.630 260.135 23.890 260.455 ;
      RECT 23.690 258.605 23.830 260.135 ;
      RECT 23.630 258.285 23.890 258.605 ;
      RECT 39.050 258.605 39.190 262.815 ;
      RECT 38.990 258.285 39.250 258.605 ;
      RECT 39.050 262.815 39.660 262.955 ;
      RECT 7.790 265.685 8.050 266.005 ;
      RECT 7.850 261.565 7.990 265.685 ;
      RECT 7.790 261.245 8.050 261.565 ;
      RECT 7.850 258.605 7.990 261.245 ;
      RECT 7.790 258.285 8.050 258.605 ;
      RECT 11.150 266.425 11.410 266.745 ;
      RECT 11.210 265.775 11.350 266.425 ;
      RECT 10.730 260.225 11.210 260.365 ;
      RECT 10.730 260.365 10.870 265.775 ;
      RECT 10.730 265.775 11.210 265.915 ;
      RECT 11.210 258.235 11.350 260.365 ;
      RECT 11.150 257.915 11.410 258.235 ;
      RECT 11.210 250.095 11.350 257.915 ;
      RECT 11.150 249.775 11.410 250.095 ;
      RECT 11.210 237.425 11.350 249.775 ;
      RECT 10.730 234.185 10.870 237.285 ;
      RECT 10.670 233.865 10.930 234.185 ;
      RECT 10.730 237.285 11.350 237.425 ;
      RECT 39.050 263.630 39.660 263.770 ;
      RECT 39.050 263.770 39.190 268.275 ;
      RECT 38.990 268.275 39.250 268.595 ;
      RECT 17.870 269.385 18.130 269.705 ;
      RECT 17.930 266.745 18.070 269.385 ;
      RECT 17.870 266.425 18.130 266.745 ;
      RECT 25.070 269.385 25.330 269.705 ;
      RECT 25.130 266.745 25.270 269.385 ;
      RECT 25.070 266.425 25.330 266.745 ;
      RECT 12.110 273.825 12.370 274.145 ;
      RECT 12.170 269.705 12.310 273.825 ;
      RECT 12.110 269.385 12.370 269.705 ;
      RECT 14.990 273.825 15.250 274.145 ;
      RECT 15.050 270.815 15.190 273.825 ;
      RECT 14.990 270.495 15.250 270.815 ;
      RECT 9.710 276.415 9.970 276.735 ;
      RECT 9.770 273.035 9.910 276.415 ;
      RECT 9.710 272.715 9.970 273.035 ;
      RECT 9.770 269.705 9.910 272.715 ;
      RECT 9.710 269.385 9.970 269.705 ;
      RECT 27.470 276.415 27.730 276.735 ;
      RECT 27.530 274.145 27.670 276.415 ;
      RECT 27.470 273.825 27.730 274.145 ;
      RECT 13.130 266.745 13.270 267.395 ;
      RECT 13.070 266.425 13.330 266.745 ;
      RECT 13.270 273.545 13.750 273.685 ;
      RECT 13.610 267.395 13.750 273.545 ;
      RECT 13.270 267.255 13.750 267.395 ;
      RECT 13.130 273.545 13.270 274.195 ;
      RECT 13.070 274.195 13.330 274.515 ;
      RECT 13.130 274.515 13.270 276.785 ;
      RECT 13.070 276.785 13.330 277.105 ;
      RECT 35.630 277.155 35.890 277.475 ;
      RECT 35.690 274.885 35.830 277.155 ;
      RECT 35.630 274.565 35.890 274.885 ;
      RECT 28.910 281.965 29.170 282.285 ;
      RECT 28.970 278.955 29.110 281.965 ;
      RECT 28.910 278.635 29.170 278.955 ;
      RECT 39.050 278.955 39.190 283.410 ;
      RECT 38.990 278.635 39.250 278.955 ;
      RECT 39.050 283.410 39.660 283.550 ;
      RECT 38.090 281.545 38.230 284.050 ;
      RECT 38.030 281.225 38.290 281.545 ;
      RECT 38.090 284.050 39.660 284.190 ;
      RECT 27.470 284.555 27.730 284.875 ;
      RECT 27.530 282.285 27.670 284.555 ;
      RECT 27.470 281.965 27.730 282.285 ;
      RECT 20.270 285.295 20.530 285.615 ;
      RECT 20.330 284.875 20.470 285.295 ;
      RECT 20.270 284.555 20.530 284.875 ;
      RECT 20.330 283.025 20.470 284.555 ;
      RECT 20.270 282.705 20.530 283.025 ;
      RECT 39.950 288.625 40.210 288.945 ;
      RECT 40.010 286.350 40.150 288.625 ;
      RECT 13.070 290.105 13.330 290.425 ;
      RECT 13.130 281.915 13.270 290.105 ;
      RECT 13.070 281.595 13.330 281.915 ;
      RECT 13.130 278.955 13.270 281.595 ;
      RECT 13.070 278.635 13.330 278.955 ;
      RECT 38.990 292.695 39.250 293.015 ;
      RECT 39.050 289.085 39.190 292.695 ;
      RECT 38.570 286.125 39.050 286.265 ;
      RECT 38.570 286.265 38.710 289.085 ;
      RECT 38.570 289.085 39.050 289.225 ;
      RECT 39.050 285.385 39.660 285.525 ;
      RECT 39.050 285.525 39.190 286.265 ;
      RECT 23.630 296.765 23.890 297.085 ;
      RECT 23.690 296.115 23.830 296.765 ;
      RECT 23.210 293.525 23.690 293.665 ;
      RECT 23.210 293.665 23.350 296.115 ;
      RECT 23.210 296.115 23.690 296.255 ;
      RECT 23.690 293.015 23.830 293.665 ;
      RECT 23.630 292.695 23.890 293.015 ;
      RECT 23.690 290.425 23.830 292.695 ;
      RECT 23.630 290.105 23.890 290.425 ;
      RECT 29.870 233.125 30.130 233.445 ;
      RECT 29.930 228.635 30.070 233.125 ;
      RECT 29.870 228.315 30.130 228.635 ;
      RECT 39.050 111.730 39.660 111.870 ;
      RECT 39.050 111.870 39.190 117.685 ;
      RECT 38.990 117.685 39.250 118.005 ;
      RECT 11.690 106.905 11.830 107.555 ;
      RECT 11.630 106.585 11.890 106.905 ;
      RECT 11.690 103.945 11.830 106.585 ;
      RECT 11.630 103.625 11.890 103.945 ;
      RECT 11.830 118.515 12.310 118.655 ;
      RECT 12.170 107.555 12.310 118.515 ;
      RECT 11.830 107.415 12.310 107.555 ;
      RECT 11.690 118.515 11.830 119.165 ;
      RECT 11.630 119.165 11.890 119.485 ;
      RECT 19.370 111.485 19.510 119.535 ;
      RECT 18.890 107.415 20.330 107.555 ;
      RECT 18.890 107.555 19.030 111.485 ;
      RECT 18.890 111.485 19.370 111.625 ;
      RECT 20.330 102.465 20.470 107.555 ;
      RECT 20.270 102.145 20.530 102.465 ;
      RECT 20.330 99.135 20.470 102.145 ;
      RECT 20.270 98.815 20.530 99.135 ;
      RECT 19.310 119.535 19.570 119.855 ;
      RECT 34.190 121.755 34.450 122.075 ;
      RECT 34.250 114.675 34.390 121.755 ;
      RECT 34.190 114.355 34.450 114.675 ;
      RECT 21.290 80.775 21.770 80.915 ;
      RECT 21.290 80.915 21.430 86.325 ;
      RECT 21.770 79.155 21.910 80.915 ;
      RECT 21.710 78.835 21.970 79.155 ;
      RECT 21.770 69.905 21.910 78.835 ;
      RECT 21.710 69.585 21.970 69.905 ;
      RECT 21.770 62.875 21.910 69.585 ;
      RECT 21.710 62.555 21.970 62.875 ;
      RECT 21.770 53.625 21.910 62.555 ;
      RECT 21.710 53.305 21.970 53.625 ;
      RECT 21.770 45.855 21.910 53.305 ;
      RECT 21.710 45.535 21.970 45.855 ;
      RECT 21.770 33.275 21.910 45.535 ;
      RECT 21.710 32.955 21.970 33.275 ;
      RECT 21.290 94.095 21.430 94.835 ;
      RECT 20.810 88.915 21.770 89.055 ;
      RECT 20.810 89.055 20.950 94.095 ;
      RECT 20.810 94.095 21.290 94.235 ;
      RECT 21.770 87.295 21.910 89.055 ;
      RECT 21.710 86.975 21.970 87.295 ;
      RECT 21.770 86.465 21.910 86.975 ;
      RECT 21.290 86.325 21.910 86.465 ;
      RECT 21.770 94.975 21.910 98.535 ;
      RECT 21.290 94.835 21.910 94.975 ;
      RECT 22.250 99.275 22.870 99.415 ;
      RECT 22.730 98.765 22.870 99.275 ;
      RECT 21.770 98.535 22.670 98.675 ;
      RECT 22.670 98.445 22.930 98.765 ;
      RECT 22.250 99.415 22.390 102.005 ;
      RECT 22.670 127.675 22.930 127.995 ;
      RECT 22.730 127.025 22.870 127.675 ;
      RECT 21.770 103.345 22.730 103.485 ;
      RECT 21.770 103.485 21.910 127.025 ;
      RECT 21.770 127.025 22.730 127.165 ;
      RECT 22.730 102.835 22.870 103.485 ;
      RECT 22.670 102.515 22.930 102.835 ;
      RECT 22.730 102.005 22.870 102.515 ;
      RECT 22.390 101.865 22.870 102.005 ;
      RECT 13.130 137.755 13.750 137.895 ;
      RECT 13.130 137.895 13.270 138.405 ;
      RECT 13.610 131.605 13.750 137.755 ;
      RECT 13.130 130.725 13.610 130.865 ;
      RECT 13.130 130.865 13.270 131.465 ;
      RECT 13.130 131.465 13.750 131.605 ;
      RECT 13.610 130.585 13.750 130.865 ;
      RECT 13.070 138.405 13.330 138.725 ;
      RECT 13.550 130.265 13.810 130.585 ;
      RECT 13.610 122.445 13.750 130.265 ;
      RECT 13.550 122.125 13.810 122.445 ;
      RECT 13.610 106.165 13.750 122.125 ;
      RECT 13.550 105.845 13.810 106.165 ;
      RECT 23.150 97.335 23.410 97.425 ;
      RECT 23.150 97.565 23.410 97.655 ;
      RECT 23.150 97.425 23.690 97.565 ;
      RECT 23.210 131.095 23.690 131.235 ;
      RECT 23.210 131.235 23.350 134.795 ;
      RECT 23.690 130.585 23.830 131.235 ;
      RECT 23.630 130.265 23.890 130.585 ;
      RECT 23.690 123.555 23.830 130.265 ;
      RECT 23.630 123.235 23.890 123.555 ;
      RECT 23.690 122.445 23.830 123.235 ;
      RECT 23.630 122.125 23.890 122.445 ;
      RECT 23.690 114.305 23.830 122.125 ;
      RECT 23.630 113.985 23.890 114.305 ;
      RECT 23.690 106.165 23.830 113.985 ;
      RECT 23.630 105.845 23.890 106.165 ;
      RECT 23.690 103.575 23.830 105.845 ;
      RECT 23.630 103.255 23.890 103.575 ;
      RECT 23.690 95.065 23.830 103.255 ;
      RECT 23.630 94.745 23.890 95.065 ;
      RECT 23.630 143.955 23.890 144.275 ;
      RECT 23.690 143.305 23.830 143.955 ;
      RECT 22.730 136.275 23.690 136.415 ;
      RECT 22.730 136.415 22.870 143.305 ;
      RECT 22.730 143.305 23.690 143.445 ;
      RECT 23.690 135.765 23.830 136.415 ;
      RECT 23.630 135.445 23.890 135.765 ;
      RECT 23.690 134.935 23.830 135.445 ;
      RECT 23.210 134.795 23.830 134.935 ;
      RECT 10.250 17.875 10.730 18.015 ;
      RECT 10.250 18.015 10.390 37.855 ;
      RECT 10.730 17.365 10.870 18.015 ;
      RECT 10.670 17.045 10.930 17.365 ;
      RECT 10.250 45.255 10.390 45.995 ;
      RECT 9.770 39.335 10.730 39.475 ;
      RECT 9.770 39.475 9.910 45.255 ;
      RECT 9.770 45.255 10.250 45.395 ;
      RECT 10.730 38.825 10.870 39.475 ;
      RECT 10.670 38.505 10.930 38.825 ;
      RECT 10.730 37.995 10.870 38.505 ;
      RECT 10.250 37.855 10.870 37.995 ;
      RECT 10.250 50.435 10.870 50.575 ;
      RECT 10.730 46.135 10.870 50.435 ;
      RECT 10.250 45.995 10.870 46.135 ;
      RECT 10.390 103.345 10.870 103.485 ;
      RECT 10.730 56.495 10.870 103.345 ;
      RECT 9.770 51.175 10.250 51.315 ;
      RECT 9.770 51.315 9.910 56.355 ;
      RECT 9.770 56.355 10.870 56.495 ;
      RECT 10.250 50.575 10.390 51.315 ;
      RECT 10.250 118.145 10.390 118.885 ;
      RECT 9.770 104.085 10.250 104.225 ;
      RECT 9.770 104.225 9.910 118.145 ;
      RECT 9.770 118.145 10.250 118.285 ;
      RECT 10.250 103.345 10.390 104.225 ;
      RECT 10.670 215.365 10.930 215.685 ;
      RECT 10.730 119.025 10.870 215.365 ;
      RECT 10.250 118.885 10.870 119.025 ;
      RECT 29.930 122.445 30.070 123.835 ;
      RECT 29.870 122.125 30.130 122.445 ;
      RECT 30.070 127.765 30.550 127.905 ;
      RECT 30.410 123.835 30.550 127.765 ;
      RECT 30.070 123.695 30.550 123.835 ;
      RECT 29.930 127.765 30.070 129.895 ;
      RECT 29.870 129.895 30.130 130.215 ;
      RECT 39.050 128.365 39.190 132.575 ;
      RECT 38.990 128.045 39.250 128.365 ;
      RECT 39.050 132.575 39.660 132.715 ;
      RECT 38.990 133.965 39.250 134.285 ;
      RECT 39.190 133.430 39.660 133.570 ;
      RECT 39.050 133.430 39.190 133.965 ;
      RECT 15.470 135.445 15.730 135.765 ;
      RECT 15.530 131.325 15.670 135.445 ;
      RECT 15.470 131.005 15.730 131.325 ;
      RECT 15.530 128.365 15.670 131.005 ;
      RECT 15.470 128.045 15.730 128.365 ;
      RECT 39.950 138.035 40.210 138.355 ;
      RECT 40.010 134.450 40.150 138.035 ;
      RECT 20.270 127.305 20.530 127.625 ;
      RECT 20.330 123.185 20.470 127.305 ;
      RECT 20.270 122.865 20.530 123.185 ;
      RECT 20.330 120.225 20.470 122.865 ;
      RECT 20.270 119.905 20.530 120.225 ;
      RECT 25.550 138.775 25.810 139.095 ;
      RECT 25.610 136.505 25.750 138.775 ;
      RECT 25.550 136.185 25.810 136.505 ;
      RECT 28.910 142.105 29.170 142.425 ;
      RECT 28.970 139.095 29.110 142.105 ;
      RECT 28.910 138.775 29.170 139.095 ;
      RECT 15.470 143.585 15.730 143.905 ;
      RECT 15.530 139.465 15.670 143.585 ;
      RECT 15.470 139.145 15.730 139.465 ;
      RECT 15.530 136.505 15.670 139.145 ;
      RECT 15.470 136.185 15.730 136.505 ;
      RECT 28.910 127.305 29.170 127.625 ;
      RECT 28.970 124.295 29.110 127.305 ;
      RECT 28.910 123.975 29.170 124.295 ;
      RECT 25.550 143.955 25.810 144.275 ;
      RECT 25.610 140.575 25.750 143.955 ;
      RECT 25.550 140.255 25.810 140.575 ;
      RECT 28.430 146.175 28.690 146.495 ;
      RECT 28.490 143.905 28.630 146.175 ;
      RECT 28.430 143.585 28.690 143.905 ;
      RECT 28.910 150.245 29.170 150.565 ;
      RECT 28.970 147.235 29.110 150.245 ;
      RECT 28.910 146.915 29.170 147.235 ;
      RECT 40.010 144.645 40.150 152.330 ;
      RECT 39.950 144.325 40.210 144.645 ;
      RECT 25.550 152.095 25.810 152.415 ;
      RECT 25.610 148.715 25.750 152.095 ;
      RECT 25.550 148.395 25.810 148.715 ;
      RECT 38.510 153.205 38.770 153.525 ;
      RECT 38.570 148.715 38.710 153.205 ;
      RECT 38.510 148.395 38.770 148.715 ;
      RECT 39.050 152.785 39.190 153.665 ;
      RECT 38.990 152.465 39.250 152.785 ;
      RECT 39.050 153.665 39.660 153.805 ;
      RECT 9.230 154.315 9.490 154.635 ;
      RECT 9.290 147.605 9.430 154.315 ;
      RECT 9.230 147.285 9.490 147.605 ;
      RECT 9.290 144.645 9.430 147.285 ;
      RECT 9.230 144.325 9.490 144.645 ;
      RECT 13.070 154.315 13.330 154.635 ;
      RECT 13.130 151.675 13.270 154.315 ;
      RECT 13.070 151.355 13.330 151.675 ;
      RECT 22.190 155.055 22.450 155.375 ;
      RECT 22.250 152.785 22.390 155.055 ;
      RECT 22.190 152.465 22.450 152.785 ;
      RECT 12.110 144.185 12.370 144.275 ;
      RECT 12.790 150.705 13.270 150.845 ;
      RECT 13.130 144.925 13.270 150.705 ;
      RECT 12.650 144.185 12.790 144.785 ;
      RECT 12.650 144.785 13.270 144.925 ;
      RECT 12.650 155.285 12.790 155.795 ;
      RECT 12.410 151.445 12.790 151.585 ;
      RECT 12.410 151.585 12.550 155.145 ;
      RECT 12.410 155.145 12.790 155.285 ;
      RECT 12.650 150.705 12.790 151.445 ;
      RECT 12.590 155.795 12.850 156.115 ;
      RECT 12.170 143.305 12.650 143.445 ;
      RECT 12.170 143.445 12.310 143.955 ;
      RECT 12.110 143.955 12.370 144.045 ;
      RECT 12.110 144.045 12.790 144.185 ;
      RECT 12.650 139.235 12.790 143.445 ;
      RECT 12.170 135.765 12.310 139.235 ;
      RECT 12.110 135.445 12.370 135.765 ;
      RECT 12.170 127.995 12.310 135.445 ;
      RECT 12.110 127.675 12.370 127.995 ;
      RECT 12.170 120.225 12.310 127.675 ;
      RECT 12.110 119.905 12.370 120.225 ;
      RECT 12.170 139.235 12.650 139.375 ;
      RECT 39.050 155.145 39.660 155.285 ;
      RECT 39.050 155.285 39.190 158.385 ;
      RECT 38.990 158.385 39.250 158.705 ;
      RECT 18.830 159.865 19.090 160.185 ;
      RECT 18.890 154.635 19.030 159.865 ;
      RECT 18.830 154.315 19.090 154.635 ;
      RECT 39.950 162.455 40.210 162.775 ;
      RECT 40.010 156.150 40.150 162.455 ;
      RECT 25.550 163.195 25.810 163.515 ;
      RECT 25.610 160.925 25.750 163.195 ;
      RECT 25.550 160.605 25.810 160.925 ;
      RECT 7.790 168.005 8.050 168.325 ;
      RECT 7.850 163.885 7.990 168.005 ;
      RECT 7.790 163.565 8.050 163.885 ;
      RECT 7.850 160.925 7.990 163.565 ;
      RECT 7.790 160.605 8.050 160.925 ;
      RECT 25.130 163.145 25.270 164.025 ;
      RECT 25.070 162.825 25.330 163.145 ;
      RECT 25.130 160.185 25.270 162.825 ;
      RECT 25.070 159.865 25.330 160.185 ;
      RECT 25.130 159.215 25.750 159.355 ;
      RECT 25.130 159.355 25.270 159.865 ;
      RECT 25.610 155.655 25.750 159.215 ;
      RECT 25.270 167.355 25.750 167.495 ;
      RECT 25.610 164.165 25.750 167.355 ;
      RECT 25.130 164.025 25.750 164.165 ;
      RECT 25.130 155.005 25.270 155.515 ;
      RECT 25.070 154.685 25.330 155.005 ;
      RECT 25.130 152.045 25.270 154.685 ;
      RECT 25.070 151.725 25.330 152.045 ;
      RECT 25.130 146.865 25.270 151.725 ;
      RECT 25.070 146.545 25.330 146.865 ;
      RECT 25.130 144.275 25.270 146.545 ;
      RECT 25.070 143.955 25.330 144.275 ;
      RECT 25.130 155.515 25.750 155.655 ;
      RECT 25.130 167.355 25.270 168.005 ;
      RECT 25.070 168.005 25.330 168.325 ;
      RECT 25.550 170.595 25.810 170.915 ;
      RECT 25.610 169.065 25.750 170.595 ;
      RECT 25.550 168.745 25.810 169.065 ;
      RECT 28.430 170.595 28.690 170.915 ;
      RECT 28.490 168.325 28.630 170.595 ;
      RECT 28.430 168.005 28.690 168.325 ;
      RECT 27.470 171.335 27.730 171.655 ;
      RECT 27.530 169.065 27.670 171.335 ;
      RECT 27.470 168.745 27.730 169.065 ;
      RECT 40.010 169.065 40.150 175.310 ;
      RECT 39.950 168.745 40.210 169.065 ;
      RECT 39.050 173.135 39.190 176.190 ;
      RECT 38.990 172.815 39.250 173.135 ;
      RECT 39.050 176.190 39.660 176.330 ;
      RECT 19.310 176.145 19.570 176.465 ;
      RECT 19.370 172.025 19.510 176.145 ;
      RECT 19.310 171.705 19.570 172.025 ;
      RECT 19.370 169.065 19.510 171.705 ;
      RECT 19.310 168.745 19.570 169.065 ;
      RECT 9.710 176.515 9.970 176.835 ;
      RECT 9.770 167.585 9.910 176.515 ;
      RECT 9.710 167.265 9.970 167.585 ;
      RECT 9.770 160.555 9.910 167.265 ;
      RECT 9.710 160.235 9.970 160.555 ;
      RECT 9.770 156.115 9.910 160.235 ;
      RECT 9.710 155.795 9.970 156.115 ;
      RECT 39.050 177.205 39.190 177.610 ;
      RECT 39.190 177.470 39.660 177.610 ;
      RECT 38.990 176.885 39.250 177.205 ;
      RECT 23.630 178.735 23.890 179.055 ;
      RECT 23.690 177.205 23.830 178.735 ;
      RECT 23.630 176.885 23.890 177.205 ;
      RECT 38.570 176.605 39.660 176.745 ;
      RECT 38.570 176.745 38.710 178.735 ;
      RECT 38.510 178.735 38.770 179.055 ;
      RECT 8.270 184.285 8.530 184.605 ;
      RECT 8.330 180.165 8.470 184.285 ;
      RECT 8.270 179.845 8.530 180.165 ;
      RECT 8.330 177.205 8.470 179.845 ;
      RECT 8.270 176.885 8.530 177.205 ;
      RECT 14.990 192.425 15.250 192.745 ;
      RECT 15.050 188.305 15.190 192.425 ;
      RECT 14.990 187.985 15.250 188.305 ;
      RECT 15.050 185.345 15.190 187.985 ;
      RECT 14.990 185.025 15.250 185.345 ;
      RECT 25.550 192.795 25.810 193.115 ;
      RECT 25.610 187.935 25.750 192.795 ;
      RECT 25.550 187.615 25.810 187.935 ;
      RECT 22.730 179.935 23.210 180.075 ;
      RECT 22.730 180.075 22.870 186.595 ;
      RECT 23.210 179.425 23.350 180.075 ;
      RECT 23.150 179.105 23.410 179.425 ;
      RECT 23.210 176.835 23.350 179.105 ;
      RECT 23.150 176.515 23.410 176.835 ;
      RECT 23.210 175.865 23.350 176.515 ;
      RECT 22.730 171.795 23.210 171.935 ;
      RECT 22.730 171.935 22.870 175.865 ;
      RECT 22.730 175.865 23.210 176.005 ;
      RECT 23.210 171.285 23.350 171.935 ;
      RECT 23.150 170.965 23.410 171.285 ;
      RECT 23.210 168.325 23.350 170.965 ;
      RECT 23.150 168.005 23.410 168.325 ;
      RECT 22.250 188.075 23.210 188.215 ;
      RECT 22.250 188.215 22.390 192.285 ;
      RECT 23.150 195.385 23.410 195.705 ;
      RECT 23.210 193.115 23.350 195.385 ;
      RECT 23.150 192.795 23.410 193.115 ;
      RECT 23.210 192.285 23.350 192.795 ;
      RECT 22.390 192.145 23.350 192.285 ;
      RECT 23.210 187.565 23.350 188.215 ;
      RECT 23.150 187.245 23.410 187.565 ;
      RECT 23.210 186.735 23.350 187.245 ;
      RECT 22.730 186.595 23.350 186.735 ;
      RECT 40.010 193.485 40.150 195.730 ;
      RECT 39.950 193.165 40.210 193.485 ;
      RECT 39.050 195.845 39.190 196.585 ;
      RECT 39.050 196.585 39.660 196.725 ;
      RECT 38.570 192.885 39.050 193.025 ;
      RECT 38.570 193.025 38.710 195.845 ;
      RECT 38.570 195.845 39.050 195.985 ;
      RECT 39.050 189.415 39.190 193.025 ;
      RECT 38.990 189.095 39.250 189.415 ;
      RECT 39.050 198.065 39.660 198.205 ;
      RECT 39.050 198.205 39.190 199.085 ;
      RECT 38.990 199.085 39.250 199.405 ;
      RECT 13.610 196.215 14.030 196.355 ;
      RECT 14.030 196.125 14.290 196.445 ;
      RECT 14.090 193.485 14.230 196.125 ;
      RECT 14.030 193.165 14.290 193.485 ;
      RECT 13.550 200.565 13.810 200.885 ;
      RECT 13.610 196.355 13.750 200.565 ;
      RECT 9.290 120.365 9.770 120.505 ;
      RECT 9.290 120.505 9.430 126.795 ;
      RECT 9.770 119.855 9.910 120.505 ;
      RECT 9.710 119.535 9.970 119.855 ;
      RECT 8.810 128.135 9.770 128.275 ;
      RECT 8.810 128.275 8.950 134.565 ;
      RECT 9.770 127.625 9.910 128.275 ;
      RECT 9.710 127.305 9.970 127.625 ;
      RECT 9.770 126.795 9.910 127.305 ;
      RECT 9.430 126.655 9.910 126.795 ;
      RECT 8.810 135.905 9.770 136.045 ;
      RECT 8.810 136.045 8.950 142.195 ;
      RECT 9.770 135.395 9.910 136.045 ;
      RECT 9.710 135.075 9.970 135.395 ;
      RECT 9.770 134.565 9.910 135.075 ;
      RECT 8.950 134.425 9.910 134.565 ;
      RECT 8.330 142.935 9.710 143.075 ;
      RECT 9.710 142.845 9.970 143.165 ;
      RECT 9.770 142.195 9.910 142.845 ;
      RECT 8.810 142.195 9.770 142.335 ;
      RECT 8.810 175.725 8.950 176.375 ;
      RECT 8.750 175.405 9.010 175.725 ;
      RECT 8.810 174.755 8.950 175.405 ;
      RECT 8.330 168.835 8.810 168.975 ;
      RECT 8.330 168.975 8.470 174.755 ;
      RECT 8.330 174.755 8.810 174.895 ;
      RECT 8.810 167.955 8.950 168.975 ;
      RECT 8.750 167.635 9.010 167.955 ;
      RECT 8.810 159.445 8.950 167.635 ;
      RECT 8.750 159.125 9.010 159.445 ;
      RECT 8.810 158.615 8.950 159.125 ;
      RECT 9.230 200.935 9.490 201.255 ;
      RECT 9.290 192.005 9.430 200.935 ;
      RECT 9.230 191.685 9.490 192.005 ;
      RECT 9.290 184.975 9.430 191.685 ;
      RECT 9.230 184.655 9.490 184.975 ;
      RECT 9.290 176.375 9.430 184.655 ;
      RECT 8.950 176.235 9.430 176.375 ;
      RECT 8.330 155.745 8.470 158.475 ;
      RECT 8.270 155.425 8.530 155.745 ;
      RECT 8.330 143.075 8.470 155.425 ;
      RECT 8.330 158.475 8.950 158.615 ;
      RECT 23.150 201.305 23.410 201.625 ;
      RECT 23.210 200.655 23.350 201.305 ;
      RECT 22.730 198.065 23.210 198.205 ;
      RECT 22.730 198.205 22.870 200.655 ;
      RECT 22.730 200.655 23.210 200.795 ;
      RECT 23.210 197.555 23.350 198.205 ;
      RECT 23.150 197.235 23.410 197.555 ;
      RECT 39.950 203.155 40.210 203.475 ;
      RECT 40.010 199.550 40.150 203.155 ;
      RECT 28.910 207.225 29.170 207.545 ;
      RECT 28.970 204.215 29.110 207.225 ;
      RECT 28.910 203.895 29.170 204.215 ;
      RECT 38.090 198.435 38.510 198.575 ;
      RECT 38.510 198.345 38.770 198.665 ;
      RECT 38.030 207.225 38.290 207.545 ;
      RECT 38.090 198.575 38.230 207.225 ;
      RECT 14.990 208.705 15.250 209.025 ;
      RECT 15.050 204.585 15.190 208.705 ;
      RECT 14.990 204.265 15.250 204.585 ;
      RECT 15.050 200.885 15.190 204.265 ;
      RECT 14.990 200.565 15.250 200.885 ;
      RECT 23.630 208.705 23.890 209.025 ;
      RECT 23.690 208.055 23.830 208.705 ;
      RECT 23.210 203.985 23.690 204.125 ;
      RECT 23.210 204.125 23.350 208.055 ;
      RECT 23.210 208.055 23.690 208.195 ;
      RECT 23.690 203.475 23.830 204.125 ;
      RECT 23.630 203.155 23.890 203.475 ;
      RECT 27.950 208.705 28.210 209.025 ;
      RECT 28.010 205.695 28.150 208.705 ;
      RECT 27.950 205.375 28.210 205.695 ;
      RECT 25.130 195.705 25.270 196.355 ;
      RECT 25.070 195.385 25.330 195.705 ;
      RECT 25.270 200.285 25.750 200.425 ;
      RECT 25.610 196.355 25.750 200.285 ;
      RECT 25.270 196.215 25.750 196.355 ;
      RECT 25.130 200.285 25.270 200.935 ;
      RECT 25.070 200.935 25.330 201.255 ;
      RECT 25.130 201.255 25.270 203.895 ;
      RECT 25.070 203.895 25.330 204.215 ;
      RECT 25.130 204.215 25.270 204.725 ;
      RECT 25.270 208.055 25.750 208.195 ;
      RECT 25.610 204.865 25.750 208.055 ;
      RECT 25.130 204.725 25.750 204.865 ;
      RECT 25.130 208.055 25.270 208.705 ;
      RECT 25.070 208.705 25.330 209.025 ;
      RECT 25.130 209.025 25.270 211.665 ;
      RECT 25.070 211.665 25.330 211.985 ;
      RECT 27.470 121.755 27.730 122.075 ;
      RECT 27.530 119.485 27.670 121.755 ;
      RECT 27.470 119.165 27.730 119.485 ;
      RECT 25.070 217.215 25.330 217.535 ;
      RECT 25.130 213.835 25.270 217.215 ;
      RECT 25.070 213.515 25.330 213.835 ;
      RECT 40.010 213.835 40.150 218.710 ;
      RECT 39.950 213.515 40.210 213.835 ;
      RECT 39.050 217.905 39.190 219.525 ;
      RECT 38.990 217.585 39.250 217.905 ;
      RECT 39.050 219.525 39.660 219.665 ;
      RECT 15.470 219.435 15.730 219.755 ;
      RECT 15.530 212.725 15.670 219.435 ;
      RECT 15.470 212.405 15.730 212.725 ;
      RECT 15.530 209.765 15.670 212.405 ;
      RECT 15.470 209.445 15.730 209.765 ;
      RECT 7.370 209.395 7.510 210.045 ;
      RECT 7.310 209.075 7.570 209.395 ;
      RECT 7.510 208.425 8.330 208.565 ;
      RECT 7.370 208.425 7.510 209.075 ;
      RECT 7.510 215.825 8.950 215.965 ;
      RECT 8.810 210.045 8.950 215.825 ;
      RECT 7.510 209.905 8.950 210.045 ;
      RECT 7.370 215.825 7.510 216.475 ;
      RECT 7.310 216.475 7.570 216.795 ;
      RECT 7.370 216.795 7.510 220.175 ;
      RECT 7.310 220.175 7.570 220.495 ;
      RECT 8.330 201.905 8.470 208.565 ;
      RECT 7.370 201.255 7.510 201.905 ;
      RECT 7.510 201.765 8.470 201.905 ;
      RECT 7.310 200.935 7.570 201.255 ;
      RECT 39.950 223.505 40.210 223.825 ;
      RECT 40.010 221.250 40.150 223.505 ;
      RECT 25.550 113.615 25.810 113.935 ;
      RECT 25.610 111.345 25.750 113.615 ;
      RECT 25.550 111.025 25.810 111.345 ;
      RECT 39.950 113.615 40.210 113.935 ;
      RECT 40.010 112.750 40.150 113.615 ;
      RECT 15.470 114.355 15.730 114.675 ;
      RECT 15.530 108.015 15.670 114.355 ;
      RECT 15.470 107.695 15.730 108.015 ;
      RECT 39.050 87.665 39.190 89.390 ;
      RECT 38.990 87.345 39.250 87.665 ;
      RECT 39.050 89.390 39.660 89.530 ;
      RECT 39.950 93.265 40.210 93.585 ;
      RECT 40.010 91.050 40.150 93.265 ;
      RECT 22.670 94.745 22.930 95.065 ;
      RECT 22.730 89.515 22.870 94.745 ;
      RECT 22.670 89.195 22.930 89.515 ;
      RECT 25.130 82.115 25.270 82.765 ;
      RECT 25.070 81.795 25.330 82.115 ;
      RECT 25.270 85.955 25.750 86.095 ;
      RECT 25.610 82.765 25.750 85.955 ;
      RECT 25.270 82.625 25.750 82.765 ;
      RECT 25.130 89.885 25.270 90.395 ;
      RECT 25.070 89.565 25.330 89.885 ;
      RECT 25.130 86.925 25.270 89.565 ;
      RECT 25.070 86.605 25.330 86.925 ;
      RECT 25.130 85.955 25.270 86.605 ;
      RECT 25.130 73.605 25.270 74.255 ;
      RECT 25.070 73.285 25.330 73.605 ;
      RECT 25.270 81.145 25.750 81.285 ;
      RECT 25.610 74.255 25.750 81.145 ;
      RECT 25.270 74.115 25.750 74.255 ;
      RECT 25.130 81.145 25.270 81.795 ;
      RECT 25.270 94.095 25.750 94.235 ;
      RECT 25.610 90.535 25.750 94.095 ;
      RECT 25.130 90.395 25.750 90.535 ;
      RECT 25.130 94.095 25.270 94.745 ;
      RECT 25.070 94.745 25.330 95.065 ;
      RECT 11.690 30.315 11.830 37.485 ;
      RECT 11.630 29.995 11.890 30.315 ;
      RECT 11.690 24.765 11.830 29.995 ;
      RECT 11.630 24.445 11.890 24.765 ;
      RECT 11.690 16.625 11.830 24.445 ;
      RECT 11.630 16.305 11.890 16.625 ;
      RECT 11.830 45.255 12.310 45.395 ;
      RECT 12.170 37.625 12.310 45.255 ;
      RECT 11.690 37.485 12.310 37.625 ;
      RECT 11.690 45.255 11.830 48.865 ;
      RECT 11.630 48.865 11.890 49.185 ;
      RECT 11.690 49.185 11.830 55.985 ;
      RECT 12.110 95.115 12.370 95.435 ;
      RECT 12.170 89.885 12.310 95.115 ;
      RECT 12.110 89.565 12.370 89.885 ;
      RECT 12.170 81.745 12.310 89.565 ;
      RECT 12.110 81.425 12.370 81.745 ;
      RECT 12.170 73.605 12.310 81.425 ;
      RECT 12.110 73.285 12.370 73.605 ;
      RECT 12.170 65.465 12.310 73.285 ;
      RECT 12.110 65.145 12.370 65.465 ;
      RECT 12.170 57.325 12.310 65.145 ;
      RECT 12.110 57.005 12.370 57.325 ;
      RECT 12.170 56.125 12.310 57.005 ;
      RECT 11.690 55.985 12.310 56.125 ;
      RECT 18.350 97.335 18.610 97.655 ;
      RECT 18.410 90.625 18.550 97.335 ;
      RECT 18.350 90.305 18.610 90.625 ;
      RECT 18.410 87.665 18.550 90.305 ;
      RECT 18.350 87.345 18.610 87.665 ;
      RECT 20.750 98.075 21.010 98.395 ;
      RECT 20.810 95.805 20.950 98.075 ;
      RECT 20.750 95.485 21.010 95.805 ;
      RECT 15.530 85.955 16.430 86.095 ;
      RECT 16.430 85.865 16.690 86.185 ;
      RECT 16.490 78.045 16.630 85.865 ;
      RECT 16.430 77.725 16.690 78.045 ;
      RECT 16.490 71.015 16.630 77.725 ;
      RECT 16.430 70.695 16.690 71.015 ;
      RECT 16.490 61.765 16.630 70.695 ;
      RECT 16.430 61.445 16.690 61.765 ;
      RECT 15.470 98.815 15.730 99.135 ;
      RECT 15.530 86.095 15.670 98.815 ;
      RECT 9.230 102.515 9.490 102.835 ;
      RECT 9.290 97.655 9.430 102.515 ;
      RECT 9.230 97.335 9.490 97.655 ;
      RECT 9.290 94.695 9.430 97.335 ;
      RECT 9.230 94.375 9.490 94.695 ;
      RECT 25.070 103.255 25.330 103.575 ;
      RECT 25.130 99.875 25.270 103.255 ;
      RECT 25.070 99.555 25.330 99.875 ;
      RECT 8.270 105.845 8.530 106.165 ;
      RECT 8.330 95.435 8.470 105.845 ;
      RECT 8.270 95.115 8.530 95.435 ;
      RECT 33.710 106.215 33.970 106.535 ;
      RECT 33.770 99.875 33.910 106.215 ;
      RECT 33.710 99.555 33.970 99.875 ;
      RECT 40.010 108.015 40.150 108.930 ;
      RECT 39.950 107.695 40.210 108.015 ;
      RECT 39.050 103.945 39.190 109.635 ;
      RECT 38.990 103.625 39.250 103.945 ;
      RECT 39.050 109.635 39.660 109.775 ;
      RECT 20.270 111.025 20.530 111.345 ;
      RECT 20.330 108.015 20.470 111.025 ;
      RECT 20.270 107.695 20.530 108.015 ;
      RECT 29.390 11.865 29.650 12.185 ;
      RECT 29.450 8.485 29.590 11.865 ;
      RECT 29.390 8.165 29.650 8.485 ;
      RECT 30.350 13.345 30.610 13.665 ;
      RECT 30.410 10.335 30.550 13.345 ;
      RECT 30.350 10.015 30.610 10.335 ;
      RECT 25.070 15.935 25.330 16.255 ;
      RECT 25.130 13.665 25.270 15.935 ;
      RECT 25.070 13.345 25.330 13.665 ;
      RECT 40.010 18.475 40.150 22.130 ;
      RECT 39.950 18.155 40.210 18.475 ;
      RECT 38.090 14.405 38.230 23.055 ;
      RECT 38.030 14.085 38.290 14.405 ;
      RECT 38.090 23.055 38.510 23.195 ;
      RECT 38.510 22.965 38.770 23.285 ;
      RECT 23.150 24.075 23.410 24.395 ;
      RECT 23.210 21.805 23.350 24.075 ;
      RECT 23.150 21.485 23.410 21.805 ;
      RECT 39.050 22.545 39.190 24.290 ;
      RECT 38.990 22.225 39.250 22.545 ;
      RECT 39.050 24.290 39.660 24.430 ;
      RECT 39.950 28.145 40.210 28.465 ;
      RECT 40.010 25.950 40.150 28.145 ;
      RECT 22.190 29.625 22.450 29.945 ;
      RECT 22.250 25.135 22.390 29.625 ;
      RECT 22.190 24.815 22.450 25.135 ;
      RECT 22.250 22.175 22.390 24.815 ;
      RECT 22.190 21.855 22.450 22.175 ;
      RECT 22.250 16.995 22.390 21.855 ;
      RECT 22.190 16.675 22.450 16.995 ;
      RECT 22.250 8.855 22.390 16.675 ;
      RECT 22.190 8.535 22.450 8.855 ;
      RECT 38.990 32.215 39.250 32.535 ;
      RECT 39.050 28.605 39.190 32.215 ;
      RECT 38.570 25.645 39.050 25.785 ;
      RECT 38.570 25.785 38.710 28.605 ;
      RECT 38.570 28.605 39.050 28.745 ;
      RECT 39.050 24.930 39.660 25.070 ;
      RECT 39.050 25.070 39.190 25.785 ;
      RECT 25.550 32.955 25.810 33.275 ;
      RECT 25.610 30.315 25.750 32.955 ;
      RECT 25.550 29.995 25.810 30.315 ;
      RECT 19.310 36.285 19.570 36.605 ;
      RECT 19.370 32.535 19.510 36.285 ;
      RECT 19.310 32.215 19.570 32.535 ;
      RECT 19.370 25.505 19.510 32.215 ;
      RECT 19.310 25.185 19.570 25.505 ;
      RECT 13.550 40.355 13.810 40.675 ;
      RECT 13.610 32.535 13.750 40.355 ;
      RECT 13.550 32.215 13.810 32.535 ;
      RECT 13.610 29.575 13.750 32.215 ;
      RECT 13.550 29.255 13.810 29.575 ;
      RECT 23.630 40.355 23.890 40.675 ;
      RECT 23.690 39.705 23.830 40.355 ;
      RECT 23.210 30.455 23.690 30.595 ;
      RECT 23.210 30.595 23.350 39.705 ;
      RECT 23.210 39.705 23.690 39.845 ;
      RECT 23.690 29.945 23.830 30.595 ;
      RECT 23.630 29.625 23.890 29.945 ;
      RECT 28.910 40.355 29.170 40.675 ;
      RECT 28.970 38.085 29.110 40.355 ;
      RECT 28.910 37.765 29.170 38.085 ;
      RECT 7.850 33.275 7.990 33.925 ;
      RECT 7.790 32.955 8.050 33.275 ;
      RECT 7.990 37.485 8.470 37.625 ;
      RECT 8.330 33.925 8.470 37.485 ;
      RECT 7.990 33.785 8.470 33.925 ;
      RECT 7.850 37.485 7.990 38.135 ;
      RECT 7.790 38.135 8.050 38.455 ;
      RECT 7.850 38.455 7.990 40.725 ;
      RECT 7.790 40.725 8.050 41.045 ;
      RECT 40.010 38.825 40.150 45.110 ;
      RECT 39.950 38.505 40.210 38.825 ;
      RECT 18.830 45.165 19.090 45.485 ;
      RECT 18.890 41.045 19.030 45.165 ;
      RECT 18.830 40.725 19.090 41.045 ;
      RECT 18.890 38.455 19.030 40.725 ;
      RECT 18.830 38.135 19.090 38.455 ;
      RECT 18.890 34.015 19.030 38.135 ;
      RECT 18.830 33.695 19.090 34.015 ;
      RECT 39.050 45.485 39.190 45.990 ;
      RECT 38.990 45.165 39.250 45.485 ;
      RECT 39.050 45.990 39.660 46.130 ;
      RECT 35.150 45.905 35.410 46.225 ;
      RECT 35.210 42.895 35.350 45.905 ;
      RECT 35.150 42.575 35.410 42.895 ;
      RECT 19.310 46.645 19.570 46.965 ;
      RECT 19.370 42.895 19.510 46.645 ;
      RECT 19.310 42.575 19.570 42.895 ;
      RECT 3.950 48.495 4.210 48.815 ;
      RECT 4.010 47.845 4.150 48.495 ;
      RECT 3.050 41.925 4.010 42.065 ;
      RECT 3.050 42.065 3.190 47.845 ;
      RECT 3.050 47.845 4.010 47.985 ;
      RECT 4.010 41.415 4.150 42.065 ;
      RECT 3.950 41.095 4.210 41.415 ;
      RECT 39.950 48.495 40.210 48.815 ;
      RECT 40.010 47.650 40.150 48.495 ;
      RECT 9.230 49.605 9.490 49.925 ;
      RECT 9.290 46.965 9.430 49.605 ;
      RECT 9.230 46.645 9.490 46.965 ;
      RECT 39.050 46.630 39.660 46.770 ;
      RECT 39.050 46.770 39.190 52.565 ;
      RECT 38.990 52.565 39.250 52.885 ;
      RECT 12.650 53.395 13.270 53.535 ;
      RECT 12.650 53.535 12.790 54.045 ;
      RECT 13.130 50.575 13.270 53.395 ;
      RECT 12.650 49.925 12.790 50.435 ;
      RECT 12.650 50.435 13.270 50.575 ;
      RECT 12.590 49.605 12.850 49.925 ;
      RECT 12.650 46.225 12.790 49.605 ;
      RECT 12.590 45.905 12.850 46.225 ;
      RECT 12.590 54.045 12.850 54.365 ;
      RECT 25.550 54.045 25.810 54.365 ;
      RECT 25.610 51.035 25.750 54.045 ;
      RECT 25.550 50.715 25.810 51.035 ;
      RECT 27.530 47.845 28.010 47.985 ;
      RECT 27.530 47.985 27.670 48.495 ;
      RECT 27.470 48.495 27.730 48.815 ;
      RECT 27.530 48.815 27.670 49.465 ;
      RECT 27.670 56.725 28.630 56.865 ;
      RECT 28.490 49.465 28.630 56.725 ;
      RECT 27.670 49.325 28.630 49.465 ;
      RECT 27.530 56.725 27.670 57.375 ;
      RECT 27.470 57.375 27.730 57.695 ;
      RECT 28.010 41.325 28.150 47.985 ;
      RECT 27.530 40.675 27.670 41.185 ;
      RECT 27.470 40.355 27.730 40.675 ;
      RECT 27.530 41.185 28.150 41.325 ;
      RECT 19.850 54.735 19.990 55.245 ;
      RECT 19.790 54.415 20.050 54.735 ;
      RECT 19.850 46.965 19.990 54.415 ;
      RECT 19.790 46.645 20.050 46.965 ;
      RECT 19.990 58.945 20.470 59.085 ;
      RECT 20.330 55.385 20.470 58.945 ;
      RECT 19.850 55.245 20.470 55.385 ;
      RECT 19.850 58.945 19.990 61.445 ;
      RECT 19.790 61.445 20.050 61.765 ;
      RECT 25.130 57.695 25.270 58.345 ;
      RECT 25.070 57.375 25.330 57.695 ;
      RECT 25.270 61.165 25.750 61.305 ;
      RECT 25.610 58.345 25.750 61.165 ;
      RECT 25.270 58.205 25.750 58.345 ;
      RECT 25.130 61.165 25.270 61.815 ;
      RECT 25.070 61.815 25.330 62.135 ;
      RECT 18.830 62.185 19.090 62.505 ;
      RECT 18.890 61.535 19.030 62.185 ;
      RECT 18.410 58.575 18.890 58.715 ;
      RECT 18.410 58.715 18.550 61.535 ;
      RECT 18.410 61.535 18.890 61.675 ;
      RECT 18.890 58.065 19.030 58.715 ;
      RECT 18.830 57.745 19.090 58.065 ;
      RECT 18.890 55.105 19.030 57.745 ;
      RECT 18.830 54.785 19.090 55.105 ;
      RECT 23.630 62.555 23.890 62.875 ;
      RECT 23.690 61.535 23.830 62.555 ;
      RECT 23.210 58.205 23.690 58.345 ;
      RECT 23.210 58.345 23.350 61.535 ;
      RECT 23.210 61.535 23.690 61.675 ;
      RECT 23.690 57.695 23.830 58.345 ;
      RECT 23.630 57.375 23.890 57.695 ;
      RECT 40.010 63.245 40.150 65.530 ;
      RECT 39.950 62.925 40.210 63.245 ;
      RECT 39.050 65.605 39.190 66.345 ;
      RECT 39.050 66.345 39.660 66.485 ;
      RECT 38.570 62.645 39.050 62.785 ;
      RECT 38.570 62.785 38.710 65.605 ;
      RECT 38.570 65.605 39.050 65.745 ;
      RECT 39.050 59.175 39.190 62.785 ;
      RECT 38.990 58.855 39.250 59.175 ;
      RECT 39.050 66.945 39.190 67.455 ;
      RECT 38.990 66.625 39.250 66.945 ;
      RECT 39.050 67.455 39.660 67.595 ;
      RECT 25.550 68.845 25.810 69.165 ;
      RECT 25.610 65.835 25.750 68.845 ;
      RECT 25.550 65.515 25.810 65.835 ;
      RECT 28.910 68.845 29.170 69.165 ;
      RECT 28.970 65.835 29.110 68.845 ;
      RECT 28.910 65.515 29.170 65.835 ;
      RECT 38.990 68.845 39.250 69.165 ;
      RECT 39.190 68.565 39.660 68.705 ;
      RECT 39.050 68.565 39.190 68.845 ;
      RECT 13.130 69.675 13.750 69.815 ;
      RECT 13.130 69.815 13.270 70.325 ;
      RECT 13.610 66.715 13.750 69.675 ;
      RECT 13.070 70.325 13.330 70.645 ;
      RECT 13.130 66.205 13.270 66.715 ;
      RECT 13.070 65.885 13.330 66.205 ;
      RECT 13.130 63.245 13.270 65.885 ;
      RECT 13.070 62.925 13.330 63.245 ;
      RECT 13.130 66.715 13.610 66.855 ;
      RECT 20.270 70.325 20.530 70.645 ;
      RECT 20.330 67.315 20.470 70.325 ;
      RECT 20.270 66.995 20.530 67.315 ;
      RECT 23.150 72.915 23.410 73.235 ;
      RECT 23.210 70.645 23.350 72.915 ;
      RECT 23.150 70.325 23.410 70.645 ;
      RECT 23.210 62.505 23.350 70.325 ;
      RECT 23.150 62.185 23.410 62.505 ;
      RECT 28.910 72.915 29.170 73.235 ;
      RECT 28.970 70.645 29.110 72.915 ;
      RECT 28.910 70.325 29.170 70.645 ;
      RECT 39.950 72.915 40.210 73.235 ;
      RECT 40.010 69.350 40.150 72.915 ;
      RECT 14.030 78.465 14.290 78.785 ;
      RECT 14.090 74.345 14.230 78.465 ;
      RECT 14.030 74.025 14.290 74.345 ;
      RECT 14.090 71.385 14.230 74.025 ;
      RECT 14.030 71.065 14.290 71.385 ;
      RECT 14.510 86.605 14.770 86.925 ;
      RECT 14.570 82.485 14.710 86.605 ;
      RECT 14.510 82.165 14.770 82.485 ;
      RECT 14.570 79.525 14.710 82.165 ;
      RECT 14.510 79.205 14.770 79.525 ;
      RECT 22.670 86.605 22.930 86.925 ;
      RECT 22.730 81.375 22.870 86.605 ;
      RECT 22.670 81.055 22.930 81.375 ;
      RECT 40.010 83.595 40.150 88.510 ;
      RECT 39.950 83.275 40.210 83.595 ;
    LAYER met3 ;
      RECT 1.035 345.280 1.365 345.610 ;
      RECT 1.050 344.965 1.350 345.280 ;
      RECT 0.895 344.665 1.350 344.965 ;
      RECT 3.915 347.110 4.245 347.440 ;
      RECT 3.930 346.370 4.230 347.110 ;
      RECT 1.100 346.370 3.930 346.670 ;
      RECT 4.890 347.735 5.835 348.035 ;
      RECT 5.835 347.720 6.165 348.050 ;
      RECT 0.895 348.075 4.890 348.375 ;
      RECT 4.890 348.035 5.190 348.375 ;
      RECT 0.895 349.780 1.035 350.080 ;
      RECT 1.035 349.765 1.365 350.095 ;
      RECT 1.100 351.185 1.350 351.785 ;
      RECT 1.050 351.100 1.350 351.185 ;
      RECT 1.035 350.770 1.365 351.100 ;
      RECT 4.890 352.615 5.835 352.915 ;
      RECT 5.835 352.600 6.165 352.930 ;
      RECT 0.895 353.190 4.890 353.490 ;
      RECT 4.890 352.915 5.190 353.490 ;
      RECT 4.890 354.445 5.835 354.745 ;
      RECT 5.835 354.430 6.165 354.760 ;
      RECT 1.100 354.895 4.890 355.195 ;
      RECT 4.890 354.745 5.190 355.195 ;
      RECT 0.250 355.665 1.035 355.965 ;
      RECT 1.035 355.650 1.365 355.980 ;
      RECT 0.250 355.965 0.550 356.300 ;
      RECT 1.100 358.005 1.350 358.605 ;
      RECT 1.050 357.810 1.350 358.005 ;
      RECT 1.035 357.480 1.365 357.810 ;
      RECT 1.100 360.010 3.930 360.310 ;
      RECT 3.930 359.640 4.230 360.310 ;
      RECT 3.915 359.310 4.245 359.640 ;
      RECT 5.835 362.360 6.165 362.690 ;
      RECT 5.850 361.715 6.150 362.360 ;
      RECT 1.100 361.715 5.850 362.015 ;
      RECT 1.035 364.190 1.365 364.520 ;
      RECT 1.050 363.720 1.350 364.190 ;
      RECT 0.895 363.420 1.350 363.720 ;
      RECT 19.275 372.120 19.605 372.135 ;
      RECT 19.275 372.435 19.605 372.450 ;
      RECT 19.275 372.135 39.915 372.435 ;
      RECT 39.915 372.120 40.245 372.450 ;
  END
END data_blk

END LIBRARY
